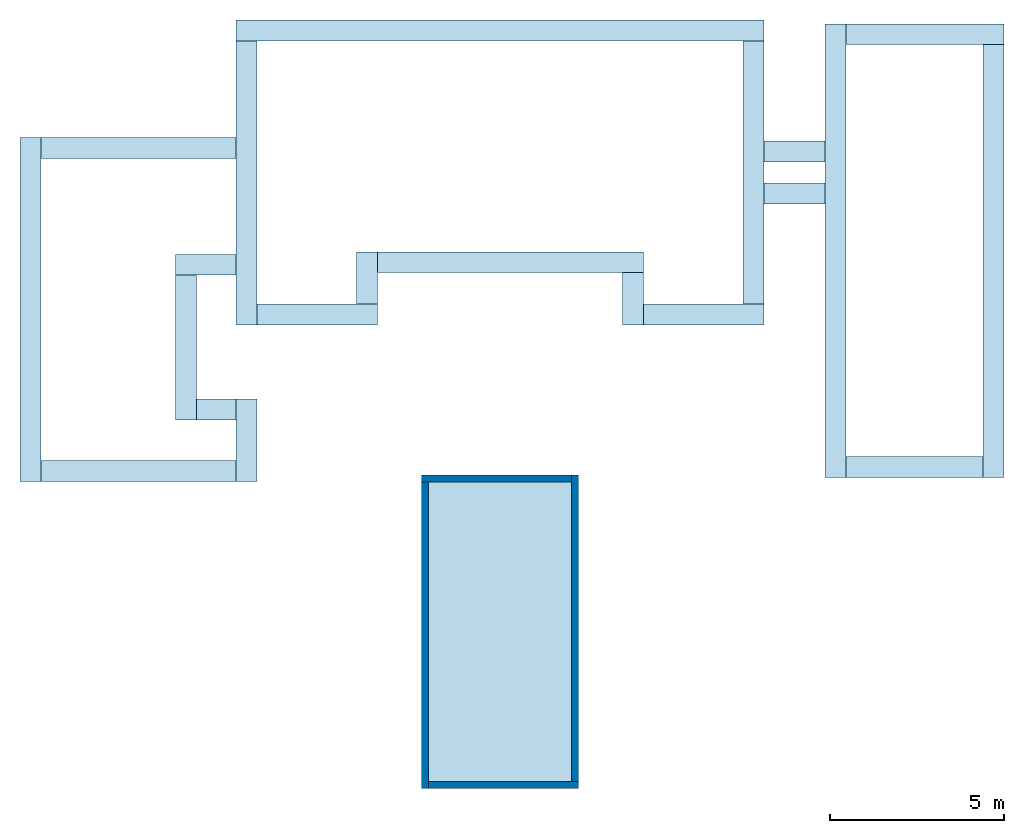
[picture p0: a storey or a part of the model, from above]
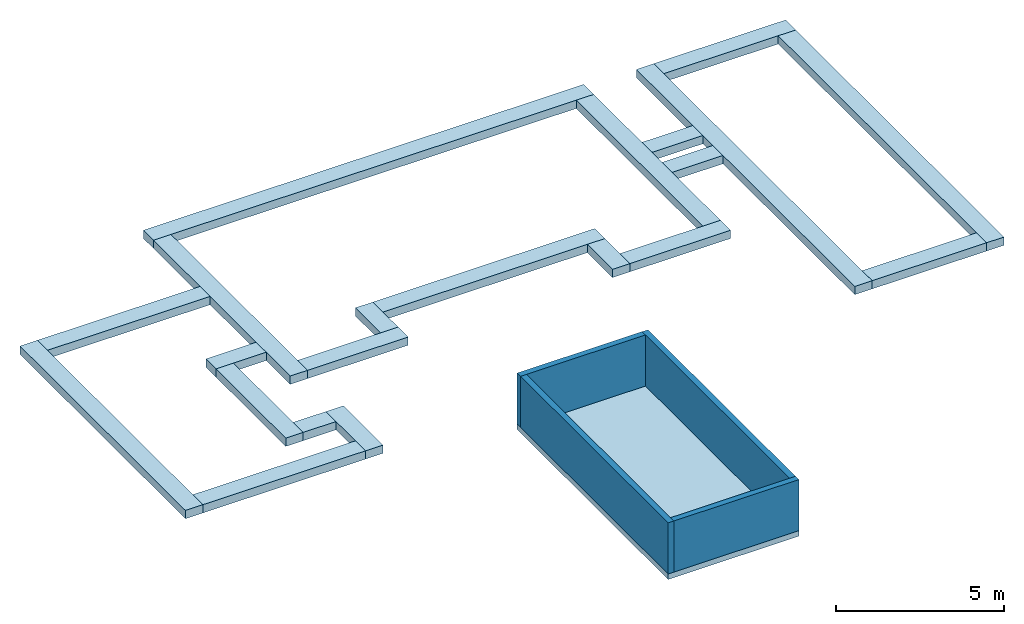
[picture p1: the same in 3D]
Properties of the parts of a building model (IFC2X3), part 1 of 4

# File
Description: ViewDefinition [CoordinationView_V2.0, QuantityTakeOffAddOnView]
File name: 4
Time: 2018-02-28T15:12:32
Written by: The EXPRESS Data Manager Version 5.02.0100.07 : 28 Aug 2013
Made in: 20150220_1215(x64) - Exporter 16.6.0.0 - Interface alternative d'export 16.6.0.0
Comment: STEP Physical File produced by: The EXPRESS Data Manager Version 5.02.0100.07 : 28 Aug 2013 * Module: EDMstepFileFactory/EDMstandAlone * Creation date: Wed Feb 28 15:12:32 2018 * Host: ESTEBAN-PASCAL * Database: C:\Users\Pascal\AppData\Local\Temp\{EC5FFBB5-4C97-4CA5-B8AF-28A79EC34BFA}\ifc * Database version: 5507 * Database creation date: Wed Feb 28 15:12:17 2018 * Schema: IFC2X3 * Model: DataRepository.ifc * Model creation date: Wed Feb 28 15:12:22 2018 * Header model: DataRepository.ifc_HeaderModel * Header model creation date: Wed Feb 28 15:12:22 2018 * EDMuser: sdai-user * EDMgroup: sdai-group * License ID and type: 5605 : Permanent license. Expiry date: * EDMstepFileFactory options: 020000

# IfcProject, 4
LongName: Projet Formation Revit 2016 - Module Initiation; Phase: Etat du projet

# IfcSite, Surface:366192
RefLatitude: 48, 51, 23, 999633; RefLongitude: 2, 21, 3, 553905; RefElevation: 0 m
Autre - Catégorie: Topographie; Déblais: 0 m3; Déblais/remblais net: 0 m3; Remblais: 0 m3
Cotes - Surface: 898.202 m2; Surface projetée: 898.173 m2
Phase de construction - Phase de création: Nouvelle construction

# IfcBuilding
Pset_BuildingCommon - NumberOfStoreys: 8
Autre - Adresse du projet: Entrer l'adresse ici; Catégorie: Informations sur le projet; Date de fin du projet: Mars 2017; Etat du projet: Etat du projet; Nom du client: Pascal Esteban; Nom du projet: Projet Formation Revit 2016 - Module Initiation; Numéro de projet: 4

# IfcBuildingStorey (8)
Autre - Catégorie: Niveaux; Famille: Niveau: Ligne du Niveau; Famille et type: Niveau: Ligne du Niveau; ID du type: Niveau: Ligne du Niveau; Type: Niveau: Ligne du Niveau
Cotes - Hauteur de calcul: 0 m
Données d'identification - Structure: no; Etage de bâtiment: yes
Autre(Type) - Catégorie: Niveaux; Nom de la famille: Niveau
Contraintes(Type) - Base de l'élévation: Point de base du projet
Données d'identification(Type) - Nom du type: Ligne du Niveau
Graphismes(Type) - Couleur: 12632256; Epaisseur des lignes: 1; Motif des lignes: Tiret point; Symbole: Marqueur de niveau - Point triangulaire: Marqueur de niveau - Point triangulaire; Valeur par défaut du symbole à l'extrémité 1: no; Valeur par défaut du symbole à l'extrémité 2: yes
Name | LongName = Nom | Elevation (m) | Elévation (m)
PIscine | PIscine | -2.2 | -2.2
1 Mur de soubassement | 1 Mur de soubassement | -1 | -1
RDC | RDC | -1.09416e-13 | 0
RDC Faux Plafond | RDC Faux Plafond | 2.5 | 2.5
1er ETAGE | 1er ETAGE | 3 | 3
RDC Acrotère | RDC Acrotère | 3.2 | 3.2
Mur rideau | Mur rideau | 5 | 5
1er Chainage | 1er Chainage | 5.8 | 5.8

# IfcSpace (24)
InteriorOrExteriorSpace: INTERNAL
BaseQuantities - Height: 2.4384 m
Analyse d'énergie - Charge d'éclairage basse sur: <Par défaut>; Charge d'éclairage réelle par surface: 0; Charge d'éclairage spécifiée: 0 W; Charge d'éclairage spécifiée par surface: 10.7639; Charge de puissance basse sur: <Par défaut>; Charge de puissance réelle: 0 W; Charge de puissance réelle par surface: 0; Charge de puissance spécifiée: 0 W; Charge de puissance spécifiée par surface: 13.9931; Charge réelle d'éclairage: 0 W; Contribution à l'éclairage du plénum: 0.2; Gain de chaleur latente par personne: 630.918; Gain de chaleur perceptible par personne: 788.648; Gain de chaleur total par personne: 1419.57; Nombre de personnes: 0; Surface par personne: 28.5714 m2; Unités de charge d'éclairage: Densité de puissance; Unités de charge de puissance: Densité de puissance; Valeurs de charge de chauffage: <Par défaut>
Autre - Catégorie: Pièces; ID de phase: Nouvelle construction
Contraintes - Décalage inférieur: 0 m; Décalage limite: 2.4384 m
Cotes - Hauteur de calcul: 0 m; Hauteur non liée: 2.4384 m
Phase de construction - Phase: Nouvelle construction
Name | In | LongName = Nomenclature des pièces, Nom = Données d'identification, Nom | Reference | Nombre = Numéro | Nomenclature des pièces, Niveau = Contraintes, Niveau | NetFloorArea (m2) = GrossFloorArea (m2) = Surface (m2) | GrossPerimeter (m) | GrossVolume (m3) | Limite supérieure | Périmètre (m)
1 | RDC | Salle d'eau | Salle d'eau 1 | 1 | RDC | 1.63725 | 5.39 | 3.99227 | Niveau: RDC | 5.39
2 | RDC | Chambre 1 | Chambre 1 2 | 2 | RDC | 13.674 | 14.96 | 33.3427 | Niveau: RDC | 14.96
3 | RDC | Dégmt ch | Dégmt ch 3 | 3 | RDC | 1.44 | 4.8 | 3.5113 | Niveau: RDC | 4.8
4 | RDC | Chambre 2 | Chambre 2 4 | 4 | Niveau: RDC | 22.038 | 23.94 | 53.7375 | Niveau: RDC | 23.94
5 | RDC | Placard ch. 2 | Placard ch. 2 5 | 5 | Niveau: RDC | 0.9016 | 4.84 | 2.19846 | Niveau: RDC | 4.84
6 | RDC | Passerelle | Passerelle 6 | 6 | RDC | 2.5 | 6.5 | 6.096 | Niveau: RDC | 6.5
7 | RDC | Gaine | Gaine 7 | 7 | Niveau: RDC | 0.28372 | 2.204 | 0.691823 | Niveau: RDC | 2.204
8 | RDC | Placard ch. 1 | Placard ch. 1 8 | 8 | Niveau: RDC | 1.0388 | 4.98 | 2.53301 | Niveau: RDC | 4.98
9 | RDC | Salle de bain ch. 2 | Salle de bain ch. 2 9 | 9 | RDC | 5.65307 | 11.85 | 13.7844 | Niveau: RDC | 11.85
10 | RDC | Garage | Garage 10 | 10 | RDC | 39.655 | 30.14 | 96.6948 | Niveau: RDC | 30.175
11 | RDC | Dgmt garage | Dgmt garage 11 | 11 | RDC | 2.718 | 6.93 | 6.62757 | Niveau: RDC | 6.84922
12 | RDC | Cellier | Cellier 12 | 12 | RDC | 6.72 | 10.6 | 16.386 | Niveau: RDC | 10.6
13 | RDC | Salon | Salon 13 | 13 | RDC | 19.5219 | 18.48 | 47.6022 | Niveau: RDC | 18.48
14 | RDC | Escalier | Escalier 14 | 14 | Niveau: RDC | 7.2267 | 10.96 | 17.6216 | Niveau: RDC | 10.96
15 | RDC | Entrée | Entrée 15 | 15 | RDC | 9.03204 | 12.5707 | 22.0237 | Niveau: RDC | 12.0237
16 | RDC | Circulation | Circulation 16 | 16 | RDC | 12.912 | 23.92 | 31.4846 | Niveau: RDC | 23.3689
17 | RDC | Dgmt cellier | Dgmt cellier 17 | 17 | Niveau: RDC | 4.374 | 9.69 | 10.6656 | Niveau: RDC | 9.76
18 | RDC | Placard entrée | Placard entrée 18 | 18 | RDC | 1.49435 | 8.01 | 3.64382 | Niveau: RDC | 8.01
19 | RDC | Espace lecture | Espace lecture 19 | 19 | Niveau: RDC | 10.2139 | 12.95 | 24.9056 | Niveau: RDC | 12.95
20 | RDC | Salle à manger | Salle à manger 20 | 20 | RDC | 14.6431 | 19.01 | 35.7057 | Niveau: RDC | 18.798
21 | RDC | Cuisine | Cuisine 21 | 21 | RDC | 12.3324 | 14.12 | 30.0713 | Niveau: RDC | 14.085
22 | RDC | Salle de bain ch. 1 | Salle de bain ch. 1 22 | 22 | RDC | 5.72307 | 11.99 | 13.9551 | Niveau: RDC | 11.99
23 | RDC | WC | WC 23 | 23 | Niveau: RDC | 2.124 | 5.94 | 5.17916 | Niveau: RDC | 6.07
24 | 1er ETAGE | Mezzanine | Mezzanine 24 | 24 | Niveau: 1er ETAGE | 58.6738 | 44.02 | 143.07 | Niveau: 1er ETAGE | 44.185

# IfcBeam: Poutre - Lamellé-collé - Pin du sud:127X279 (11)
In: 1er ETAGE
Type - PredefinedType: BEAM
Type - Autre(Type) - Catégorie: Ossature; Nom de la famille: Poutre - Lamellé-collé - Pin du sud
Type - Cotes(Type) - b: 0.127 m; d: 0.279 m
Type - Données d'identification(Type) - Nom du type: 127X279
Type - Structure(Type) - Forme de coupe: 0
Material: Bois - Bois de construction de dimensions courantes
Pset_BeamCommon - LoadBearing: yes; IsExternal: no; Reference: 127X279; Slope: 0 deg
Autre - Catégorie: Ossature; Famille: Poutre - Lamellé-collé - Pin du sud: 127X279; Famille et type: Poutre - Lamellé-collé - Pin du sud: 127X279; ID du type: Poutre - Lamellé-collé - Pin du sud: 127X279; Type: Poutre - Lamellé-collé - Pin du sud: 127X279
Contraintes - Décalage du niveau d'arrivée: 0 m; Décalage du niveau de départ: 0 m; Elévation du niveau de référence: 3 m; Niveau de référence: Niveau: 1er ETAGE; Orientation: Normale; Plan de construction: Niveau : 1er ETAGE; Rotation de la section: 0 deg
Cotes - Elévation à la base: 2.721 m; Elévation en haut: 3 m
Matériaux et finitions - Matériau structurel: Bois - Bois de construction de dimensions courantes
Phase de construction - Phase de création: Nouvelle construction
Position géométrique - Etat de la jonction: Deux jonctions activées; Extension de départ: 0 m; Extension de fin: 0 m; Justification Y: Origine; Justification YZ: Uniforme; Justification Z: Haut; Valeur de décalage Y: 0 m; Valeur de décalage Z: 0 m
Structure - Activer le modèle analytique: yes; Emplacement du symbole filaire: Centre de la géométrie; Utilisation structurelle: Autre
Name (Poutre - Lamellé-collé - Pin du sud:127X279:...) | GrossVolume (m3) = NetVolume (m3) = Volume (m3) | NetSurfaceArea (m2) | Longueur (m) | Longueur de coupe (m) | Group | Réduction du joint d'extrémité (m)
307954 | 0.15835 | 3.69969 | 4.469 | 4.469 | Groupe de modèles:Groupe de réseaux 1:310685
310688 | 0.15835 | 3.69969 | 4.569 | 4.469 | Groupe de modèles:Groupe de réseaux 1:310690 | 0
310720 | 0.15835 | 3.69969 | 4.569 | 4.469 | Groupe de modèles:Groupe de réseaux 1:310722 | 0
310724 | 0.15835 | 3.69969 | 4.569 | 4.469 |  | 0
310728 | 0.15835 | 3.69969 | 4.569 | 4.469 | Groupe de modèles:Groupe de réseaux 1:310730 | 0
311005 | 0.15835 | 3.69969 | 4.569 | 4.469 | Groupe de modèles:Groupe de réseaux 1:311007 | 0
311008 | 0.15835 | 3.69969 | 4.569 | 4.469 | Groupe de modèles:Groupe de réseaux 1:311010 | 0
311011 | 0.15835 | 3.69969 | 4.569 | 4.469 | Groupe de modèles:Groupe de réseaux 1:311013 | 0
311014 | 0.15835 | 3.69969 | 4.569 | 4.469 |  | 0
311017 | 0.15835 | 3.69969 | 4.569 | 4.469 | Groupe de modèles:Groupe de réseaux 1:311019 | 0
318877 | 0.0778817 | 1.85564 | 2.326 | 2.198 |  | 0 | Position géométrique - Réduction du joint de début: 0 m

# IfcBeam: Poutre rectangulaire - Béton:200 x 400 mm, Poutre rectangulaire - Béton:200 x 400 mm:311577
In: 1er ETAGE
Type - PredefinedType: BEAM
Type - Autre(Type) - Catégorie: Ossature; Nom de la famille: Poutre rectangulaire - Béton
Type - Cotes(Type) - b: 0.2 m; h: 0.4 m
Type - Données d'identification(Type) - Nom du type: 200 x 400 mm
Type - Structure(Type) - Forme de coupe: 0
Material: Béton - Béton coulé sur place
BaseQuantities - GrossVolume: 1.14016 m3; NetSurfaceArea: 17.2624 m2; NetVolume: 1.14016 m3
Pset_BeamCommon - LoadBearing: yes; IsExternal: no; Slope: 0 deg; Reference: 200 x 400 mm
Autre - Catégorie: Ossature; Famille: Poutre rectangulaire - Béton: 200 x 400 mm; Famille et type: Poutre rectangulaire - Béton: 200 x 400 mm; ID du type: Poutre rectangulaire - Béton: 200 x 400 mm; Type: Poutre rectangulaire - Béton: 200 x 400 mm
Contraintes - Décalage du niveau d'arrivée: 0 m; Décalage du niveau de départ: 0 m; Niveau de référence: Niveau: 1er ETAGE; Orientation: Normale; Rotation de la section: 0 deg; Elévation du niveau de référence: 3 m; Plan de construction: Niveau : 1er ETAGE
Cotes - Elévation à la base: 2.6 m; Elévation en haut: 3 m; Longueur: 14.339 m; Surface: 8.63118 m2; Volume: 1.14016 m3
Matériaux et finitions - Matériau structurel: Béton - Béton coulé sur place
Phase de construction - Phase de création: Nouvelle construction
Position géométrique - Justification Y: Origine; Justification YZ: Uniforme; Justification Z: Haut; Valeur de décalage Y: 0 m; Valeur de décalage Z: 0 m; Etat de la jonction: Une ou deux jonctions activées
Structure - Activer le modèle analytique: yes; Enrobage d'armature - Autres faces: Paramètres de l'enrobage d'armature: Enrobage d'armature 1; Enrobage d'armature - Face inférieure: Paramètres de l'enrobage d'armature: Enrobage d'armature 1; Enrobage d'armature - Face supérieure: Paramètres de l'enrobage d'armature: Enrobage d'armature 1; Utilisation structurelle: Autre; Longueur de coupe: 14.252 m

# IfcBuildingElementProxy: 100 mm, TV - Ecran plat:100 mm:445774
In: 13
Type - Material: TV - Cadre, TV - Noir, TV - Verre
Type - Autre(Type) - Catégorie: Equipement spécialisé; Nom de la famille: TV - Ecran plat
Type - Cotes(Type) - CosAng: 0.000871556 m; Diagonale: 1 m; Epaisseur: 0.08 m; H: 0.490295 m; L: 0.871556 m; SinAng: 0.000490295 m
Type - Données d'identification(Type) - Nom du type: 100 mm
Type - Matériaux et finitions(Type) - Cadre: TV - Cadre
Pset_BuildingElementProxyCommon - Reference: 100 mm
Autre - Catégorie: Equipement spécialisé; Famille: TV - Ecran plat: 100 mm; Famille et type: TV - Ecran plat: 100 mm; ID du type: TV - Ecran plat: 100 mm; Type: TV - Ecran plat: 100 mm
Contraintes - Niveau: Niveau: RDC; Se déplace avec les éléments voisins: no; Décalage: 0.42 m; Hôte: Sol : S5 Plancher flottant habitable
Cotes - Surface: 1.48572 m2; Volume: 0.0550081 m3
Graphismes - Pied: yes
Phase de construction - Phase de création: Nouvelle construction

# IfcBuildingElementProxy: 1456153326143_Kitchen_ExhaustHood, 1456153326143_Kitchen_ExhaustHood:1456153326143_Kitchen_ExhaustHood:540276
In: 21
Type - Material: Sp. Equipment - Kitchen Exhaust Hood - Metal Accent2, Sp. Equipment - Kitchen Exhaust Hood - Metal Accent1, Sp. Equipment - Kitchen Exhaust Hood - Hood Edge
Type - Autre(Type) - Catégorie: Equipement spécialisé; LIGHTING OFF: yes; Nom de la famille: 1456153326143_Kitchen_ExhaustHood
Type - Cotes(Type) - Hood Depth: 0.1016 m
Type - Données d'identification(Type) - Nom du type: 1456153326143_Kitchen_ExhaustHood
Pset_BuildingElementProxyCommon - Reference: 1456153326143_Kitchen_ExhaustHood
Autre - Catégorie: Equipement spécialisé; Famille: 1456153326143_Kitchen_ExhaustHood: 1456153326143_Kitchen_ExhaustHood; Famille et type: 1456153326143_Kitchen_ExhaustHood: 1456153326143_Kitchen_ExhaustHood; ID du type: 1456153326143_Kitchen_ExhaustHood: 1456153326143_Kitchen_ExhaustHood; LS_L: 0.9 m; Type: 1456153326143_Kitchen_ExhaustHood: 1456153326143_Kitchen_ExhaustHood
Contraintes - Niveau: Niveau: RDC; Se déplace avec les éléments voisins: no; Décalage: -0.54 m; Hôte: Sol : Plan de travail cuisine
Cotes - B.O Hood to Floor: 1.35 m; Exhaust Length: 0.2286 m; Exhaust Width: 0.2286 m; Hood Length: 0.9144 m; Hood Width: 0.6096 m; Surface: 7.51254 m2; T.O. Hood to Floor: 2.3622 m; Volume: 0.968507 m3
Matériaux et finitions - Hood Edge: Sp. Equipment - Kitchen Exhaust Hood - Hood Edge; Metal Accent 1: Sp. Equipment - Kitchen Exhaust Hood - Metal Accent1; Metal Accent2: Sp. Equipment - Kitchen Exhaust Hood - Metal Accent2
Phase de construction - Phase de création: Nouvelle construction

# IfcBuildingElementProxy: 600mm x 590mm x 820mm (3)
In: 12
Type - Material: Peinture - Ivoire
Type - Autre(Type) - Catégorie: Equipement spécialisé; Nom de la famille: Sèche linge - 01
Type - Cotes(Type) - Hauteur: 0.82 m; Largeur: 0.6 m; Profondeur: 0.59 m
Type - Données d'identification(Type) - Nom du type: 600mm x 590mm x 820mm
Type - Matériaux et finitions(Type) - Finition: Peinture - Ivoire
Pset_BuildingElementProxyCommon - Reference: 600mm x 590mm x 820mm
Autre - Catégorie: Equipement spécialisé; Famille: Sèche linge - 01: 600mm x 590mm x 820mm; Famille et type: Sèche linge - 01: 600mm x 590mm x 820mm; ID du type: Sèche linge - 01: 600mm x 590mm x 820mm; Type: Sèche linge - 01: 600mm x 590mm x 820mm
Contraintes - Niveau: Niveau: RDC; Se déplace avec les éléments voisins: no; Décalage: 0 m; Hôte: Sol : S5 Plancher flottant habitable
Cotes - Surface: 1.8173 m2; Volume: 0.292316 m3
Phase de construction - Phase de création: Nouvelle construction
Name (Sèche linge - 01:600mm x 590mm x 820mm:...)
424746
551144
551240

# IfcBuildingElementProxy: 600mm x 590mm x 820mm, Lave linge - Chargement frontal:600mm x 590mm x 820mm:423703
In: 12
Type - Material: Peinture - Ivoire, Verre
Type - Autre(Type) - Catégorie: Equipement spécialisé; Nom de la famille: Lave linge - Chargement frontal
Type - Cotes(Type) - Hauteur: 0.82 m; Largeur: 0.6 m; Profondeur: 0.59 m
Type - Données d'identification(Type) - Nom du type: 600mm x 590mm x 820mm
Type - Matériaux et finitions(Type) - Finition: Peinture - Ivoire
Pset_BuildingElementProxyCommon - Reference: 600mm x 590mm x 820mm
Autre - Catégorie: Equipement spécialisé; Famille: Lave linge - Chargement frontal: 600mm x 590mm x 820mm; Famille et type: Lave linge - Chargement frontal: 600mm x 590mm x 820mm; ID du type: Lave linge - Chargement frontal: 600mm x 590mm x 820mm; Type: Lave linge - Chargement frontal: 600mm x 590mm x 820mm
Contraintes - Niveau: Niveau: RDC; Se déplace avec les éléments voisins: no; Décalage: 0 m; Hôte: Sol : S5 Plancher flottant habitable
Cotes - Surface: 2.15169 m2; Volume: 0.247328 m3
Phase de construction - Phase de création: Nouvelle construction

# IfcBuildingElementProxy: 915 x 500 mm, Plaque de cuisson - 4 unités:915 x 500 mm:543399
In: 21
Type - Material: Métal - Chrome, Métal - Acier, Poli
Type - Autre(Type) - Catégorie: Equipement spécialisé; Nom de la famille: Plaque de cuisson - 4 unités
Type - Cotes(Type) - Largeur: 0.915 m; Profondeur: 0.5 m
Type - Données d'identification(Type) - Nom du type: 915 x 500 mm
Type - Matériaux et finitions(Type) - Brûleur: Métal - Chrome; Plaque de cuisson: Métal - Acier, Poli
Pset_BuildingElementProxyCommon - Reference: 915 x 500 mm
Autre - Catégorie: Equipement spécialisé; Famille: Plaque de cuisson - 4 unités: 915 x 500 mm; Famille et type: Plaque de cuisson - 4 unités: 915 x 500 mm; ID du type: Plaque de cuisson - 4 unités: 915 x 500 mm; Type: Plaque de cuisson - 4 unités: 915 x 500 mm
Contraintes - Niveau: Niveau: RDC; Se déplace avec les éléments voisins: no; Décalage: 0 m; Hôte: Sol : S5 Plancher flottant habitable
Cotes - Surface: 0.741723 m2; Volume: 0.0101652 m3
Phase de construction - Phase de création: Nouvelle construction

# IfcBuildingElementProxy: Chêne écarlate - 6 mètres, RPC Arbre - Feuilles caduques:Chêne écarlate - 6 mètres:369386
In: RDC
Type - Autre(Type) - Catégorie: Plantes; Nom de la famille: RPC Arbre - Feuilles caduques
Type - Cotes(Type) - Hauteur: 6 m
Type - Données d'identification(Type) - Apparence de rendu: RPC-16-G0FB-J5PX-0LX6-U000-ST1L-LVER-AU; Commentaires du type: Chêne écarlate; Nom du type: Chêne écarlate - 6 mètres; Propriétés de l'apparence de rendu: {2, 15},{39, RPC-16-G0FB-J5PX-0LX6-U000-ST1L-LVER-AU},{1, 0},{1, 0},{2, 13},{1, 8},{5, Color},{1, 0},{1, 0},{3, 0.8},{3, 0.8},{3, 0.8},{1, 8},{7, BBoxMin},{1, 0},{1, 0},{1, 0},{1, 0},{1, 0},{1, 8},{7, BBoxMax},{1, 0},{1, 0},{1, 0},{1, 0},{1, 0},{2, 11},{9, RPCTypeId},{1, 0},{1, 0},{39, RPC-16-G0FB-J5PX-0LX6-U000-ST1L-LVER-AU},{1, 6},{14, RPCPlantHeight},{1, 0},{1, 0},{7, 41.0105},{2, 11},{7, keyword},{1, 0},{1, 0},{34, :RPCs:Trees [General]:Geometry:RPC},{2, 11},{8, category},{1, 0},{1, 0},{15, Trees [General]},{2, 11},{12, LocalizedUID},{1, 0},{1, 0},{11, Scarlet_Oak},{2, 14},{6, Height},{1, 0},{1, 0},{7, 41.0105},{1, 2},{16, Cast Reflections},{1, 0},{1, 0},{1, 0},{1, 2},{12, Cast Shadows},{1, 0},{1, 0},{1, 1},{1, 2},{9, Lock View},{1, 0},{1, 0},{1, 0},{1, 4},{5, ViewC},{1, 0},{1, 0},{1, 0},{21, assetlibrary_base.fbx},{1, 5},
Pset_BuildingElementProxyCommon - Reference: Chêne écarlate - 6 mètres
Autre - Catégorie: Plantes; Famille: RPC Arbre - Feuilles caduques: Chêne écarlate - 6 mètres; Famille et type: RPC Arbre - Feuilles caduques: Chêne écarlate - 6 mètres; ID du type: RPC Arbre - Feuilles caduques: Chêne écarlate - 6 mètres; Type: RPC Arbre - Feuilles caduques: Chêne écarlate - 6 mètres
Contraintes - Niveau: Niveau: RDC; Se déplace avec les éléments voisins: no; Décalage: 0 m; Hôte: Surface
Phase de construction - Phase de création: Nouvelle construction

# IfcBuildingElementProxy: Chêne écarlate - 8 mètres (2)
In: RDC
Type - Autre(Type) - Catégorie: Plantes; Nom de la famille: RPC Arbre - Feuilles caduques
Type - Cotes(Type) - Hauteur: 8 m
Type - Données d'identification(Type) - Apparence de rendu: RPC-16-G0FB-J5PX-0LX6-U000-ST1L-LVER-AU; Commentaires du type: Chêne écarlate; Nom du type: Chêne écarlate - 8 mètres; Propriétés de l'apparence de rendu: {2, 15},{39, RPC-16-G0FB-J5PX-0LX6-U000-ST1L-LVER-AU},{1, 0},{1, 0},{2, 13},{1, 8},{5, Color},{1, 0},{1, 0},{3, 0.8},{3, 0.8},{3, 0.8},{1, 8},{7, BBoxMin},{1, 0},{1, 0},{1, 0},{1, 0},{1, 0},{1, 8},{7, BBoxMax},{1, 0},{1, 0},{1, 0},{1, 0},{1, 0},{2, 11},{9, RPCTypeId},{1, 0},{1, 0},{39, RPC-16-G0FB-J5PX-0LX6-U000-ST1L-LVER-AU},{1, 6},{14, RPCPlantHeight},{1, 0},{1, 0},{7, 41.0105},{2, 11},{7, keyword},{1, 0},{1, 0},{34, :RPCs:Trees [General]:Geometry:RPC},{2, 11},{8, category},{1, 0},{1, 0},{15, Trees [General]},{2, 11},{12, LocalizedUID},{1, 0},{1, 0},{11, Scarlet_Oak},{2, 14},{6, Height},{1, 0},{1, 0},{7, 41.0105},{1, 2},{16, Cast Reflections},{1, 0},{1, 0},{1, 0},{1, 2},{12, Cast Shadows},{1, 0},{1, 0},{1, 1},{1, 2},{9, Lock View},{1, 0},{1, 0},{1, 0},{1, 4},{5, ViewC},{1, 0},{1, 0},{1, 0},{21, assetlibrary_base.fbx},{1, 5},
Pset_BuildingElementProxyCommon - Reference: Chêne écarlate - 8 mètres
Autre - Catégorie: Plantes; Famille: RPC Arbre - Feuilles caduques: Chêne écarlate - 8 mètres; Famille et type: RPC Arbre - Feuilles caduques: Chêne écarlate - 8 mètres; ID du type: RPC Arbre - Feuilles caduques: Chêne écarlate - 8 mètres; Type: RPC Arbre - Feuilles caduques: Chêne écarlate - 8 mètres
Contraintes - Niveau: Niveau: RDC; Se déplace avec les éléments voisins: no; Décalage: 0 m; Hôte: Surface
Phase de construction - Phase de création: Nouvelle construction
Name (RPC Arbre - Feuilles caduques:Chêne écarlate - 8 mètres:...)
369457
369516

# IfcBuildingElementProxy: FERME (3)
In: 1er Chainage
Type - Material: bois de charpente
Type - Autre(Type) - Catégorie: Ossature; demi panne: 0.06 m; Nom de la famille: FERME; Recouvrement mur: 0.3 m
Type - Cotes(Type) - angle d'inclinaison: 19.29 deg; hauteur arbaletrier: 0.2 m; section h entrait: 0.3 m; section h faitiere: 0.22 m; section p entrait: 0.25 m; section p panne faitiere: 0.12 m; section p sablière: 0.12 m
Type - Données d'identification(Type) - Nom du type: FERME
Type - Structure(Type) - Forme de coupe: 0
Pset_BuildingElementProxyCommon - Reference: FERME
Autre - Catégorie: Ossature; demi poincon: 0.1 m; Famille: FERME: FERME; Famille et type: FERME: FERME; ID du type: FERME: FERME; longueur arbaletrier: 4.02603 m; nombre de pannes: 1; position panne intermediaire: 2.01301 m; Type: FERME: FERME; vis p1: yes; vis p2: no; vis p3: no; vis p4: no
Construction - pannes: yes
Contraintes - Décalage: 0.5 m; Hôte: Niveau : 1er Chainage; Niveau: Niveau: 1er Chainage; Se déplace avec les éléments voisins: no
Cotes - largeur ferme: 7.8 m; Section h contrefiche: 0.2 m; section h panne intermediaire: 0.22 m; section poincon: 0.2 m; section p panne intermediaire: 0.1 m
Matériaux et finitions - Matériau structurel: bois de charpente
Phase de construction - Phase de création: Nouvelle construction
Structure - Enrobage d'armature - Autres faces: Paramètres de l'enrobage d'armature: Enrobage d'armature 1; Enrobage d'armature - Face inférieure: Paramètres de l'enrobage d'armature: Enrobage d'armature 1; Enrobage d'armature - Face supérieure: Paramètres de l'enrobage d'armature: Enrobage d'armature 1; Utilisation structurelle: Autre
Name (FERME:FERME:...) | Longueur debord (m) | Longueur panne (m) | Surface (m2) | Volume (m3)
340418 | 3.44427 | 0.135733 | 23.3554 | 1.64093
346890 | 3.44427 | 0.135733 | 23.3554 | 1.64093
346964 | 3.7007 | 3.6993 | 36.8101 | 2.08505

# IfcBuildingElementProxy: Mechanical_COM_Popup-Toaster, Mechanical_COM_Popup-Toaster:Mechanical_COM_Popup-Toaster:545730
In: 21
Type - Material: ARCAT - Plastic - Black, ARCAT - Metal - Satin Steel
Type - Autre(Type) - Catégorie: Equipement de génie climatique; Nom de la famille: Mechanical_COM_Popup-Toaster
Type - Construction(Type) - Four Compartments: no; Two Compartments: yes
Type - Contraintes(Type) - Elévation par défaut: 1.2192 m; fourcompartmentvoid: 0.03175 m; fourcomparttrigger: 0.0254 m; twocomparttrigger: 0.0762 m; twocompartvoid: 0.174625 m
Type - Cotes(Type) - Unit Depth: 0.2159 m; Unit Height: 0.22225 m; Unit Width: 0.3429 m
Type - Données d'identification(Type) - Company_ID: 0; Nom du type: Mechanical_COM_Popup-Toaster; Numéro OmniClass: 23.40.40.14; Titre OmniClass: Food Service Equipment
Type - Phase de construction(Type) - Expected Lifespan (Years): 0; Maintenance Schedule (Months): 0; Warranty Duration (Years): 0
Pset_BuildingElementProxyCommon - Reference: Mechanical_COM_Popup-Toaster
Autre - Niveau de nomenclature: Niveau: RDC; Catégorie: Equipement de génie climatique; Famille: Mechanical_COM_Popup-Toaster: Mechanical_COM_Popup-Toaster; Famille et type: Mechanical_COM_Popup-Toaster: Mechanical_COM_Popup-Toaster; ID du type: Mechanical_COM_Popup-Toaster: Mechanical_COM_Popup-Toaster; Type: Mechanical_COM_Popup-Toaster: Mechanical_COM_Popup-Toaster
Contraintes - Niveau: Niveau: RDC; Décalage: 0 m; Plan de construction: PTD : Avec réservation pour évier
Cotes - Surface: 0.325476 m2; Volume: 0.012359 m3
Données d'identification - Identifiant: 1
Génie climatique - Classification du système: Puissance
Matériaux et finitions - Face Plate: ARCAT - Plastic - Black; Feet Material: ARCAT - Plastic - Black; Fixture Material: ARCAT - Metal - Satin Steel; Hardware Finish: ARCAT - Plastic - Black
Phase de construction - Phase de création: Nouvelle construction

# IfcBuildingElementProxy: Palmier - 6 m (7)
In: RDC
Type - Autre(Type) - Catégorie: Plantes; Nom de la famille: Arbre 3D - Palmier
Type - Cotes(Type) - Hauteur: 6 m
Type - Données d'identification(Type) - Apparence de rendu: RPC-16-FVGV-NKG0-7NHH-C000-ST1L-LVER-AU; Nom du type: Palmier - 6 m; Numéro OmniClass: 23.40.05.00; Titre OmniClass: Plants and Planting Products
Pset_BuildingElementProxyCommon - Reference: Palmier - 6 m
Autre - Catégorie: Plantes; Famille: Arbre 3D - Palmier: Palmier - 6 m; Famille et type: Arbre 3D - Palmier: Palmier - 6 m; ID du type: Arbre 3D - Palmier: Palmier - 6 m; Type: Arbre 3D - Palmier: Palmier - 6 m
Contraintes - Niveau: Niveau: RDC; Se déplace avec les éléments voisins: no; Décalage: 0 m; Hôte: Surface
Phase de construction - Phase de création: Nouvelle construction
Name (Arbre 3D - Palmier:Palmier - 6 m:...)
378889
379057
379459
379478
379527
379637
379660

# IfcBuildingElementProxy: Palmier - 8 m (2)
In: RDC
Type - Autre(Type) - Catégorie: Plantes; Nom de la famille: Arbre 3D - Palmier
Type - Cotes(Type) - Hauteur: 8 m
Type - Données d'identification(Type) - Apparence de rendu: RPC-16-FVGV-NKG0-7NHH-C000-ST1L-LVER-AU; Nom du type: Palmier - 8 m; Numéro OmniClass: 23.40.05.00; Titre OmniClass: Plants and Planting Products
Pset_BuildingElementProxyCommon - Reference: Palmier - 8 m
Autre - Catégorie: Plantes; Famille: Arbre 3D - Palmier: Palmier - 8 m; Famille et type: Arbre 3D - Palmier: Palmier - 8 m; ID du type: Arbre 3D - Palmier: Palmier - 8 m; Type: Arbre 3D - Palmier: Palmier - 8 m
Contraintes - Niveau: Niveau: RDC; Se déplace avec les éléments voisins: no; Décalage: 0 m; Hôte: Surface
Phase de construction - Phase de création: Nouvelle construction
Name (Arbre 3D - Palmier:Palmier - 8 m:...)
378946
379369

# IfcBuildingElementProxy: Palmier -3 m (5)
Type - Autre(Type) - Catégorie: Plantes; Nom de la famille: Arbre 3D - Palmier
Type - Cotes(Type) - Hauteur: 3 m
Type - Données d'identification(Type) - Apparence de rendu: RPC-16-FVGV-NKG0-7NHH-C000-ST1L-LVER-AU; Nom du type: Palmier -3 m; Numéro OmniClass: 23.40.05.00; Titre OmniClass: Plants and Planting Products
Pset_BuildingElementProxyCommon - Reference: Palmier -3 m
Autre - Catégorie: Plantes; Famille: Arbre 3D - Palmier: Palmier -3 m; Famille et type: Arbre 3D - Palmier: Palmier -3 m; ID du type: Arbre 3D - Palmier: Palmier -3 m; Type: Arbre 3D - Palmier: Palmier -3 m
Contraintes - Se déplace avec les éléments voisins: no; Décalage: 0 m
Phase de construction - Phase de création: Nouvelle construction
Name (Arbre 3D - Palmier:Palmier -3 m:...) | In | Niveau | Hôte
379821 | RDC | Niveau: RDC | Niveau : RDC
379847 | 1 Mur de soubassement | Niveau: 1 Mur de soubassement | Surface
379902 | 1 Mur de soubassement | Niveau: 1 Mur de soubassement | Surface
379955 | 1 Mur de soubassement | Niveau: 1 Mur de soubassement | Surface
379998 | 1 Mur de soubassement | Niveau: 1 Mur de soubassement | Surface

# IfcBuildingElementProxy: Panneaux solaires sur support (3)
In: RDC Acrotère
Type - Material: Panneau solaire, Peinture - Gris métallisé
Type - Autre(Type) - Catégorie: Equipement spécialisé; Nom de la famille: Panneaux solaires sur support
Type - Contraintes(Type) - Longueur: 3.6 m; Longueur de barre: 1.8 m; Nombre de barres: 2; Nombre de panneaux: 6; Nombre de supports: 3
Type - Cotes(Type) - Hauteur support arrière: 0.7 m; Hauteur support avant: 0.3 m; Largeur des panneaux: 0.6 m; Profondeur des panneaux: 1.2 m
Type - Données d'identification(Type) - Nom du type: Panneaux solaires sur support
Type - Matériaux et finitions(Type) - Cadre des panneaux: Peinture - Gris métallisé; Finition des supports: Peinture - Gris métallisé
Pset_BuildingElementProxyCommon - Reference: Panneaux solaires sur support
Autre - Catégorie: Equipement spécialisé; Famille: Panneaux solaires sur support: Panneaux solaires sur support; Famille et type: Panneaux solaires sur support: Panneaux solaires sur support; ID du type: Panneaux solaires sur support: Panneaux solaires sur support; Type: Panneaux solaires sur support: Panneaux solaires sur support
Contraintes - Se déplace avec les éléments voisins: no; Décalage: 3.2 m; Hôte: Sol : Dallage garage; Niveau: Niveau: RDC Acrotère
Cotes - Surface: 6.27012 m2; Volume: 0.0689049 m3
Phase de construction - Phase de création: Nouvelle construction
Name (Panneaux solaires sur support:Panneaux solaires sur support:...)
453073
453309
453405

# IfcBuildingElementProxy: RPC Coccinelle, RPC Coccinelle:RPC Coccinelle:382846
In: RDC
Type - Autre(Type) - Catégorie: Environnement; Nom de la famille: RPC Coccinelle
Type - Cotes(Type) - Hauteur: 0 m
Type - Données d'identification(Type) - Apparence de rendu: RPC-16-0U6E-L4EG-ENH1-J3KF-SVEL-0TX4-C0; Nom du type: RPC Coccinelle; Propriétés de l'apparence de rendu: {2, 15},{39, RPC-16-0U6E-L4EG-ENH1-J3KF-SVEL-0TX4-C0},{1, 0},{1, 0},{2, 45},{1, 8},{5, Color},{1, 0},{1, 0},{3, 0.8},{3, 0.8},{3, 0.8},{1, 8},{7, BBoxMin},{1, 0},{1, 0},{1, 0},{1, 0},{1, 0},{1, 8},{7, BBoxMax},{1, 0},{1, 0},{1, 0},{1, 0},{1, 0},{2, 11},{9, RPCTypeId},{1, 0},{1, 0},{39, RPC-16-0U6E-L4EG-ENH1-J3KF-SVEL-0TX4-C0},{1, 6},{14, RPCPlantHeight},{1, 0},{1, 0},{4, 4.92},{2, 11},{7, keyword},{1, 0},{1, 0},{27, :Geometry:RPC:VW Beetle [4]},{2, 11},{8, category},{1, 0},{1, 0},{21, :Auto_Economy/Midsize},{2, 11},{12, LocalizedUID},{1, 0},{1, 0},{13, VW Beetle [4]},{2, 14},{6, Height},{1, 0},{1, 0},{4, 4.92},{1, 2},{16, Cast Reflections},{1, 0},{1, 0},{1, 0},{1, 4},{12, Transparency},{1, 0},{1, 0},{2, 18},{1, 4},{7, Tinting},{1, 0},{1, 0},{2, 50},{1, 2},{11, Use Tinting},{1, 0},{1, 0},{1, 0},{1, 2},{13, License Plate},{1, 0},{1, 0},{1, 0},{2, 11},{21, License Plate Texture},{1, 0},{1, 0},{64, __RPC:/object data/textures/car/plate/textures/default/rgb/0/0/0},{2, 11},{23, i_License Plate Texture},{1, 0},{1, 0},{0, },{1, 2},{12, Custom Plate},{1, 0},{1, 0},{1, 0},{2, 11},{23, License Plate File Name},{1, 0},{1, 0},{0, },{2, 11},{20, AdvancedUIDefinition},{1, 0},{1, 0},{0, },{2, 11},{10, AssetLibID},{1, 0},{1, 0},{36, 4D3F6E72-3F99-4203-98E9-AF80B3C7A7A4},{2, 11},{10, BaseSchema},{1, 0},{1, 0},{9, RPCSchema},{2, 11},{12, ExchangeGUID},{1, 0},{1, 0},{0, },{1, 2},{6, Hidden},{1, 0},{1, 0},{1, 0},{1, 4},{11, RPCCategory},{1, 0},{1, 0},{1, 0},{2, 11},{8, RPCImage},{1, 0},{1, 0},{0, },{1, 4},{13, SchemaVersion},{1, 0},{1, 0},{1, 4},{2, 11},{12, UIDefinition},{1, 0},{1, 0},{0, },{2, 11},{6, UIName},{1, 0},{1, 0},{39, RPC-16-0U6E-L4EG-ENH1-J3KF-SVEL-0TX4-C0},{2, 11},{11, VersionGUID},{1, 0},{1, 0},{9, RPCSchema},{2, 11},{9, assettype},{1, 0},{1, 0},{11, RPCGeometry},{2, 11},{11, description},{1, 0},{1, 0},{0, },{2, 11},{9, localname},{1, 0},{1, 0},{3, RPC},{2, 11},{9, localtype},{1, 0},{1, 0},{3, RPC},{1, 4},{8, revision},{1, 0},{1, 0},{1, 1},{2, 11},{9, thumbnail},{1, 0},{1, 0},{0, },{1, 4},{7, version},{1, 0},{1, 0},{1, 1},{1, 2},{20, RPC_Cast Reflections},{1, 0},{1, 0},{1, 0},{1, 4},{16, RPC_Transparency},{1, 0},{1, 0},{2, 18},{1, 4},{11, RPC_Tinting},{1, 0},{1, 0},{2, 50},{1, 2},{15, RPC_Use Tinting},{1, 0},{1, 0},{1, 0},{1, 2},{17, RPC_License Plate},{1, 0},{1, 0},{1, 0},{2, 11},{25, RPC_License Plate Texture},{1, 0},{1, 0},{64, __RPC:/object data/textures/car/plate/textures/default/rgb/0/0/0},{2, 11},{27, RPC_i_License Plate Texture},{1, 0},{1, 0},{0, },{1, 2},{16, RPC_Custom Plate},{1, 0},{1, 0},{1, 0},{2, 11},{27, RPC_License Plate File Name},{1, 0},{1, 0},{0, },{21, assetlibrary_base.fbx},{1, 5},
Pset_BuildingElementProxyCommon - Reference: RPC Coccinelle
Autre - Catégorie: Environnement; Famille: RPC Coccinelle: RPC Coccinelle; Famille et type: RPC Coccinelle: RPC Coccinelle; ID du type: RPC Coccinelle: RPC Coccinelle; Type: RPC Coccinelle: RPC Coccinelle
Contraintes - Niveau: Niveau: RDC; Se déplace avec les éléments voisins: no; Décalage: -0.1 m; Hôte: Niveau : RDC
Phase de construction - Phase de création: Nouvelle construction

# IfcBuildingElementProxy: RPC Ordinateur portable, RPC Ordinateur portable:RPC Ordinateur portable:538196
In: 13
Type - Autre(Type) - Catégorie: Environnement; Nom de la famille: RPC Ordinateur portable
Type - Cotes(Type) - Hauteur: 0 m
Type - Données d'identification(Type) - Apparence de rendu: RPC-16-N04H-AQSP-D1N4-43SU-6GKQ-C3KU-1C; Nom du type: RPC Ordinateur portable; Propriétés de l'apparence de rendu: {2, 15},{39, RPC-16-N04H-AQSP-D1N4-43SU-6GKQ-C3KU-1C},{1, 0},{1, 0},{2, 16},{1, 8},{5, Color},{1, 0},{1, 0},{3, 0.8},{3, 0.8},{3, 0.8},{1, 8},{7, BBoxMin},{1, 0},{1, 0},{1, 0},{1, 0},{1, 0},{1, 8},{7, BBoxMax},{1, 0},{1, 0},{1, 0},{1, 0},{1, 0},{2, 11},{9, RPCTypeId},{1, 0},{1, 0},{39, RPC-16-N04H-AQSP-D1N4-43SU-6GKQ-C3KU-1C},{1, 6},{14, RPCPlantHeight},{1, 0},{1, 0},{7, 2.28517},{2, 11},{7, keyword},{1, 0},{1, 0},{33, :RPCs:Office Clutter:Geometry:RPC},{2, 11},{8, category},{1, 0},{1, 0},{14, Office Clutter},{2, 11},{12, LocalizedUID},{1, 0},{1, 0},{17, Notebook Computer},{2, 14},{6, Height},{1, 0},{1, 0},{7, 2.28517},{1, 2},{16, Cast Reflections},{1, 0},{1, 0},{1, 0},{1, 4},{4, Open},{1, 0},{1, 0},{4, -106},{1, 2},{5, Power},{1, 0},{1, 0},{1, 1},{2, 11},{14, Screen Preview},{1, 0},{1, 0},{70, __RPC:/object data/textures/object/Top/TopScreen/textures/on/rgb/0/0/0},{2, 11},{16, i_Screen Preview},{1, 0},{1, 0},{0, },{1, 2},{13, Custom Screen},{1, 0},{1, 0},{1, 0},{2, 11},{16, Screen File Name},{1, 0},{1, 0},{0, },{21, assetlibrary_base.fbx},{1, 5},
Pset_BuildingElementProxyCommon - Reference: RPC Ordinateur portable
Autre - Catégorie: Environnement; Famille: RPC Ordinateur portable: RPC Ordinateur portable; Famille et type: RPC Ordinateur portable: RPC Ordinateur portable; ID du type: RPC Ordinateur portable: RPC Ordinateur portable; Type: RPC Ordinateur portable: RPC Ordinateur portable
Contraintes - Niveau: Niveau: RDC; Se déplace avec les éléments voisins: no; Décalage: 0.37 m; Hôte: Sol : S5 Plancher flottant habitable
Phase de construction - Phase de création: Nouvelle construction

# IfcColumn: 200 mm x 400 mm (2)
In: 1 Mur de soubassement
Type - ElementType: 200 mm x 400 mm; PredefinedType: COLUMN
Type - Autre(Type) - Catégorie: Poteaux porteurs; Nom de la famille: Poteau béton - Rectangulaire
Type - Cotes(Type) - b: 0.2 m; h: 0.4 m
Type - Données d'identification(Type) - Nom du type: 200 mm x 400 mm
Type - Structure(Type) - Forme de coupe: 0
Material: Maçonnerie - Béton coulé sur place
BaseQuantities - GrossVolume: 0.2624 m3
Pset_ColumnCommon - LoadBearing: yes; IsExternal: no; Slope: 0 deg; Reference: 200 mm x 400 mm
Autre - Catégorie: Poteaux porteurs; Famille: Poteau béton - Rectangulaire: 200 mm x 400 mm; Famille et type: Poteau béton - Rectangulaire: 200 mm x 400 mm; ID du type: Poteau béton - Rectangulaire: 200 mm x 400 mm; Type: Poteau béton - Rectangulaire: 200 mm x 400 mm
Contraintes - Décalage inférieur: 0 m; Limite de pièce: yes; Décalage supérieur: -0.4 m; Niveau: Niveau: 1 Mur de soubassement; Niveau de base: Niveau: 1 Mur de soubassement; Niveau supérieur: Niveau: 1er ETAGE; Se déplace avec les quadrillages: yes; Style de poteau: Vertical
Cotes - Longueur: 3.6 m; Surface: 2.128 m2; Volume: 0.2624 m3
Matériaux et finitions - Matériau structurel: Maçonnerie - Béton coulé sur place
Phase de construction - Phase de création: Nouvelle construction
Structure - Activer le modèle analytique: yes; Enrobage d'armature - Autres faces: Paramètres de l'enrobage d'armature: Enrobage d'armature 1; Enrobage d'armature - Face inférieure: Paramètres de l'enrobage d'armature: Enrobage d'armature 1
Name (Poteau béton - Rectangulaire:200 mm x 400 mm:...)
314299
315225

# IfcCovering: Plafond composé:Plafond ba13 (2)
In: RDC Faux Plafond
PredefinedType: CEILING; Material: Plâtre 0.015 m
Pset_CoveringCommon - Reference: Plafond ba13; TotalThickness: 0.015 m
Autre - Catégorie: Plafonds; Famille: Plafond composé: Plafond ba13; Famille et type: Plafond composé: Plafond ba13; ID du type: Plafond composé: Plafond ba13; Type: Plafond composé: Plafond ba13
Contraintes - Limite de pièce: yes; Décalage par rapport au niveau: 0 m; Niveau: Niveau: RDC Faux Plafond
Phase de construction - Phase de création: Nouvelle construction
Autre(Type) - Catégorie: Plafonds; Nom de la famille: Plafond composé
Construction(Type) - Epaisseur: 0.015 m
Données d'identification(Type) - Nom du type: Plafond ba13
Graphismes(Type) - Couleur vue détail faible: 0
Propriétés analytiques(Type) - Rugosité: 3; Coefficient d'absorbance: 0.7
Name (Plafond composé:Plafond ba13:...) | GrossCeilingArea (m2) = Surface (m2) | Périmètre (m) | Volume (m3)
323722 | 50.9183 | 74.96 | 0.763774
328247 | 63.4209 | 76.6206 | 0.951313

# IfcCurtainWall: Mur-rideau:Simple panneau, Mur-rideau:Simple panneau:298383
In: RDC
Type - Autre(Type) - Catégorie: Murs; Nom de la famille: Mur-rideau
Type - Construction(Type) - Fonction: Extérieur; Condition de jonction: Bord et quadrillage vertical continu; Encastrement automatique: yes; Panneau de mur-rideau: Panneau système: Vitré
Type - Données d'identification(Type) - Nom du type: Simple panneau
Type - Quadrillage horizontal(Type) - Espacement: 2 m; Présentation: Aucun; Régler pour la taille du meneau: yes
Type - Quadrillage vertical(Type) - Présentation: Aucun; Régler pour la taille du meneau: yes; Espacement: 1 m
Pset_CurtainWallCommon - IsExternal: yes; Reference: Simple panneau
Nomenclature de mur - Famille: Mur-rideau: Simple panneau; Famille et type: Mur-rideau: Simple panneau; Longueur: 7.73 m; Surface: 37 m2; Commentaires: porteur
Relevé de matériaux de mur détaillé - Famille et type: Mur-rideau: Simple panneau; sets with these values: 2
Autre - Catégorie: Murs; Famille: Mur-rideau: Simple panneau; Famille et type: Mur-rideau: Simple panneau; ID du type: Mur-rideau: Simple panneau; Type: Mur-rideau: Simple panneau
Contraintes - Décalage inférieur: 0 m; Contrainte inférieure: Niveau: RDC; Décalage supérieur: 0 m; Lié au volume: no; Limite de pièce: yes; Partie inférieure attachée: no; Partie supérieure attachée: no; Hauteur non contrainte: 5 m
Cotes - Longueur: 7.73 m; Surface: 37 m2
Données d'identification - Commentaires: porteur
Phase de construction - Phase de création: Nouvelle construction
Quadrillage horizontal - Angle: 0 deg; Décaler: 0 m; Justification: Début; Nombre: 4; sets with these values: 2
Structure - Activer le modèle analytique: no; Structure: no; Utilisation structurelle: Non porteur

# IfcCurtainWall: Mur-rideau:Simple panneau 2 (2)
In: RDC
Type - Autre(Type) - Catégorie: Murs; Nom de la famille: Mur-rideau
Type - Construction(Type) - Fonction: Intérieur; Condition de jonction: Bord et quadrillage vertical continu; Encastrement automatique: yes; Panneau de mur-rideau: Panneau système: Vitré
Type - Données d'identification(Type) - Nom du type: Simple panneau 2
Type - Quadrillage horizontal(Type) - Présentation: Aucun; Régler pour la taille du meneau: yes; Espacement: 2 m
Type - Quadrillage vertical(Type) - Présentation: Aucun; Régler pour la taille du meneau: yes; Espacement: 1 m
Pset_CurtainWallCommon - IsExternal: no; Reference: Simple panneau 2
Relevé de matériaux de mur détaillé - Famille et type: Mur-rideau: Simple panneau 2; sets with these values: 2
Autre - Catégorie: Murs; Famille: Mur-rideau: Simple panneau 2; Famille et type: Mur-rideau: Simple panneau 2; ID du type: Mur-rideau: Simple panneau 2; Type: Mur-rideau: Simple panneau 2
Contraintes - Décalage inférieur: 0 m; Contrainte inférieure: Niveau: RDC; Décalage supérieur: 0 m; Lié au volume: no; Limite de pièce: yes; Partie inférieure attachée: no; Partie supérieure attachée: no; Contrainte supérieure: Niveau: 1er ETAGE; Hauteur non contrainte: 3 m
Cotes - Longueur: 2.34 m; Surface: 6 m2
Phase de construction - Phase de création: Nouvelle construction
Quadrillage horizontal - Angle: 0 deg; Justification: Début; Nombre: 4; Décaler: 0.1 m
Quadrillage vertical - Angle: 0 deg; Décaler: 0 m; Justification: Début; Nombre: 4
Structure - Activer le modèle analytique: no; Structure: no; Utilisation structurelle: Non porteur
Name (Mur-rideau:Simple panneau 2:...)
360755
363813

# IfcDoor: 3m x 2m, Garage basculante:3m x 2m:293000
In: RDC
Type - OperationType: ROLLINGUP; ParameterTakesPrecedence: no; Sizeable: no; Material: Peinture - Grise
Type - Garage basculante:3m x 2m:293000 - PanelOperation: ROLLINGUP
Type - Autre(Type) - Catégorie: Portes; Nom de la famille: Garage basculante
Type - Construction(Type) - Fonction: Extérieur; Fermeture du mur: Par hôte
Type - Cotes(Type) - Hauteur: 2 m; Hauteur de la poignée: 0.5 m; Largeur: 2.4 m; Largeur du cadre: 0.06 m
Type - Données d'identification(Type) - Marque de type: 32; Nom du type: 3m x 2m
Type - Matériaux et finitions(Type) - Cadre: Peinture - Grise; Panneau: Peinture - Grise; Poignée: Plastique - Noir
Type - Propriétés analytiques(Type) - Coefficient d'apport thermique solaire: 0; Transmission de la lumière visible: 0; Coefficient de transfert de chaleur (U): 3.7021; Construction analytique: Métal; Résistance thermique (R): 0.270117
OverallHeight: 2.43 m; OverallWidth: 2.015 m
Pset_DoorCommon - IsExternal: yes; Reference: 3m x 2m; ThermalTransmittance: 3.7021 kg/K/s3
Nomenclature des portes - Visible dans les nomenclatures: yes; Famille et type: Garage basculante: 3m x 2m; Largeur: 2.4 m; Hauteur: 2 m; Niveau: Niveau: RDC
BaseQuantities - Height: 2 m; Width: 2.4 m; Area: 4.8 m2
Autre - Catégorie: Portes; ID hôte: Mur de base: Ext. Crépis 2 + BBMC 20; Famille: Garage basculante: 3m x 2m; Famille et type: Garage basculante: 3m x 2m; Hauteur sous linteau: 2 m; ID du type: Garage basculante: 3m x 2m; Type: Garage basculante: 3m x 2m
Contraintes - Hauteur de l'appui: 0 m; Niveau: Niveau: RDC
Cotes - Surface: 5.6962 m2; Volume: 0.21156 m3
Données d'identification - Visible dans les nomenclatures: yes; Identifiant: 15
Phase de construction - Phase de création: Nouvelle construction

# IfcDoor: Double vitrée, Double vitrée:Double vitrée:300905
In: RDC
Type - OperationType: DOUBLE_DOOR_SINGLE_SWING; ParameterTakesPrecedence: no; Sizeable: no; Material: Porte - Cadre, PVC - Blanc, Verre
Type - Double vitrée:Double vitrée:300905 - PanelOperation: SWINGING
Type - Autre(Type) - Catégorie: Portes; Nom de la famille: Double vitrée
Type - Construction(Type) - Fonction: Extérieur
Type - Contraintes(Type) - Pos. Panneau (Auto): 0.025 m; Pos. Poignée: 0.05 m; Sys: 0 m
Type - Cotes(Type) - Déc. Bord: 0.01 m; Epaisseur: 0.05 m; Hauteur de la poignée: 1 m; Largeur du cadre: 0.05 m; Largeur du cadre_2: 0.1 m; Prof. Dormants: 0.07 m
Type - Données d'identification(Type) - Nom du type: Double vitrée
Type - Matériaux et finitions(Type) - Dormants: Porte - Cadre; Panneau: PVC - Blanc; Poignée: Porte - Poignée
Type - Propriétés analytiques(Type) - Coefficient d'apport thermique solaire: 0; Transmission de la lumière visible: 0; Coefficient de transfert de chaleur (U): 3.7021; Construction analytique: Métal; Résistance thermique (R): 0.270117
OverallHeight: 2.12 m; OverallWidth: 2.40667 m
Autre - Catégorie: Portes; ID hôte: Mur-rideau: Simple panneau; Famille: Double vitrée: Double vitrée; Famille et type: Double vitrée: Double vitrée; ID du type: Double vitrée: Double vitrée; Type: Double vitrée: Double vitrée
Contraintes - Niveau: Niveau: RDC
Cotes - Hauteur: 2.12 m; Largeur: 2.40667 m; Surface: 5.10213 m2; Volume: 0.119035 m3
Phase de construction - Phase de création: Nouvelle construction
Pset_DoorCommon - IsExternal: yes; Reference: Double vitrée; ThermalTransmittance: 3.7021 kg/K/s3
Nomenclature des portes - Famille et type: Double vitrée: Double vitrée; Largeur: 2.40667 m; Hauteur: 2.12 m; Niveau: Niveau: RDC

# IfcDoor: Lisse - 0.90 m x 2.15 m, Ext. Simple:Lisse - 0.90 m x 2.15 m:438744
In: RDC
Type - OperationType: SINGLE_SWING_RIGHT; ParameterTakesPrecedence: no; Sizeable: no; Material: PVC - Blanc
Type - Ext. Simple:Lisse - 0.90 m x 2.15 m:438744 - PanelOperation: SWINGING
Type - Autre(Type) - Catégorie: Portes; Nom de la famille: Ext. Simple
Type - Construction(Type) - Fonction: Extérieur; Fermeture du mur: Par hôte
Type - Cotes(Type) - Epaisseur: 0.05 m; Epaisseur d'isolation: 0.1 m; Hauteur: 2.15 m; Largeur: 0.9 m
Type - Données d'identification(Type) - Marque de type: 39; Nom du type: Lisse - 0.90 m x 2.15 m
Type - Graphismes(Type) - Type de panneau: Panneau plein
Type - Matériaux et finitions(Type) - Cadre: PVC - Blanc; Panneau: PVC - Blanc; Poignée: PVC - Blanc
Type - Propriétés analytiques(Type) - Coefficient d'apport thermique solaire: 0.86; Coefficient de transfert de chaleur (U): 5.5617; Construction analytique: Grandes fenêtres à vitrage simple; Résistance thermique (R): 0.179801; Transmission de la lumière visible: 0.9
OverallHeight: 2.2 m; OverallWidth: 1 m
Pset_DoorCommon - IsExternal: yes; Reference: Lisse - 0.90 m x 2.15 m; ThermalTransmittance: 5.5617 kg/K/s3
Nomenclature des portes - Famille et type: Ext. Simple: Lisse - 0.90 m x 2.15 m; Largeur: 0.9 m; Hauteur: 2.15 m; Niveau: Niveau: RDC
BaseQuantities - Height: 2.15 m; Width: 0.9 m; Area: 1.935 m2
Autre - Catégorie: Portes; ID hôte: Mur de base: M7 Ext. Crépis 2 + BBMC 20 + Isolant 11; Famille: Ext. Simple: Lisse - 0.90 m x 2.15 m; Famille et type: Ext. Simple: Lisse - 0.90 m x 2.15 m; Hauteur sous linteau: 2.15 m; ID du type: Ext. Simple: Lisse - 0.90 m x 2.15 m; Type: Ext. Simple: Lisse - 0.90 m x 2.15 m
Contraintes - Hauteur de l'appui: 0 m; Niveau: Niveau: RDC
Cotes - Surface: 2.96758 m2; Volume: 0.0950052 m3
Données d'identification - Identifiant: 17
Graphismes - Angle d'ouverture 2D fixe: yes; Angle d'ouverture 3D: 20 deg
Phase de construction - Phase de création: Nouvelle construction

# IfcDoor: Ouverture en rectangle (2)
In: RDC
Type - ParameterTakesPrecedence: no; Sizeable: no; Material: Bois - Chêne
Type - Autre(Type) - Catégorie: Portes; Nom de la famille: Ouverture en rectangle
Type - Construction(Type) - Fonction: Intérieur; Fermeture du mur: Aucun
Type - Cotes(Type) - Hauteur: 2.1 m; Largeur: 1 m; Retour: 0.05 m
Type - Données d'identification(Type) - Marque de type: 29; Nom du type: Ouverture en rectangle
Type - Matériaux et finitions(Type) - Cadre: Bois - Chêne
Type - Propriétés analytiques(Type) - Construction analytique: <Aucun>
OverallHeight: 2.1 m; OverallWidth: 1 m
Pset_DoorCommon - IsExternal: no; Reference: Ouverture en rectangle
Nomenclature des portes - Famille et type: Ouverture en rectangle: Ouverture en rectangle; Largeur: 1 m; Hauteur: 2.1 m; Niveau: Niveau: RDC
BaseQuantities - Height: 2.1 m; Width: 1 m; Area: 2.1 m2
Autre - Catégorie: Portes; Famille: Ouverture en rectangle: Ouverture en rectangle; Famille et type: Ouverture en rectangle: Ouverture en rectangle; Hauteur sous linteau: 2.1 m; ID du type: Ouverture en rectangle: Ouverture en rectangle; Type: Ouverture en rectangle: Ouverture en rectangle
Contraintes - Niveau: Niveau: RDC; Hauteur de l'appui: 0 m
Graphismes - Avec huisserie: yes
Phase de construction - Phase de création: Nouvelle construction
Name (Ouverture en rectangle:Ouverture en rectangle:...) | ID hôte | Surface (m2) | Volume (m3) | Identifiant
275426 | Mur de base: M7 Ext. Crépis 2 + BBMC 20 + Isolant 11 | 1.9162 | 0.03612 | 13
275736 | Mur de base: M8 Ext. Bois 2 + Isolant 12 + BBMC 20 + vide 1 + ba13 | 2.0198 | 0.038184 | 14

# IfcDoor: PP (0.73m x 2.04m) (4)
In: RDC
Type - OperationType: SINGLE_SWING_LEFT; ParameterTakesPrecedence: no; Sizeable: no; Material: Bois - Panneau de porte, Bois - Cadre de porte
Type - Autre(Type) - Catégorie: Portes; Nom de la famille: Int. Simple
Type - Construction(Type) - Fonction: Intérieur; Fermeture du mur: Par hôte
Type - Cotes(Type) - Epaisseur: 0.04 m; Hauteur: 2.04 m; Largeur: 0.73 m
Type - Données d'identification(Type) - Marque de type: 26; Nom du type: PP (0.73m x 2.04m)
Type - Matériaux et finitions(Type) - Ajustement: Bois - Cadre de porte; Cadre: Bois - Cadre de porte; Panneau: Bois - Panneau de porte; Poignée: Finition Peinture - Blanc satiné
Type - Propriétés analytiques(Type) - Coefficient d'apport thermique solaire: 0; Coefficient de transfert de chaleur (U): 3.7021; Construction analytique: Métal; Résistance thermique (R): 0.270117; Transmission de la lumière visible: 0
Type - Int. Simple:PP (0.73m x 2.04m):273407 - PanelOperation: SWINGING
OverallHeight: 2.075 m; OverallWidth: 0.8 m
Pset_DoorCommon - IsExternal: no; Reference: PP (0.73m x 2.04m); ThermalTransmittance: 3.7021 kg/K/s3
Nomenclature des portes - Famille et type: Int. Simple: PP (0.73m x 2.04m); Largeur: 0.73 m; Hauteur: 2.04 m; Niveau: Niveau: RDC
BaseQuantities - Height: 2.04 m; Width: 0.73 m; Area: 1.4892 m2
Autre - Catégorie: Portes; Famille: Int. Simple: PP (0.73m x 2.04m); Famille et type: Int. Simple: PP (0.73m x 2.04m); ID du type: Int. Simple: PP (0.73m x 2.04m); ID hôte: Mur de base: Générique - Int. 70 mm; Type: Int. Simple: PP (0.73m x 2.04m); Hauteur sous linteau: 2.04 m
Contraintes - Niveau: Niveau: RDC; Hauteur de l'appui: 0 m
Cotes - Surface: 2.11485 m2; Volume: 0.071524 m3
Graphismes - Angle d'ouverture 2D fixe: yes; Angle d'ouverture 3D: 0 deg
Phase de construction - Phase de création: Nouvelle construction
Name (Int. Simple:PP (0.73m x 2.04m):...) | Identifiant
273407 | 6
273482 | 7
273553 | 9
273819 | 12

# IfcDoor: PP (0.73m x 2.04m) (4)
In: RDC
Type - OperationType: SINGLE_SWING_RIGHT; ParameterTakesPrecedence: no; Sizeable: no; Material: Bois - Panneau de porte, Bois - Cadre de porte
Type - Int. Simple:PP (0.73m x 2.04m):271522 - PanelOperation: SWINGING
Type - Autre(Type) - Catégorie: Portes; Nom de la famille: Int. Simple
Type - Construction(Type) - Fonction: Intérieur; Fermeture du mur: Par hôte
Type - Cotes(Type) - Epaisseur: 0.04 m; Hauteur: 2.04 m; Largeur: 0.73 m
Type - Données d'identification(Type) - Marque de type: 26; Nom du type: PP (0.73m x 2.04m)
Type - Matériaux et finitions(Type) - Ajustement: Bois - Cadre de porte; Cadre: Bois - Cadre de porte; Panneau: Bois - Panneau de porte; Poignée: Finition Peinture - Blanc satiné
Type - Propriétés analytiques(Type) - Coefficient d'apport thermique solaire: 0; Coefficient de transfert de chaleur (U): 3.7021; Construction analytique: Métal; Résistance thermique (R): 0.270117; Transmission de la lumière visible: 0
OverallHeight: 2.075 m; OverallWidth: 0.8 m
Pset_DoorCommon - IsExternal: no; Reference: PP (0.73m x 2.04m); ThermalTransmittance: 3.7021 kg/K/s3
Nomenclature des portes - Famille et type: Int. Simple: PP (0.73m x 2.04m); Largeur: 0.73 m; Hauteur: 2.04 m; Niveau: Niveau: RDC
BaseQuantities - Height: 2.04 m; Width: 0.73 m; Area: 1.4892 m2
Autre - Catégorie: Portes; Famille: Int. Simple: PP (0.73m x 2.04m); Famille et type: Int. Simple: PP (0.73m x 2.04m); Hauteur sous linteau: 2.04 m; ID du type: Int. Simple: PP (0.73m x 2.04m); ID hôte: Mur de base: Générique - Int. 70 mm; Type: Int. Simple: PP (0.73m x 2.04m)
Contraintes - Hauteur de l'appui: 0 m; Niveau: Niveau: RDC
Cotes - Surface: 2.11485 m2; Volume: 0.071524 m3
Graphismes - Angle d'ouverture 2D fixe: yes; Angle d'ouverture 3D: 0 deg
Phase de construction - Phase de création: Nouvelle construction
Name (Int. Simple:PP (0.73m x 2.04m):...) | Identifiant
271522 | 1 | Nomenclature des portes - Visible dans les nomenclatures: yes; Données d'identification - Visible dans les nomenclatures: yes
273523 | 8
273653 | 10
273705 | 11

# IfcDoor: PV Triangulaire (0.90 m x 2.15 m), Entrée (avec angle d'ouverture):PV Triangulaire (0.90 m x 2.15 m):422585
In: RDC
Type - OperationType: SINGLE_SWING_LEFT; ParameterTakesPrecedence: no; Sizeable: no; Material: Porte d'entrée - Panneau, Verre, Porte d'entrée - Cadre
Type - Entrée (avec angle d'ouverture):PV Triangulaire (0.90 m x 2.15 m):422585 - PanelOperation: SWINGING
Type - Autre(Type) - Catégorie: Portes; Nom de la famille: Entrée (avec angle d'ouverture)
Type - Construction(Type) - Fonction: Extérieur; Fermeture du mur: Extérieur
Type - Cotes(Type) - Epaisseur: 0.05 m; Epaisseur d'isolation: 0.1 m; Hauteur: 2.15 m; Largeur: 0.9 m
Type - Données d'identification(Type) - Marque de type: 34; Nom du type: PV Triangulaire (0.90 m x 2.15 m)
Type - Graphismes(Type) - Type de panneau: Panneau vitrage triangulaire
Type - Matériaux et finitions(Type) - Barreaux: Peinture - Noir; Cadre: Porte d'entrée - Cadre; Panneau: Porte d'entrée - Panneau; Poignée: Porte d'entrée - Poignée
Type - Propriétés analytiques(Type) - Coefficient d'apport thermique solaire: 0.86; Coefficient de transfert de chaleur (U): 5.5617; Construction analytique: Grandes fenêtres à vitrage simple; Résistance thermique (R): 0.179801; Transmission de la lumière visible: 0.9
OverallHeight: 2.19 m; OverallWidth: 0.98 m
Pset_DoorCommon - IsExternal: yes; Reference: PV Triangulaire (0.90 m x 2.15 m); ThermalTransmittance: 5.5617 kg/K/s3
Nomenclature des portes - Famille et type: Entrée (avec angle d'ouverture): PV Triangulaire (0.90 m x 2.15 m); Largeur: 0.9 m; Hauteur: 2.15 m; Niveau: Niveau: RDC
BaseQuantities - Height: 2.15 m; Width: 0.9 m; Area: 1.935 m2
Autre - Catégorie: Portes; ID hôte: Mur de base: M7 Ext. Crépis 2 + BBMC 20 + Isolant 11; Famille: Entrée (avec angle d'ouverture): PV Triangulaire (0.90 m x 2.15 m); Famille et type: Entrée (avec angle d'ouverture): PV Triangulaire (0.90 m x 2.15 m); Hauteur sous linteau: 2.15 m; ID du type: Entrée (avec angle d'ouverture): PV Triangulaire (0.90 m x 2.15 m); Type: Entrée (avec angle d'ouverture): PV Triangulaire (0.90 m x 2.15 m)
Contraintes - Niveau: Niveau: RDC; Hauteur de l'appui: 0 m
Cotes - Surface: 3.02036 m2; Volume: 0.0958856 m3
Données d'identification - Identifiant: 16
Phase de construction - Phase de création: Nouvelle construction

# IfcDoor: Placard coulissante - 3 panneaux (3)
In: RDC
Type - OperationType: SLIDING_TO_RIGHT; ParameterTakesPrecedence: no; Sizeable: no; Material: Placard - Profil, Placard - Encadrement, Placard - Porte
Type - Placard coulissante - 3 panneaux:Placard coulissante - 3 panneaux:273082 - PanelOperation: SLIDING
Type - Autre(Type) - Catégorie: Portes; Nom de la famille: Placard coulissante - 3 panneaux
Type - Construction(Type) - Fonction: Intérieur; Fermeture du mur: Aucun
Type - Cotes(Type) - Epaisseur: 0.02 m; Hauteur: 2.1 m; Largeur: 1.8 m; Largeur du cadre: 0.05 m
Type - Données d'identification(Type) - Marque de type: 28; Nom du type: Placard coulissante - 3 panneaux
Type - Graphismes(Type) - Profils: yes
Type - Matériaux et finitions(Type) - Cadre: Placard - Encadrement; Panneau: Placard - Porte; Profil: Placard - Profil
Type - Propriétés analytiques(Type) - Coefficient d'apport thermique solaire: 0; Transmission de la lumière visible: 0; Coefficient de transfert de chaleur (U): 3.7021; Construction analytique: Métal; Résistance thermique (R): 0.270117
OverallHeight: 2.1 m; OverallWidth: 1.8 m
Pset_DoorCommon - IsExternal: no; Reference: Placard coulissante - 3 panneaux; ThermalTransmittance: 3.7021 kg/K/s3
Nomenclature des portes - Famille et type: Placard coulissante - 3 panneaux: Placard coulissante - 3 panneaux; Largeur: 1.8 m; Hauteur: 2.1 m; Niveau: Niveau: RDC
BaseQuantities - Height: 2.1 m; Width: 1.8 m; Area: 3.78 m2
Autre - Catégorie: Portes; ID hôte: Mur de base: Générique - Int. 70 mm; Famille: Placard coulissante - 3 panneaux: Placard coulissante - 3 panneaux; Famille et type: Placard coulissante - 3 panneaux: Placard coulissante - 3 panneaux; Hauteur sous linteau: 2.1 m; ID du type: Placard coulissante - 3 panneaux: Placard coulissante - 3 panneaux; Type: Placard coulissante - 3 panneaux: Placard coulissante - 3 panneaux
Contraintes - Niveau: Niveau: RDC; Hauteur de l'appui: 0 m
Cotes - Surface: 4.154 m2; Volume: 0.0798 m3
Phase de construction - Phase de création: Nouvelle construction
Name (Placard coulissante - 3 panneaux:Placard coulissante - 3 panneaux:...) | Identifiant
273082 | 2
273212 | 4
273299 | 5

# IfcFlowSegment: Gouttière:Gouttière PVC:345603, Gouttière:Gouttière PVC:348524
In: 1er Chainage
Type - ElementType: Gouttière:Gouttière PVC:345603; PredefinedType: GUTTER
Pset_DistributionFlowElementCommon - Reference: Gouttière PVC
Autre - Catégorie: Gouttières; Famille: Gouttière: Gouttière PVC; Famille et type: Gouttière: Gouttière PVC; ID du type: Gouttière: Gouttière PVC; Type: Gouttière: Gouttière PVC
Contraintes - Décalage horizontal du profil: 0 m; Décalage vertical du profil: -0.15 m
Cotes - Longueur: 29.6 m
Phase de construction - Phase de création: Nouvelle construction
Profil - Angle: 0 deg
Autre(Type) - Catégorie: Gouttières; Nom de la famille: Gouttière
Données d'identification(Type) - Nom du type: Gouttière PVC
Matériaux et finitions(Type) - Matériau: Plastique, blanc opaque

# IfcFlowTerminal: 790mm x 500mm, Evier - Classique 2 bacs:790mm x 500mm:498837
In: 21
Material: Plastique - Blanc brillant, Plastique - Ton pierre
Pset_DistributionFlowElementCommon - Reference: 790mm x 500mm
Autre - Catégorie: Appareils sanitaires; Famille: Evier - Classique 2 bacs: 790mm x 500mm; Famille et type: Evier - Classique 2 bacs: 790mm x 500mm; ID du type: Evier - Classique 2 bacs: 790mm x 500mm; Type: Evier - Classique 2 bacs: 790mm x 500mm
Contraintes - Niveau: Niveau: RDC; Se déplace avec les éléments voisins: no; Décalage: 0 m; Hôte: Sol : S5 Plancher flottant habitable
Cotes - Surface: 0.925793 m2; Volume: 0.00491721 m3
Données d'identification - Identifiant: 21
Phase de construction - Phase de création: Nouvelle construction
Autre(Type) - Catégorie: Appareils sanitaires; Nom de la famille: Evier - Classique 2 bacs
Données d'identification(Type) - Nom du type: 790mm x 500mm
Matériaux et finitions(Type) - Matériau: Plastique - Ton pierre; Matériau de robinet: Plastique - Blanc brillant

# IfcFlowTerminal: Baignoire rectangulaire - Mur (2)
Material: Céramique - Blanche
Pset_DistributionFlowElementCommon - Reference: Baignoire rectangulaire - Mur
Autre - ID hôte: Mur de base: M8 Ext. Bois 2 + Isolant 12 + BBMC 20 + vide 1 + ba13; Catégorie: Appareils sanitaires; Famille: Baignoire rectangulaire - Mur: Baignoire rectangulaire - Mur; Famille et type: Baignoire rectangulaire - Mur: Baignoire rectangulaire - Mur; ID du type: Baignoire rectangulaire - Mur: Baignoire rectangulaire - Mur; Type: Baignoire rectangulaire - Mur: Baignoire rectangulaire - Mur
Contraintes - Niveau: Niveau: RDC
Cotes - Surface: 5.17925 m2; Volume: 0.105165 m3
Phase de construction - Phase de création: Nouvelle construction
Autre(Type) - Catégorie: Appareils sanitaires; Nom de la famille: Baignoire rectangulaire - Mur
Cotes(Type) - Hauteur: 0.6 m; Largeur: 1.525 m; Profondeur: 0.762 m
Données d'identification(Type) - Nom du type: Baignoire rectangulaire - Mur
Matériaux et finitions(Type) - Baignoire: Céramique - Blanche
Name (Baignoire rectangulaire - Mur:Baignoire rectangulaire - Mur:...) | In | Identifiant
384437 | 22 | 2
385515 | 9 | 4

# IfcFlowTerminal: Cuvette réservoir (3)
Material: Porcelaine - Lin, Stratifié - Lin, Mat
Pset_DistributionFlowElementCommon - Reference: Cuvette réservoir
Autre - Catégorie: Appareils sanitaires; Famille: Cuvette réservoir: Cuvette réservoir; Famille et type: Cuvette réservoir: Cuvette réservoir; ID du type: Cuvette réservoir: Cuvette réservoir; Type: Cuvette réservoir: Cuvette réservoir
Contraintes - Niveau: Niveau: RDC; Se déplace avec les éléments voisins: no; Décalage: 0 m
Cotes - Surface: 1.88455 m2; Volume: 0.0312525 m3
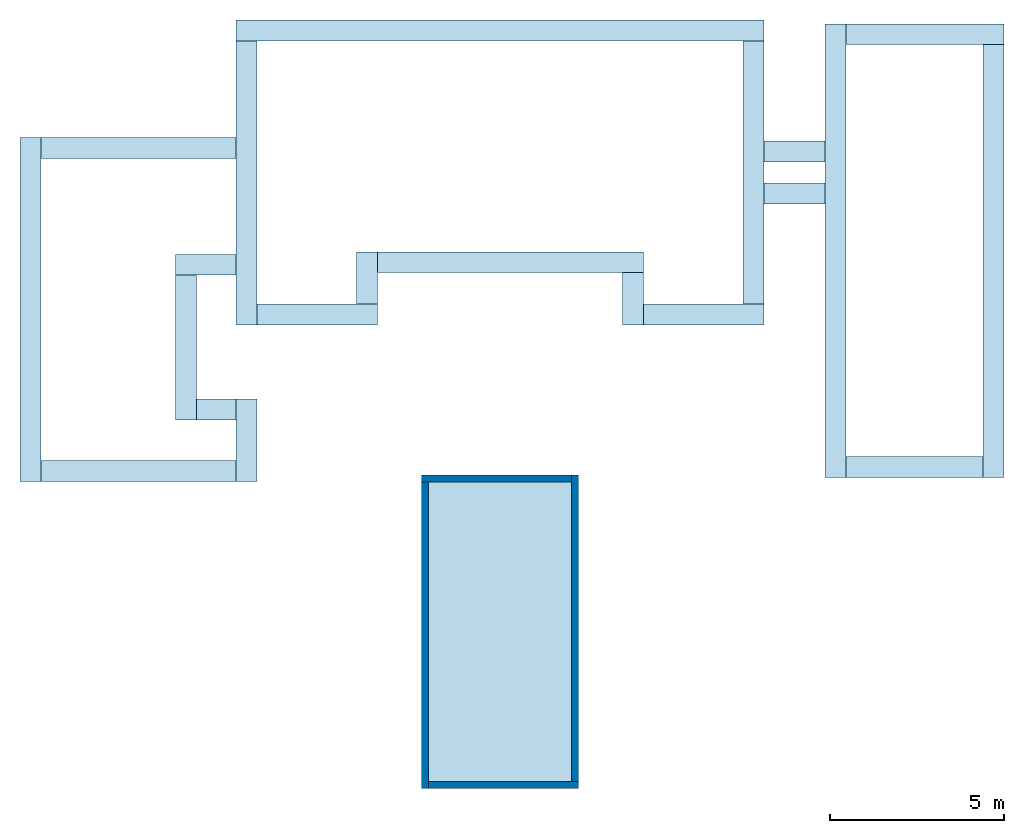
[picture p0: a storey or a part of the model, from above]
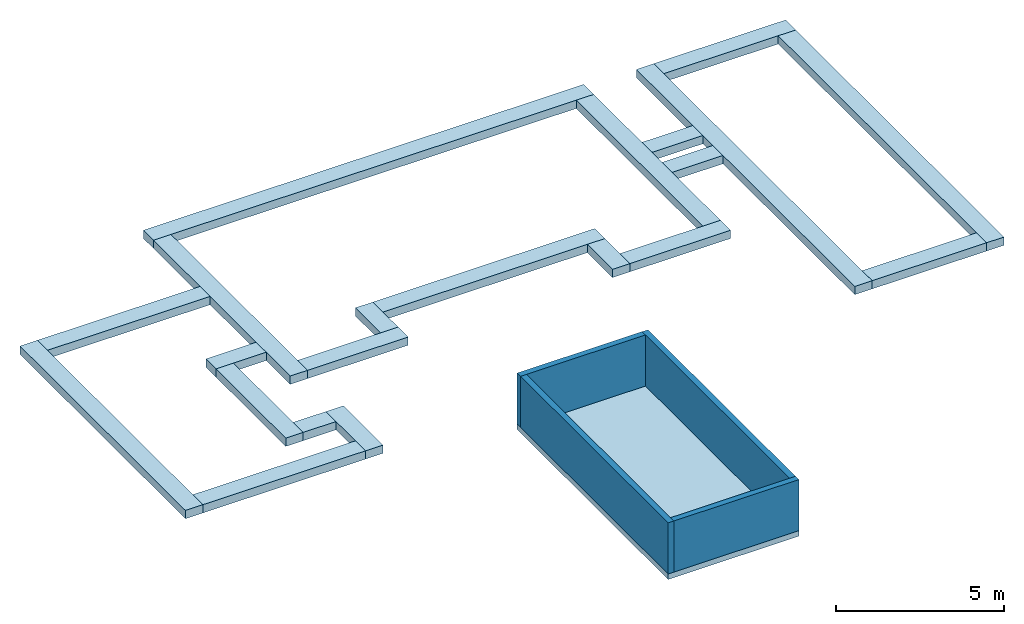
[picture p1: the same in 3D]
Properties of the parts of a building model (IFC2X3), part 2 of 4

# IfcFlowTerminal: Cuvette réservoir (3)
Phase de construction - Phase de création: Nouvelle construction
Autre(Type) - Catégorie: Appareils sanitaires; Nom de la famille: Cuvette réservoir
Données d'identification(Type) - Nom du type: Cuvette réservoir
Matériaux et finitions(Type) - Cuvette: Porcelaine - Lin; Siège: Stratifié - Lin, Mat
Name (Cuvette réservoir:Cuvette réservoir:...) | In | Hôte | Identifiant
442968 | 23 | Sol : Dallage garage | 13
443149 | 22 | Sol : Plancher espace nuit | 14
443848 | 9 | Sol : Plancher espace nuit | 16

# IfcFlowTerminal: Encastrable (4)
Type - Material: Verre - Lampe, Plastique - Blanc
Type - Autre(Type) - Catégorie: Luminaires; Nom de la famille: Spot
Type - Données d'identification(Type) - Nom du type: Encastrable
Type - Photométriques(Type) - Angle de l'inclinaison: 90 deg; Angle du champ à un point sélectionné: 40 deg; Angle du faisceau: 15 deg; Eclairement: 1337.54 lx; Efficacité: 148.542 s3*lm/kg/m2; Facteur de perte de luminosité: 0; Facteur de perte de luminosité totale: 1; Flux lumineux: 950 lm; Intensité initiale: 0; Intensité lumineuse: 12426.2 cd; Puissance: 6.3955 W
Pset_DistributionFlowElementCommon - Reference: Encastrable
Autre - Catégorie: Luminaires; Famille: Spot: Encastrable; Famille et type: Spot: Encastrable; ID du type: Spot: Encastrable; Type: Spot: Encastrable
Contraintes - Niveau: Niveau: RDC; Se déplace avec les éléments voisins: no; Décalage: 0.5334 m; Hôte: Niveau : RDC
Cotes - Surface: 0.0123611 m2; Volume: 0.0000461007 m3
Electricité - Eclairage - Calculer le coefficient d'utilisation: no
Phase de construction - Phase de création: Nouvelle construction
Name (Spot:Encastrable:...) | In | Identifiant
410634 | 9 | 1
410635 | 9 | 2
410842 | 22 | 3
410843 | 22 | 4

# IfcFlowTerminal: Lavabo encastrable (4)
Material: Métal - Chrome poli, Porcelaine - Blanche
Pset_DistributionFlowElementCommon - Reference: Lavabo encastrable
Autre - Catégorie: Appareils sanitaires; Famille: Lavabo encastrable: Lavabo encastrable; Famille et type: Lavabo encastrable: Lavabo encastrable; ID du type: Lavabo encastrable: Lavabo encastrable; Type: Lavabo encastrable: Lavabo encastrable
Contraintes - Niveau: Niveau: RDC; Se déplace avec les éléments voisins: no; Décalage: 0.376043 m; Hôte: Niveau : RDC
Cotes - Surface: 0.278914 m2; Volume: 0.00274814 m3
Phase de construction - Phase de création: Nouvelle construction
Autre(Type) - Catégorie: Appareils sanitaires; Nom de la famille: Lavabo encastrable
Données d'identification(Type) - Nom du type: Lavabo encastrable
Matériaux et finitions(Type) - Matériau - Evier: Porcelaine - Blanche; Matériau - Robinet: Métal - Chrome poli
Name (Lavabo encastrable:Lavabo encastrable:...) | In | Identifiant
410632 | 9 | 9
410633 | 9 | 10
410840 | 22 | 11
410841 | 22 | 12

# IfcFlowTerminal: Lavabo moderne, Lavabo moderne:Lavabo moderne:443967
In: 1
Material: Métal - Chrome poli, Porcelaine - Blanche, Bois - Noyer naturel
Pset_DistributionFlowElementCommon - Reference: Lavabo moderne
Autre - Catégorie: Appareils sanitaires; Famille: Lavabo moderne: Lavabo moderne; Famille et type: Lavabo moderne: Lavabo moderne; ID du type: Lavabo moderne: Lavabo moderne; Type: Lavabo moderne: Lavabo moderne
Contraintes - Niveau: Niveau: RDC; Se déplace avec les éléments voisins: no; Décalage: 0.83 m; Hôte: Sol : Dallage garage
Cotes - Surface: 1.20198 m2; Volume: 0.0434369 m3
Données d'identification - Identifiant: 17
Phase de construction - Phase de création: Nouvelle construction
Autre(Type) - Catégorie: Appareils sanitaires; Nom de la famille: Lavabo moderne
Cotes(Type) - Epaisseur: 0.03 m; Hauteur du robinet: 0.3 m; Longueur: 0.93 m; Profondeur: 0.56 m
Données d'identification(Type) - Nom du type: Lavabo moderne
Matériaux et finitions(Type) - Matériau - Etagère: Bois - Noyer naturel; Matériau - Evier: Porcelaine - Blanche; Matériau - Tuyauterie et robinetterie: Métal - Chrome poli

# IfcFooting: Semelle filante:Soubassement 20 cm/20 cm x 30 cm (21)
In: PIscine
PredefinedType: STRIP_FOOTING; Material: Maçonnerie - Béton
Autre - Catégorie: Fondations; Famille: Semelle filante: Soubassement 20 cm/20 cm x 30 cm; Famille et type: Semelle filante: Soubassement 20 cm/20 cm x 30 cm; ID du type: Semelle filante: Soubassement 20 cm/20 cm x 30 cm; Type: Semelle filante: Soubassement 20 cm/20 cm x 30 cm
Cotes - Elévation à la base: -1.3 m; Elévation en haut: -1 m; Largeur: 0.6 m
Phase de construction - Phase de création: Nouvelle construction
Structure - Activer le modèle analytique: yes; Enrobage d'armature - Autres faces: Paramètres de l'enrobage d'armature: Enrobage d'armature 1; Enrobage d'armature - Face inférieure: Paramètres de l'enrobage d'armature: Enrobage d'armature 1; Enrobage d'armature - Face supérieure: Paramètres de l'enrobage d'armature: Enrobage d'armature 1
Autre(Type) - Catégorie: Fondations; Nom de la famille: Semelle filante
Cotes(Type) - Epaisseur de fondation: 0.3 m; Largeur côté extérieur: 0.2 m; Largeur côté intérieur: 0.2 m; Longueur de l'extension de fin par défaut: 0 m; Ne pas couper aux insertions: no
Données d'identification(Type) - Nom du type: Soubassement 20 cm/20 cm x 30 cm
Matériaux et finitions(Type) - Matériau structurel: Maçonnerie - Béton
Structure(Type) - Utilisation structurelle: Soutènement
Name (Semelle filante:Soubassement 20 cm/20 cm x 30 cm:...) | Longueur (m) | Surface (m2) | Volume (m3)
355191 | 14.76 | 9.096 | 2.7288
355205 | 7.95612 | 4.89367 | 1.4681
355219 | 3.46 | 2.076 | 0.6228
355233 | 1.5 | 0.9 | 0.27
355247 | 7.64 | 4.584 | 1.3752
355261 | 1.5 | 0.9 | 0.27
355275 | 3.46 | 2.076 | 0.6228
355289 | 8.15612 | 4.53367 | 1.3601
355303 | 2.15093 | 1.05056 | 0.315167
355317 | 2.15093 | 1.05056 | 0.315167
355331 | 12.23 | 7.818 | 2.3454
355345 | 4.73907 | 2.72344 | 0.817033
355359 | 12.43 | 7.458 | 2.2374
355373 | 4.53907 | 2.36344 | 0.709033
364382 | 1.73 | 1.038 | 0.3114
515024 | 9.47 | 5.922 | 1.7766
515375 | 1.96 | 1.416 | 0.4248
516066 | 6 | 3.36 | 1.008
516441 | 6 | 3.36 | 1.008
516804 | 4.16 | 2.496 | 0.7488
517102 | 1.53 | 0.678 | 0.2034

# IfcFurnishingElement: 1100 mm, Placard - Porte double unité pour évier:1100 mm:493306
In: 21
Type - ElementType: 1100 mm; Material: Plastique - Noir
Type - Autre(Type) - Catégorie: Meubles de rangement; Nom de la famille: Placard - Porte double unité pour évier
Type - Cotes(Type) - Hauteur: 0.86 m; Hauteur de plinthe: 0.16 m; Largeur: 1.1 m; Profondeur: 0.6 m; Profondeur de plinthe: 0.035 m
Type - Données d'identification(Type) - Nom du type: 1100 mm
Type - Matériaux et finitions(Type) - Matériau de placard: Bois - Mélaminé blanc; Matériau de poignée: Plastique - Noir; Matériau de porte/tiroir: Bois - Mélaminé blanc
Autre - Catégorie: Meubles de rangement; Famille: Placard - Porte double unité pour évier: 1100 mm; Famille et type: Placard - Porte double unité pour évier: 1100 mm; ID du type: Placard - Porte double unité pour évier: 1100 mm; Type: Placard - Porte double unité pour évier: 1100 mm
Contraintes - Niveau: Niveau: RDC; Se déplace avec les éléments voisins: no; Décalage: 0 m; Hôte: Sol : S5 Plancher flottant habitable
Cotes - Surface: 4.5845 m2; Volume: 0.163709 m3
Phase de construction - Phase de création: Nouvelle construction

# IfcFurnishingElement: 1200 mm x 1930 mm x 430 mm BLANC (2)
Type - ElementType: 1200 mm x 1930 mm x 430 mm BLANC; Material: Bois - Mélaminé blanc irisé, Verre - Tablette SdB, Verre - Miroir
Type - Autre(Type) - Catégorie: Mobilier; Nom de la famille: Meuble de salle de bain
Type - Contraintes(Type) - LV1: -0.1 m; LV2: 0.1 m; V1: no; V2: yes
Type - Cotes(Type) - Hauteur: 1.93 m; Hauteur de plinthe: 0.06 m; Hauteur du plan de travail: 0.73 m; Largeur: 1.2 m; Profondeur: 0.43 m
Type - Données d'identification(Type) - Nom du type: 1200 mm x 1930 mm x 430 mm BLANC
Type - Matériaux et finitions(Type) - Finition: Bois - Mélaminé blanc irisé; Panneaux: Bois - Mélaminé blanc irisé; Plan de travail: Bois - Mélaminé blanc irisé
Autre - Catégorie: Mobilier; Famille: Meuble de salle de bain: 1200 mm x 1930 mm x 430 mm BLANC; Famille et type: Meuble de salle de bain: 1200 mm x 1930 mm x 430 mm BLANC; ID du type: Meuble de salle de bain: 1200 mm x 1930 mm x 430 mm BLANC; Type: Meuble de salle de bain: 1200 mm x 1930 mm x 430 mm BLANC
Contraintes - Niveau: Niveau: RDC; Se déplace avec les éléments voisins: no; Décalage: 0 m; Hôte: Sol : Plancher espace nuit
Cotes - Surface: 6.15549 m2; Volume: 0.105258 m3
Phase de construction - Phase de création: Nouvelle construction
Name (Meuble de salle de bain:1200 mm x 1930 mm x 430 mm BLANC:...) | In
410631 | 9
410839 | 22

# IfcFurnishingElement: 1800 x 450 x 420 mm, Meuble TV:1800 x 450 x 420 mm:398640
In: 13
Type - ElementType: 1800 x 450 x 420 mm; Material: Noir - Laqué, Rouge - Laqué
Type - Autre(Type) - Catégorie: Mobilier; Nom de la famille: Meuble TV
Type - Cotes(Type) - Hauteur: 0.42 m; Largeur: 1.4 m; Profondeur: 0.46 m
Type - Données d'identification(Type) - Nom du type: 1800 x 450 x 420 mm; Numéro OmniClass: 23.40.20.00; Titre OmniClass: General Furniture and Specialties
Type - Matériaux et finitions(Type) - Mobilier: Noir - Laqué; Portes: Rouge - Laqué
Autre - Catégorie: Mobilier; Famille: Meuble TV: 1800 x 450 x 420 mm; Famille et type: Meuble TV: 1800 x 450 x 420 mm; ID du type: Meuble TV: 1800 x 450 x 420 mm; Type: Meuble TV: 1800 x 450 x 420 mm
Contraintes - Niveau: Niveau: RDC; Se déplace avec les éléments voisins: no; Décalage: 0 m; Hôte: Sol : S5 Plancher flottant habitable
Cotes - Surface: 2.66535 m2; Volume: 0.0664286 m3
Phase de construction - Phase de création: Nouvelle construction

# IfcFurnishingElement: 1800 x 460 x 1800 mm, Bibliothèque - Type adolescent:1800 x 460 x 1800 mm:397146
In: 13
Type - ElementType: 1800 x 460 x 1800 mm; Material: Noir - Laqué, Rouge - Laqué
Type - Autre(Type) - Catégorie: Mobilier; Nom de la famille: Bibliothèque - Type adolescent
Type - Cotes(Type) - Hauteur: 1.8 m; Largeur: 1.8 m; Profondeur: 0.46 m
Type - Données d'identification(Type) - Nom du type: 1800 x 460 x 1800 mm; Numéro OmniClass: 23.40.20.00; Titre OmniClass: General Furniture and Specialties
Type - Matériaux et finitions(Type) - Mobilier: Noir - Laqué; Portes: Rouge - Laqué
Autre - Catégorie: Mobilier; Famille: Bibliothèque - Type adolescent: 1800 x 460 x 1800 mm; Famille et type: Bibliothèque - Type adolescent: 1800 x 460 x 1800 mm; ID du type: Bibliothèque - Type adolescent: 1800 x 460 x 1800 mm; Type: Bibliothèque - Type adolescent: 1800 x 460 x 1800 mm
Contraintes - Niveau: Niveau: RDC; Se déplace avec les éléments voisins: no; Décalage: 0 m; Hôte: Sol : S5 Plancher flottant habitable
Cotes - Surface: 8.43847 m2; Volume: 0.217223 m3
Phase de construction - Phase de création: Nouvelle construction

# IfcFurnishingElement: 1800mm x 2200mm (2)
Type - ElementType: 1800mm x 2200mm; Material: Textile - Pêche, Textile - Bleu pâle, Plastique - Noir
Type - Autre(Type) - Catégorie: Mobilier; Nom de la famille: Lit - Divan
Type - Cotes(Type) - Largeur: 1.8 m
Type - Données d'identification(Type) - Nom du type: 1800mm x 2200mm
Type - Matériaux et finitions(Type) - Matériau de lit: Textile - Pêche; Pieds: Plastique - Noir
Autre - Catégorie: Mobilier; Famille: Lit - Divan: 1800mm x 2200mm; Famille et type: Lit - Divan: 1800mm x 2200mm; ID du type: Lit - Divan: 1800mm x 2200mm; Type: Lit - Divan: 1800mm x 2200mm
Contraintes - Niveau: Niveau: RDC; Se déplace avec les éléments voisins: no; Décalage: 0 m; Hôte: Sol : Plancher espace nuit
Cotes - Surface: 10.2424 m2; Volume: 1.61162 m3
Matériaux et finitions - Matériau de matelas: Textile - Bleu pâle
Phase de construction - Phase de création: Nouvelle construction
Name (Lit - Divan:1800mm x 2200mm:...) | In
381101 | 2
381307 | 4

# IfcFurnishingElement: 1940 x 500 x 850 mm, Buffet:1940 x 500 x 850 mm:481996
In: 19
Type - ElementType: 1940 x 500 x 850 mm; Material: Noir - Laqué, Rouge - Laqué
Type - Autre(Type) - Catégorie: Mobilier; Nom de la famille: Buffet
Type - Cotes(Type) - Hauteur: 0.85 m; Largeur: 1.94 m; Profondeur: 0.5 m
Type - Données d'identification(Type) - Nom du type: 1940 x 500 x 850 mm; Numéro OmniClass: 23.40.20.00; Titre OmniClass: General Furniture and Specialties
Type - Matériaux et finitions(Type) - Mobilier: Noir - Laqué; Portes: Rouge - Laqué
Autre - Catégorie: Mobilier; Famille: Buffet: 1940 x 500 x 850 mm; Famille et type: Buffet: 1940 x 500 x 850 mm; ID du type: Buffet: 1940 x 500 x 850 mm; Type: Buffet: 1940 x 500 x 850 mm
Contraintes - Niveau: Niveau: RDC; Se déplace avec les éléments voisins: no; Décalage: 0 m; Hôte: Sol : S5 Plancher flottant habitable
Cotes - Surface: 5.911 m2; Volume: 0.141416 m3
Phase de construction - Phase de création: Nouvelle construction

# IfcFurnishingElement: 210 x 44 x 236 cm - Blanc brillant 2, Armoire à deux portes coulissantes:210 x 44 x 236 cm - Blanc brillant 2:440466
In: 12
Type - ElementType: 210 x 44 x 236 cm - Blanc brillant 2; Material: Verre trempé - Blanc, Métal - Alu brossé, Aggloméré - Blanc brillant
Type - Autre(Type) - Catégorie: Mobilier; Nom de la famille: Armoire à deux portes coulissantes
Type - Cotes(Type) - Hauteur: 2.36 m; Largeur: 2.1 m; Profondeur: 0.44 m
Type - Données d'identification(Type) - Nom du type: 210 x 44 x 236 cm - Blanc brillant 2; Numéro OmniClass: 23.40.20.00; Titre OmniClass: General Furniture and Specialties
Type - Matériaux et finitions(Type) - Mobilier: Aggloméré - Blanc brillant; Portes: Verre trempé - Blanc; Profils: Métal - Alu brossé
Autre - Catégorie: Mobilier; Famille: Armoire à deux portes coulissantes: 210 x 44 x 236 cm - Blanc brillant 2; Famille et type: Armoire à deux portes coulissantes: 210 x 44 x 236 cm - Blanc brillant 2; ID du type: Armoire à deux portes coulissantes: 210 x 44 x 236 cm - Blanc brillant 2; Type: Armoire à deux portes coulissantes: 210 x 44 x 236 cm - Blanc brillant 2
Contraintes - Niveau: Niveau: RDC; Se déplace avec les éléments voisins: no; Décalage: 0 m; Hôte: Sol : S5 Plancher flottant habitable
Cotes - Surface: 15.0445 m2; Volume: 0.162016 m3
Phase de construction - Phase de création: Nouvelle construction

# IfcFurnishingElement: 3 emplacements (230 x 92 cm) (2)
In: 13
Type - ElementType: 3 emplacements (230 x 92 cm); Material: Métal - Chrome, Cuir - Bordeaux
Type - Autre(Type) - Catégorie: Mobilier; Nom de la famille: Canapé 3 places - 02
Type - Données d'identification(Type) - Nom du type: 3 emplacements (230 x 92 cm)
Type - Matériaux et finitions(Type) - Pieds: Métal - Chrome
Autre - Catégorie: Mobilier; Famille: Canapé 3 places - 02: 3 emplacements (230 x 92 cm); Famille et type: Canapé 3 places - 02: 3 emplacements (230 x 92 cm); ID du type: Canapé 3 places - 02: 3 emplacements (230 x 92 cm); Type: Canapé 3 places - 02: 3 emplacements (230 x 92 cm)
Contraintes - Niveau: Niveau: RDC; Se déplace avec les éléments voisins: no; Décalage: 0 m; Hôte: Sol : S5 Plancher flottant habitable
Cotes - Surface: 4.45483 m2; Volume: 0.574229 m3
Matériaux et finitions - Canapé: Cuir - Bordeaux
Phase de construction - Phase de création: Nouvelle construction
Name (Canapé 3 places - 02:3 emplacements (230 x 92 cm):...)
395420
395525

# IfcFurnishingElement: 450 mm (4)
In: 21
Type - ElementType: 450 mm; Material: Plastique - Noir
Type - Autre(Type) - Catégorie: Meubles de rangement; Nom de la famille: Placard - Une porte
Type - Cotes(Type) - Hauteur: 0.86 m; Hauteur de plinthe: 0.16 m; Largeur: 0.67 m; Profondeur: 0.45 m; Profondeur de plinthe: 0.035 m
Type - Données d'identification(Type) - Nom du type: 450 mm
Type - Matériaux et finitions(Type) - Matériau de placard: Bois - Mélaminé blanc; Matériau de poignée: Plastique - Noir; Matériau du tiroir: Bois - Mélaminé blanc
Autre - Catégorie: Meubles de rangement; Famille: Placard - Une porte: 450 mm; Famille et type: Placard - Une porte: 450 mm; ID du type: Placard - Une porte: 450 mm; Type: Placard - Une porte: 450 mm
Contraintes - Niveau: Niveau: RDC; Se déplace avec les éléments voisins: no
Cotes - Surface: 2.69727 m2; Volume: 0.0836288 m3
Phase de construction - Phase de création: Nouvelle construction
Name (Placard - Une porte:450 mm:...) | Décalage (m) | Hôte
500196 | -0.895 | Sol : Plan de travail cuisine
501009 | 0.012 | Sol : S5 Plancher flottant habitable
501123 | 0.012 | Sol : S5 Plancher flottant habitable
501124 | 0.012 | Sol : S5 Plancher flottant habitable

# IfcFurnishingElement: 450 mm 3, Placard - Une porte:450 mm 3:501453
In: 21
Type - ElementType: 450 mm 3; Material: Plastique - Noir
Type - Autre(Type) - Catégorie: Meubles de rangement; Nom de la famille: Placard - Une porte
Type - Cotes(Type) - Hauteur: 0.86 m; Hauteur de plinthe: 0.16 m; Largeur: 0.62 m; Profondeur: 0.45 m; Profondeur de plinthe: 0.035 m
Type - Données d'identification(Type) - Nom du type: 450 mm 3
Type - Matériaux et finitions(Type) - Matériau de placard: Bois - Mélaminé blanc; Matériau de poignée: Plastique - Noir; Matériau du tiroir: Bois - Mélaminé blanc
Autre - Catégorie: Meubles de rangement; Famille: Placard - Une porte: 450 mm 3; Famille et type: Placard - Une porte: 450 mm 3; ID du type: Placard - Une porte: 450 mm 3; Type: Placard - Une porte: 450 mm 3
Contraintes - Niveau: Niveau: RDC; Se déplace avec les éléments voisins: no; Décalage: 0.012 m; Hôte: Sol : S5 Plancher flottant habitable
Cotes - Surface: 2.54229 m2; Volume: 0.0781627 m3
Phase de construction - Phase de création: Nouvelle construction

# IfcFurnishingElement: 590 mm, Placard mural haut-Porte double vitrée:590 mm:491408
In: 21
Type - ElementType: 590 mm; Material: Plastique - Noir
Type - Autre(Type) - Catégorie: Meubles de rangement; Hauteur de l'élévation: 2 m; Nom de la famille: Placard mural haut-Porte double vitrée
Type - Cotes(Type) - Hauteur: 0.6 m; Largeur: 0.59 m; Profondeur: 0.3 m
Type - Données d'identification(Type) - Nom du type: 590 mm
Type - Matériaux et finitions(Type) - Panneaux: Verre; Placard: Bois - Mélaminé blanc; Poignée: Plastique - Noir; Porte/tiroir: Bois - Mélaminé blanc
Autre - ID hôte: Mur de base: Générique - Int. 70 mm; Catégorie: Meubles de rangement; Famille: Placard mural haut-Porte double vitrée: 590 mm; Famille et type: Placard mural haut-Porte double vitrée: 590 mm; ID du type: Placard mural haut-Porte double vitrée: 590 mm; Type: Placard mural haut-Porte double vitrée: 590 mm
Contraintes - Niveau: Niveau: RDC; Elévation: 1.4 m
Cotes - Surface: 1.48573 m2; Volume: 0.0235439 m3
Phase de construction - Phase de création: Nouvelle construction

# IfcFurnishingElement: 670 mm (3)
In: 21
Type - ElementType: 670 mm; Material: Plastique - Noir
Type - Autre(Type) - Catégorie: Meubles de rangement; Hauteur de l'élévation: 2 m; Nom de la famille: Placard mural haut-Porte double vitrée
Type - Cotes(Type) - Hauteur: 0.6 m; Largeur: 0.67 m; Profondeur: 0.3 m
Type - Données d'identification(Type) - Nom du type: 670 mm
Type - Matériaux et finitions(Type) - Panneaux: Verre; Placard: Bois - Mélaminé blanc; Poignée: Plastique - Noir; Porte/tiroir: Bois - Mélaminé blanc
Autre - ID hôte: Mur de base: Générique - Int. 70 mm; Catégorie: Meubles de rangement; Famille: Placard mural haut-Porte double vitrée: 670 mm; Famille et type: Placard mural haut-Porte double vitrée: 670 mm; ID du type: Placard mural haut-Porte double vitrée: 670 mm; Type: Placard mural haut-Porte double vitrée: 670 mm
Contraintes - Niveau: Niveau: RDC; Elévation: 1.4 m
Cotes - Surface: 1.63379 m2; Volume: 0.0257291 m3
Phase de construction - Phase de création: Nouvelle construction
Name (Placard mural haut-Porte double vitrée:670 mm:...)
482780
482908
482970

# IfcFurnishingElement: 670 mm (3)
In: 21
Type - ElementType: 670 mm; Material: Plastique - Noir
Type - Autre(Type) - Catégorie: Meubles de rangement; Nom de la famille: Placard - 4 tiroirs
Type - Cotes(Type) - Hauteur: 0.86 m; Hauteur de plinthe: 0.16 m; Largeur: 0.67 m; Profondeur: 0.6 m; Profondeur de plinthe: 0.035 m
Type - Données d'identification(Type) - Nom du type: 670 mm
Type - Matériaux et finitions(Type) - Placard: Bois - Mélaminé blanc; Poignée: Plastique - Noir; Porte/tiroir: Bois - Mélaminé blanc
Autre - Catégorie: Meubles de rangement; Famille: Placard - 4 tiroirs: 670 mm; Famille et type: Placard - 4 tiroirs: 670 mm; ID du type: Placard - 4 tiroirs: 670 mm; Type: Placard - 4 tiroirs: 670 mm
Contraintes - Niveau: Niveau: RDC; Se déplace avec les éléments voisins: no; Décalage: 0 m; Hôte: Sol : S5 Plancher flottant habitable
Cotes - Surface: 3.16254 m2; Volume: 0.105156 m3
Phase de construction - Phase de création: Nouvelle construction
Name (Placard - 4 tiroirs:670 mm:...)
454437
454663
454714

# IfcFurnishingElement: 750 x 450 x 1680 mm, Dressing - Colonne Rangement:750 x 450 x 1680 mm:442580
In: 12
Type - ElementType: 750 x 450 x 1680 mm; Material: Mélamine - Blanche
Type - Autre(Type) - Catégorie: Meubles de rangement; Nom de la famille: Dressing - Colonne Rangement
Type - Cotes(Type) - Hauteur: 1.68 m; Largeur: 0.75 m; Profondeur: 0.45 m
Type - Données d'identification(Type) - Nom du type: 750 x 450 x 1680 mm; Numéro OmniClass: 23.40.35.00; Titre OmniClass: Casework
Type - Matériaux et finitions(Type) - Colonne: Mélamine - Blanche; Tiroirs: Mélamine - Blanche
Autre - Catégorie: Meubles de rangement; Famille: Dressing - Colonne Rangement: 750 x 450 x 1680 mm; Famille et type: Dressing - Colonne Rangement: 750 x 450 x 1680 mm; ID du type: Dressing - Colonne Rangement: 750 x 450 x 1680 mm; Type: Dressing - Colonne Rangement: 750 x 450 x 1680 mm
Construction - Tiroirs - Niche - 01: yes; Tiroirs - Niche - 02: yes
Contraintes - Niveau: Niveau: RDC; Se déplace avec les éléments voisins: no; Décalage: 0 m; Hôte: Sol : S5 Plancher flottant habitable
Cotes - Surface: 5.67669 m2; Volume: 0.093218 m3
Phase de construction - Phase de création: Nouvelle construction

# IfcFurnishingElement: 762mm x 2134mm, Table de salle à manger - Rectangulaire:762mm x 2134mm:411388
In: 20
Type - ElementType: 762mm x 2134mm; Material: Verre - Givré, Métal - Chrome
Type - Autre(Type) - Catégorie: Mobilier; Nom de la famille: Table de salle à manger - Rectangulaire
Type - Cotes(Type) - Hauteur: 0.56 m; Largeur: 0.762 m; Longueur: 2.134 m
Type - Données d'identification(Type) - Nom du type: 762mm x 2134mm
Type - Matériaux et finitions(Type) - Piètement: Métal - Chrome; Plateau: Verre - Givré
Autre - Catégorie: Mobilier; Famille: Table de salle à manger - Rectangulaire: 762mm x 2134mm; Famille et type: Table de salle à manger - Rectangulaire: 762mm x 2134mm; ID du type: Table de salle à manger - Rectangulaire: 762mm x 2134mm; Type: Table de salle à manger - Rectangulaire: 762mm x 2134mm
Contraintes - Niveau: Niveau: RDC; Se déplace avec les éléments voisins: no; Hôte: Sol : S5 Plancher flottant habitable
Cotes - Surface: 2.29341 m2; Volume: 0.0311639 m3
Phase de construction - Phase de création: Nouvelle construction

# IfcFurnishingElement: 95 x 95 x 37 cm - Noir brillant, Table basse - 02:95 x 95 x 37 cm - Noir brillant:404365
In: 13
Type - ElementType: 95 x 95 x 37 cm - Noir brillant; Material: Métal - Chrome, Aggloméré - Noir brillant
Type - Autre(Type) - Catégorie: Mobilier; Nom de la famille: Table basse - 02
Type - Cotes(Type) - Hauteur: 0.37 m; Largeur: 0.95 m
Type - Données d'identification(Type) - Nom du type: 95 x 95 x 37 cm - Noir brillant; Numéro OmniClass: 23.40.20.00; Titre OmniClass: General Furniture and Specialties
Type - Matériaux et finitions(Type) - Dessus de table: Aggloméré - Noir brillant; Structure: Métal - Chrome
Autre - Catégorie: Mobilier; Famille: Table basse - 02: 95 x 95 x 37 cm - Noir brillant; Famille et type: Table basse - 02: 95 x 95 x 37 cm - Noir brillant; ID du type: Table basse - 02: 95 x 95 x 37 cm - Noir brillant; Type: Table basse - 02: 95 x 95 x 37 cm - Noir brillant
Contraintes - Niveau: Niveau: RDC; Se déplace avec les éléments voisins: no; Décalage: 0 m; Hôte: Sol : S5 Plancher flottant habitable
Cotes - Surface: 2.28271 m2; Volume: 0.0319689 m3
Phase de construction - Phase de création: Nouvelle construction

# IfcFurnishingElement: Chaise (4)
In: 20
Type - ElementType: Chaise; Material: Métal - Chrome, Plastique - Noir, Cuir - Vert
Type - Autre(Type) - Catégorie: Mobilier; Nom de la famille: Chaise
Type - Données d'identification(Type) - Nom du type: Chaise; Numéro OmniClass: 23.40.20.00; Titre OmniClass: General Furniture and Specialties
Type - Matériaux et finitions(Type) - Chaise: Cuir - Vert; Piètement: Métal - Chrome
Autre - Catégorie: Mobilier; Famille: Chaise: Chaise; Famille et type: Chaise: Chaise; ID du type: Chaise: Chaise; Type: Chaise: Chaise
Contraintes - Niveau: Niveau: RDC; Se déplace avec les éléments voisins: no; Décalage: 0 m; Hôte: Sol : S5 Plancher flottant habitable
Cotes - Surface: 0.514861 m2; Volume: 0.0115412 m3
Phase de construction - Phase de création: Nouvelle construction
Name (Chaise:Chaise:...)
413576
413712
413765
413797

# IfcFurnishingElement: Eva_Chaise_12355 (8)
In: RDC
Type - ElementType: Eva_Chaise_12355; Classification: E2020200 Furniture & Accessories (Uniformat); Material: Vervano Wood, Vervano Fabric
Type - Autre(Type) - Catégorie: Mobilier; Nom de la famille: Eva_Chaise_12355
Type - Contraintes(Type) - Elévation par défaut: 1.2192 m
Type - Cotes(Type) - Depth: 1.651 m; Height: 0.9398 m; Width: 0.7112 m
Type - Données d'identification(Type) - Code d'assemblage: E2020200; Commentaires du type: *Change detail level to ''Fine'' to view this object or change visibility settings of extrusions*; Description de l'assemblage: Furniture & Accessories; Fabricant: Vervano; Manufacturer URL: http://vervano.com; Modèle: Eva Lounge Chair; Modeled By: The Revit Collection; Nom du type: Eva_Chaise_12355; Numéro OmniClass: 23.40.20.00; Product URL: http://vervano.com/SC-1320_Eva.pdf; Titre OmniClass: General Furniture and Specialties; URL: www.therevitcollection.com
Type - Matériaux et finitions(Type) - Fabric: Vervano Fabric; Wood: Vervano Wood
Pset_ManufacturerTypeInformation - Manufacturer: Vervano
Autre - Catégorie: Mobilier; Famille: Eva_Chaise_12355: Eva_Chaise_12355; Famille et type: Eva_Chaise_12355: Eva_Chaise_12355; ID du type: Eva_Chaise_12355: Eva_Chaise_12355; Niveau de nomenclature: Niveau: RDC; Type: Eva_Chaise_12355: Eva_Chaise_12355
Contraintes - Niveau: Niveau: RDC; Décalage: -0.07 m; Plan de construction: Niveau : RDC
Cotes - Surface: 2.14984 m2; Volume: 0.271504 m3
Phase de construction - Phase de création: Nouvelle construction
Name (Eva_Chaise_12355:Eva_Chaise_12355:...)
474618
474781
474879
474967
475091
475241
475303
475401

# IfcFurnishingElement: HAL Stool Medium (3)
In: 21
Type - ElementType: HAL Stool Medium; Classification: E2020200 Furniture & Accessories (Uniformat)
Type - Autre(Type) - Catégorie: Mobilier; base type: HAL_stool_medium; height: 0.64125 m; Nom de la famille: HAL-STOOL-MEDIUM-rfa-Vitra-273981-bimd117609; seatshell type: HAL_stool_seat
Type - Données d'identification(Type) - Authoring Version: Revit Architecture 2016; Code d'assemblage: E2020200; Commentaires du type: Vitra-HAL Stool Medium; copyright: © 2016 Vitra International AG; Description de l'assemblage: Furniture & Accessories; Fabricant: Vitra; Modèle: Vitra-HAL; Model number: 44021100; Nom du type: HAL Stool Medium; Numéro OmniClass: 23.40.20.00; Titre OmniClass: General Furniture and Specialties; URL: https://www.vitra.com/product/hal?subfam.id=125838
Type - Propriétés du modèle(Type) - BIFMA certificate: yes; ecology document: no; Greenguard: yes; GS certificate: yes
Pset_ManufacturerTypeInformation - Manufacturer: Vitra
Autre - Catégorie: Mobilier; Famille: HAL-STOOL-MEDIUM-rfa-Vitra-273981-bimd117609: HAL Stool Medium; Famille et type: HAL-STOOL-MEDIUM-rfa-Vitra-273981-bimd117609: HAL Stool Medium; ID du type: HAL-STOOL-MEDIUM-rfa-Vitra-273981-bimd117609: HAL Stool Medium; Type: HAL-STOOL-MEDIUM-rfa-Vitra-273981-bimd117609: HAL Stool Medium
Contraintes - Niveau: Niveau: RDC; Se déplace avec les éléments voisins: no; Décalage: 0 m; Hôte: Sol : S5 Plancher flottant habitable
Cotes - Surface: 0.44229 m2; Volume: 0.00326749 m3
Phase de construction - Phase de création: Nouvelle construction
Name (HAL-STOOL-MEDIUM-rfa-Vitra-273981-bimd117609:HAL Stool Medium:...)
564937
565045
565068

# IfcFurnishingElement: Le039Corbusier_Chaise_10473 (2)
Type - ElementType: Le039Corbusier_Chaise_10473; Material: INSIDE, black, metal
Type - Autre(Type) - Catégorie: Mobilier; Nom de la famille: Le039Corbusier_Chaise_10473
Type - Données d'identification(Type) - Nom du type: Le039Corbusier_Chaise_10473
Autre - Catégorie: Mobilier; Famille: Le039Corbusier_Chaise_10473: Le039Corbusier_Chaise_10473; Famille et type: Le039Corbusier_Chaise_10473: Le039Corbusier_Chaise_10473; ID du type: Le039Corbusier_Chaise_10473: Le039Corbusier_Chaise_10473; Type: Le039Corbusier_Chaise_10473: Le039Corbusier_Chaise_10473
Contraintes - Se déplace avec les éléments voisins: no; Hôte: Sol : S5 Plancher flottant habitable
Cotes - Surface: 2.17989 m2; Volume: 0.0385988 m3
Phase de construction - Phase de création: Nouvelle construction
Name (Le039Corbusier_Chaise_10473:Le039Corbusier_Chaise_10473:...) | In | Niveau | Décalage (m)
477044 | 19 | Niveau: RDC | 0
550449 | 24 | Niveau: 1er ETAGE | 3

# IfcFurnishingElement: Profondeur 600 mm, Plan de travail - Emplacement de l'évier:Profondeur 600 mm:496943
In: 21
Type - ElementType: Profondeur 600 mm; Material: Bois - Mélaminé blanc
Type - Autre(Type) - Catégorie: Meubles de rangement; Nom de la famille: Plan de travail - Emplacement de l'évier
Type - Cotes(Type) - Epaisseur du plan de travail: 0.04 m; Hauteur: 0.9 m; Profondeur: 0.625 m
Type - Données d'identification(Type) - Nom du type: Profondeur 600 mm
Type - Matériaux et finitions(Type) - Plan de travail: Bois - Mélaminé blanc
Autre - Catégorie: Meubles de rangement; Famille: Plan de travail - Emplacement de l'évier: Profondeur 600 mm; Famille et type: Plan de travail - Emplacement de l'évier: Profondeur 600 mm; ID du type: Plan de travail - Emplacement de l'évier: Profondeur 600 mm; Type: Plan de travail - Emplacement de l'évier: Profondeur 600 mm
Contraintes - Niveau: Niveau: RDC; Se déplace avec les éléments voisins: no; Décalage: 0 m; Hôte: Sol : S5 Plancher flottant habitable
Cotes - Emplacement de l'évier: 0.55 m; Emplacement de l'évier par rapport au mur: 0.1 m; Largeur de l'ouverture de l'évier: 0.73 m; Longueur: 1.1 m; Profondeur de l'ouverture de l'évier: 0.44 m; Surface: 0.567941 m2; Volume: 0.0156552 m3
Phase de construction - Phase de création: Nouvelle construction

# IfcGroup: Groupe de modèles:Groupe de réseaux 1 (8)
Autre - Catégorie: Groupes de modèles; Famille: Groupe de modèles: Groupe de réseaux 1; Famille et type: Groupe de modèles: Groupe de réseaux 1; ID du type: Groupe de modèles: Groupe de réseaux 1; Type: Groupe de modèles: Groupe de réseaux 1
Contraintes - Décalage du niveau de l'origine: 0.221 m; Niveau de référence: Niveau: RDC Faux Plafond
Autre(Type) - Catégorie: Groupes de modèles; Nom de la famille: Groupe de modèles
Données d'identification(Type) - Nom du type: Groupe de réseaux 1
Name (Groupe de modèles:Groupe de réseaux 1:...)
310685
310690
310722
310730
311007
311010
311013
311019

# IfcGroup: Groupe de modèles:Groupe de réseaux 2 (13)
Autre - Catégorie: Groupes de modèles; Famille: Groupe de modèles: Groupe de réseaux 2; Famille et type: Groupe de modèles: Groupe de réseaux 2; ID du type: Groupe de modèles: Groupe de réseaux 2; Type: Groupe de modèles: Groupe de réseaux 2
Contraintes - Niveau de référence: Niveau: RDC
Autre(Type) - Catégorie: Groupes de modèles; Nom de la famille: Groupe de modèles
Données d'identification(Type) - Nom du type: Groupe de réseaux 2
Name (Groupe de modèles:Groupe de réseaux 2:...) | Décalage du niveau de l'origine (m)
460473 | 0
461298 | 0.01
461316 | -0.01
461334 | -0.02
461352 | -0.03
461370 | -0.04
461388 | -0.05
461406 | -0.05
461460 | -0.05
461478 | -0.055
461496 | -0.055
461514 | -0.055
461532 | -0.055

# IfcMember: 60 x 120 (8)
In: RDC
Type - ElementType: 60 x 120; PredefinedType: MEMBER
Type - Autre(Type) - Catégorie: Meneaux de murs-rideaux; Nom de la famille: Meneau rectangulaire
Type - Construction(Type) - Meneau d'angle: no; Position: Perpendiculaire à la face; Profil: Profil des meneaux du système: rectangulaire; Epaisseur: 0.15 m
Type - Contraintes(Type) - Angle: 0 deg; Décaler: 0 m
Type - Cotes(Type) - Largeur du côté 1: 0.006 m; Largeur du côté 2: 0.06 m
Type - Données d'identification(Type) - Nom du type: 60 x 120
Material: Plastique, blanc opaque
Autre - Catégorie: Meneaux de murs-rideaux; Famille: Meneau rectangulaire: 60 x 120; Famille et type: Meneau rectangulaire: 60 x 120; ID du type: Meneau rectangulaire: 60 x 120; ID hôte: Mur-rideau: Simple panneau 2; Type: Meneau rectangulaire: 60 x 120
Contraintes - Niveau: Niveau: RDC
Phase de construction - Phase de création: Nouvelle construction
Pset_MemberCommon - LoadBearing: yes; IsExternal: no; Reference: 60 x 120
BaseQuantities - CrossSectionArea: 6 m2
Name (Meneau rectangulaire:60 x 120:...) | Longueur (m) = Span (m) | Surface (m2) | Volume (m3)
361933 | 3 | 0.6579 | 0.0297
361936 | 3 | 0.6579 | 0.0297
361939 | 1.868 | 0.413388 | 0.0184932
361944 | 1.868 | 0.413388 | 0.0184932
363815 | 3 | 0.6579 | 0.0297
363816 | 3 | 0.6579 | 0.0297
363817 | 1.868 | 0.413388 | 0.0184932
363818 | 1.868 | 0.413388 | 0.0184932

# IfcMember: 80 x 150 (55)
In: RDC
Type - ElementType: 80 x 150; PredefinedType: MEMBER
Type - Autre(Type) - Catégorie: Meneaux de murs-rideaux; Nom de la famille: Meneau rectangulaire
Type - Construction(Type) - Epaisseur: 0.15 m; Meneau d'angle: no; Position: Perpendiculaire à la face; Profil: Profil des meneaux du système: rectangulaire
Type - Contraintes(Type) - Angle: 0 deg; Décaler: 0 m
Type - Cotes(Type) - Largeur du côté 1: 0.03 m; Largeur du côté 2: 0.03 m
Type - Données d'identification(Type) - Nom du type: 80 x 150
Material: Plastique, blanc opaque
Autre - ID hôte: Mur-rideau: Simple panneau; Catégorie: Meneaux de murs-rideaux; Famille: Meneau rectangulaire: 80 x 150; Famille et type: Meneau rectangulaire: 80 x 150; ID du type: Meneau rectangulaire: 80 x 150; Type: Meneau rectangulaire: 80 x 150
Contraintes - Niveau: Niveau: RDC
Phase de construction - Phase de création: Nouvelle construction
Pset_MemberCommon - LoadBearing: yes; IsExternal: yes; Reference: 80 x 150
BaseQuantities - CrossSectionArea: 37 m2
Name (Meneau rectangulaire:80 x 150:...) | Longueur (m) = Span (m) | Surface (m2) | Volume (m3)
302369 | 2.15 | 0.4605 | 0.01935
302370 | 2.09 | 0.4479 | 0.01881
302371 | 0.35 | 0.0825 | 0.00315
302372 | 0.29 | 0.0699 | 0.00261
302379 | 0.29 | 0.0699 | 0.00261
302380 | 0.35 | 0.0825 | 0.00315
302381 | 2.15 | 0.4605 | 0.01935
302382 | 2.09 | 0.4479 | 0.01881
302391 | 0.29 | 0.0699 | 0.00261
302392 | 0.35 | 0.0825 | 0.00315
302393 | 2.15 | 0.4605 | 0.01935
302394 | 2.09 | 0.4479 | 0.01881
302398 | 0.29 | 0.0699 | 0.00261
302399 | 0.38 | 0.0888 | 0.00342
302400 | 2.15 | 0.4605 | 0.01935
302402 | 0.29 | 0.0699 | 0.00261
302403 | 0.35 | 0.0825 | 0.00315
302404 | 2.15 | 0.4605 | 0.01935
302405 | 2.09 | 0.4479 | 0.01881
302407 | 0.29 | 0.0699 | 0.00261
302408 | 0.35 | 0.0825 | 0.00315
302409 | 2.15 | 0.4605 | 0.01935
302410 | 2.09 | 0.4479 | 0.01881
302411 | 0.29 | 0.0699 | 0.00261
302412 | 0.35 | 0.0825 | 0.00315
302413 | 2.15 | 0.4605 | 0.01935
302414 | 2.09 | 0.4479 | 0.01881
302419 | 1.23333 | 0.268 | 0.0111
302420 | 1.23333 | 0.268 | 0.0111
302421 | 1.23333 | 0.268 | 0.0111
302422 | 1.23333 | 0.268 | 0.0111
302423 | 1.23333 | 0.268 | 0.0111
302424 | 1.23333 | 0.268 | 0.0111
302433 | 1.17333 | 0.2554 | 0.01056
302434 | 1.14333 | 0.2491 | 0.01029
302435 | 1.17333 | 0.2554 | 0.01056
302436 | 1.17333 | 0.2554 | 0.01056
302437 | 1.17333 | 0.2554 | 0.01056
302438 | 1.14333 | 0.2491 | 0.01029
302451 | 1.17333 | 0.2554 | 0.01056
302452 | 1.14333 | 0.2491 | 0.01029
302453 | 1.17333 | 0.2554 | 0.01056
302454 | 1.17333 | 0.2554 | 0.01056
302455 | 1.17333 | 0.2554 | 0.01056
302456 | 1.14333 | 0.2491 | 0.01029
302468 | 1.17333 | 0.2554 | 0.01056
302469 | 1.14333 | 0.2491 | 0.01029
302470 | 1.17333 | 0.2554 | 0.01056
302471 | 1.17333 | 0.2554 | 0.01056
302472 | 1.17333 | 0.2554 | 0.01056
302473 | 1.14333 | 0.2491 | 0.01029
302487 | 1.23333 | 0.268 | 0.0111
302488 | 1.26333 | 0.2743 | 0.01137
302489 | 1.26333 | 0.2743 | 0.01137
302491 | 1.23333 | 0.268 | 0.0111

# IfcOpeningElement: Opening (46)
Name | In
Mur de base:M7 Ext. Crépis 2 + BBMC 20 + Isolant 11:237404 | RDC | BaseQuantities - Area: 4.725 m2; Nomenclature de mur - Famille: Mur de base: M7 Ext. Crépis 2 + BBMC 20 + Isolant 11; Famille et type: Mur de base: M7 Ext. Crépis 2 + BBMC 20 + Isolant 11; Matériau structurel: Blocs béton manufacturés; Longueur: 6.475 m; Largeur: 0.33 m; Surface: 26.7448 m2; Volume: 8.81219 m3; Commentaires: porteur; Relevé de matériaux de mur détaillé - Famille et type: Mur de base: M7 Ext. Crépis 2 + BBMC 20 + Isolant 11; sets with these values: 2
Mur de base:M7 Ext. Crépis 2 + BBMC 20 + Isolant 11:237404 | RDC | BaseQuantities - Area: 0.2475 m2; Relevé de matériaux de mur détaillé - Famille et type: Mur de base: M7 Ext. Crépis 2 + BBMC 20 + Isolant 11; sets with these values: 2
Mur de base:Ext. Crépis 2 + BBMC 20:240386 | 1 Mur de soubassement | BaseQuantities - Area: 0.0725 m2; Nomenclature de mur - Famille: Mur de base: Ext. Crépis 2 + BBMC 20; Famille et type: Mur de base: Ext. Crépis 2 + BBMC 20; Matériau structurel: Blocs béton manufacturés; Longueur: 6.255 m; Largeur: 0.22 m; Surface: 18.7718 m2; Volume: 4.10381 m3; Commentaires: porteur; Relevé de matériaux de mur détaillé - Famille et type: Mur de base: Ext. Crépis 2 + BBMC 20; sets with these values: 2
Int. Simple:PP (0.73m x 2.04m):273819:1 | RDC | BaseQuantities - Depth: 0.07 m; Height: 0.8 m; Width: 2.075 m
Placard coulissante - 3 panneaux:Placard coulissante - 3 panneaux:273212:1 | RDC | BaseQuantities - Depth: 0.07 m; Height: 1.8 m; Width: 2.1 m
Int. Simple:PP (0.73m x 2.04m):273653:1 | RDC | BaseQuantities - Depth: 0.07 m; Height: 0.8 m; Width: 2.075 m
Int. Simple:PP (0.73m x 2.04m):273705:1 | RDC | BaseQuantities - Depth: 0.07 m; Height: 0.8 m; Width: 2.075 m
Int. Simple:PP (0.73m x 2.04m):273553:1 | RDC | BaseQuantities - Depth: 0.07 m; Height: 0.8 m; Width: 2.075 m
Placard coulissante - 3 panneaux:Placard coulissante - 3 panneaux:273299:1 | RDC | BaseQuantities - Depth: 0.07 m; Height: 1.8 m; Width: 2.1 m
Int. Simple:PP (0.73m x 2.04m):273523:1 | RDC | BaseQuantities - Depth: 0.07 m; Height: 0.8 m; Width: 2.075 m
Placard coulissante - 3 panneaux:Placard coulissante - 3 panneaux:273082:1 | RDC | BaseQuantities - Depth: 0.07 m; Height: 1.8 m; Width: 2.1 m
Int. Simple:PP (0.73m x 2.04m):273482:1 | RDC | BaseQuantities - Depth: 0.07 m; Height: 0.8 m; Width: 2.075 m
Int. Simple:PP (0.73m x 2.04m):273407:1 | RDC | BaseQuantities - Depth: 0.07 m; Height: 0.8 m; Width: 2.075 m
Sol:Terrasse bois:475692:2 | RDC | BaseQuantities - Depth: 0.1 m; Height: 8.595 m; Width: 4.1 m
Int. Simple:PP (0.73m x 2.04m):271522:1 | RDC | BaseQuantities - Depth: 0.07 m; Height: 0.8 m; Width: 2.075 m
Plan de travail - Emplacement de l'évier:Profondeur 600 mm:496943:1 | 21 | BaseQuantities - Area: 0.0269355 m2; Depth: 1.1 m
4 x Mur de base:M8 Ext. Bois 2 + Isolant 12 + BBMC 20 + vide 1 + ba13:253777 | RDC
Mur de base:M7 Ext. Crépis 2 + BBMC 20 + Isolant 11:239197 | RDC
7 x Mur de base:M7 Ext. Crépis 2 + BBMC 20 + Isolant 11:239240 | RDC
Ouverture en rectangle:Ouverture en rectangle:275426:1 | RDC | BaseQuantities - Depth: 0.33 m; Height: 1 m; Width: 2.1 m
3 x Mur de base:M7 Ext. Crépis 2 + BBMC 20 + Isolant 11:239378 | RDC
3 x Mur de base:M7 Ext. Crépis 2 + BBMC 20 + Isolant 11:239726 | RDC
Mur de base:M7 Ext. Crépis 2 + BBMC 20 + Isolant 11:239803 | RDC
2 x Mur de base:Ext. Crépis 2 + BBMC 20:244944 | 1 Mur de soubassement
Mur de base:Ext. Crépis 2 + BBMC 20:245283 | 1 Mur de soubassement | BaseQuantities - Depth: 0.82 m; Height: 2.43 m; Width: 2.015 m
Mur de base:M8 Ext. Bois 2 + Isolant 12 + BBMC 20 + vide 1 + ba13:253071 | RDC
2 x Mur de base:M8 Ext. Bois 2 + Isolant 12 + BBMC 20 + vide 1 + ba13:253190 | RDC
2 x Mur de base:M8 Ext. Bois 2 + Isolant 12 + BBMC 20 + vide 1 + ba13:253549 | RDC
Mur de base:M8 Ext. Bois 2 + Isolant 12 + BBMC 20 + vide 1 + ba13:253662 | RDC
Ouverture en rectangle:Ouverture en rectangle:275736:1 | RDC | BaseQuantities - Depth: 0.35 m; Height: 1 m; Width: 2.1 m

# IfcPlate: Vitré (24)
In: RDC
Type - ElementType: Vitré; PredefinedType: CURTAIN_PANEL; Material: Verre 0.04 m
Type - Autre(Type) - Catégorie: Panneaux de murs-rideaux; Nom de la famille: Panneau système
Type - Contraintes(Type) - Décaler: 0.025 m
Type - Cotes(Type) - Epaisseur: 0.04 m
Type - Données d'identification(Type) - Nom du type: Vitré
Type - Matériaux et finitions(Type) - Matériau: Verre, vitrage transparent
Type - Propriétés analytiques(Type) - Coefficient d'apport thermique solaire: 0.86; Coefficient de transfert de chaleur (U): 6.7069; Construction analytique: Simple vitrage Pilkington 1/8 po.; Résistance thermique (R): 0.1491; Transmission de la lumière visible: 0.9
Autre - Catégorie: Panneaux de murs-rideaux; Famille: Panneau système: Vitré; Famille et type: Panneau système: Vitré; ID du type: Panneau système: Vitré; Type: Panneau système: Vitré
Contraintes - Niveau: Niveau: RDC
Phase de construction - Phase de création: Nouvelle construction
Pset_PlateCommon - LoadBearing: yes; Reference: Vitré; ThermalTransmittance: 6.7069 kg/K/s3
Name (Panneau système:Vitré:...) | ID hôte | Hauteur (m) | Largeur (m) | Surface (m2) | Volume (m3) | IsExternal
298384 | Mur-rideau: Simple panneau | 2.06 | 1.14333 | 2.35527 | 0.0942107 | yes
301356 | Mur-rideau: Simple panneau | 2.06 | 1.17333 | 2.41707 | 0.0966827 | yes
300974 | Mur-rideau: Simple panneau | 2.06 | 1.17333 | 2.41707 | 0.0966827 | yes
301400 | Mur-rideau: Simple panneau | 2.06 | 1.14333 | 2.35527 | 0.0942107 | yes
301221 | Mur-rideau: Simple panneau | 0.29 | 1.14333 | 0.331567 | 0.0132627 | yes
301357 | Mur-rideau: Simple panneau | 0.29 | 1.17333 | 0.340267 | 0.0136107 | yes
301222 | Mur-rideau: Simple panneau | 0.29 | 1.17333 | 0.340267 | 0.0136107 | yes
301889 | Mur-rideau: Simple panneau | 0.29 | 1.17333 | 0.340267 | 0.0136107 | yes
301223 | Mur-rideau: Simple panneau | 0.29 | 1.17333 | 0.340267 | 0.0136107 | yes
301401 | Mur-rideau: Simple panneau | 0.29 | 1.14333 | 0.331567 | 0.0132627 | yes
301143 | Mur-rideau: Simple panneau | 2.09 | 1.14333 | 2.38957 | 0.0955827 | yes
301358 | Mur-rideau: Simple panneau | 2.09 | 1.17333 | 2.45227 | 0.0980907 | yes
301144 | Mur-rideau: Simple panneau | 2.09 | 1.17333 | 2.45227 | 0.0980907 | yes
301890 | Mur-rideau: Simple panneau | 2.09 | 1.17333 | 2.45227 | 0.0980907 | yes
301145 | Mur-rideau: Simple panneau | 2.09 | 1.17333 | 2.45227 | 0.0980907 | yes
301402 | Mur-rideau: Simple panneau | 2.09 | 1.14333 | 2.38957 | 0.0955827 | yes
301276 | Mur-rideau: Simple panneau | 0.26 | 1.14333 | 0.297267 | 0.0118907 | yes
301359 | Mur-rideau: Simple panneau | 0.26 | 1.17333 | 0.305067 | 0.0122027 | yes
301277 | Mur-rideau: Simple panneau | 0.26 | 1.17333 | 0.305067 | 0.0122027 | yes
301891 | Mur-rideau: Simple panneau | 0.26 | 1.17333 | 0.305067 | 0.0122027 | yes
301278 | Mur-rideau: Simple panneau | 0.26 | 1.17333 | 0.305067 | 0.0122027 | yes
301403 | Mur-rideau: Simple panneau | 0.26 | 1.14333 | 0.297267 | 0.0118907 | yes
360756 | Mur-rideau: Simple panneau 2 | 2.868 | 1.868 | 5.35742 | 0.214297 | no
363814 | Mur-rideau: Simple panneau 2 | 2.868 | 1.868 | 5.35742 | 0.214297 | no

# IfcRailing: Garde-corps:Type Bateau (3)
In: 1er ETAGE
Material: Peinture - Grise, Pin (1)
Pset_RailingCommon - IsExternal: no; Reference: Type Bateau; Height: 1.19 m
Autre - Catégorie: Garde-corps; Famille: Garde-corps: Type Bateau; Famille et type: Garde-corps: Type Bateau; ID du type: Garde-corps: Type Bateau; Type: Garde-corps: Type Bateau
Contraintes - Décalage inférieur: 0 m; Décalage marche/limon à la française: 0 m; Niveau de base: Niveau: 1er ETAGE
Phase de construction - Phase de création: Nouvelle construction
Autre(Type) - Catégorie: Garde-corps; Nom de la famille: Garde-corps
Construction(Type) - Connexion des traverses: Ajuster; Décalage des barreaux: 0 m; Joints d'angle: Ajouter des segments verticaux/horizontaux; Joints tangents: Prolonger la traverse jusqu'à; Réglage de la hauteur du palier: 0 m; Utiliser le réglage de la hauteur du palier: Non; Hauteur du garde-corps: 1.19 m
Données d'identification(Type) - Nom du type: Type Bateau
Main courante 1(Type) - Position: Aucune; sets with these values: 2
Traverse haute(Type) - Type: Type de traverse haute: Elliptique - Bois; Hauteur: 1.19 m
Name (Garde-corps:Type Bateau:...) | Length (m) = Longueur (m)
319351 | 14.14
320029 | 4.36
320373 | 3.16882

# IfcRailing: Garde-corps:Type Bateau escalier 2 (5)
In: RDC
Material: Peinture - Grise, Pin (1)
Pset_RailingCommon - IsExternal: no; Reference: Type Bateau escalier 2; Height: 0.97 m
Autre - Catégorie: Garde-corps; Famille: Garde-corps: Type Bateau escalier 2; Famille et type: Garde-corps: Type Bateau escalier 2; ID du type: Garde-corps: Type Bateau escalier 2; Type: Garde-corps: Type Bateau escalier 2
Contraintes - Décalage inférieur: 0 m
Phase de construction - Phase de création: Nouvelle construction
Autre(Type) - Catégorie: Garde-corps; Nom de la famille: Garde-corps
Construction(Type) - Connexion des traverses: Ajuster; Décalage des barreaux: 0 m; Hauteur du garde-corps: 0.97 m; Joints d'angle: Ajouter des segments verticaux/horizontaux; Joints tangents: Prolonger la traverse jusqu'à; Réglage de la hauteur du palier: 0 m; Utiliser le réglage de la hauteur du palier: Non
Données d'identification(Type) - Nom du type: Type Bateau escalier 2
Main courante 1(Type) - Position: Aucune; sets with these values: 2
Traverse haute(Type) - Hauteur: 0.97 m; Type: Type de traverse haute: Elliptique - Bois
Name (Garde-corps:Type Bateau escalier 2:...) | Length (m) = Longueur (m) | Décalage marche/limon à la française (m) | Niveau de base
317459 | 5.72334 | 0.05
557502 | 2.70702 | 0 | Niveau: RDC
562726 | 1 | 0.02 | Niveau: RDC
562961 | 2.6065 | -0.02 | Niveau: RDC
563069 | 1 | -0.02 | Niveau: RDC

# IfcRoof: Toit de base:Panneau toiture, Toit de base:Panneau toiture:347312
In: 1er Chainage
Pset_RoofCommon - IsExternal: yes; Reference: Panneau toiture; TotalArea: 147.395 m2; ProjectedArea: 139.12 m2
Autre - Catégorie: Toits; Famille: Toit de base: Panneau toiture; Famille et type: Toit de base: Panneau toiture; ID du type: Toit de base: Panneau toiture; Type: Toit de base: Panneau toiture
Construction - Coupe en chevron: Coupe verticale; Hauteur maximale de l'arrête: 8.21225 m; Profondeur du bord de toiture: 0 m
Contraintes - Lié au volume: no; Limite de pièce: yes; Décalage de la coupure: 0 m; Décalage inférieur à partir du niveau: 0.46 m; Niveau de base: Niveau: 1er Chainage
Cotes - Epaisseur: 0.29 m; Inclinaison: 0.349999; Surface: 147.395 m2; Volume: 42.7445 m3
Phase de construction - Phase de création: Nouvelle construction
Autre(Type) - Catégorie: Toits; Nom de la famille: Toit de base
Construction(Type) - Epaisseur par défaut: 0.29 m
Données d'identification(Type) - Nom du type: Panneau toiture
Graphismes(Type) - Couleur vue détail faible: 0
Propriétés analytiques(Type) - Rugosité: 3; Coefficient d'absorbance: 0.7

# IfcSlab: Base rectangulaire:800mm x600mm x 300mm (2)
In: 1 Mur de soubassement
PredefinedType: FLOOR; Material: Béton - Béton coulé sur place
Pset_SlabCommon - IsExternal: no; PitchAngle: 0 deg; Reference: 800mm x600mm x 300mm
BaseQuantities - GrossArea: 0.48 m2; GrossVolume: 0.144 m3; Perimeter: 2.8 m; Width: 0.3 m
Autre - Catégorie: Fondations; Famille: Base rectangulaire: 800mm x600mm x 300mm; Famille et type: Base rectangulaire: 800mm x600mm x 300mm; ID du type: Base rectangulaire: 800mm x600mm x 300mm; Type: Base rectangulaire: 800mm x600mm x 300mm
Contraintes - Se déplace avec les quadrillages: yes; Décalage: 0 m; Hôte: Niveau : 1 Mur de soubassement; Niveau: Niveau: 1 Mur de soubassement
Cotes - Elévation à la base: -1.3 m; Elévation en haut: -1 m; Largeur: 0.6 m; Longueur: 0.8 m; Surface: 0.96 m2; Volume: 0.288 m3
Matériaux et finitions - Matériau structurel: Béton - Béton coulé sur place
Phase de construction - Phase de création: Nouvelle construction
Structure - Activer le modèle analytique: yes; Enrobage d'armature - Autres faces: Paramètres de l'enrobage d'armature: Enrobage d'armature 1; Enrobage d'armature - Face inférieure: Paramètres de l'enrobage d'armature: Enrobage d'armature 1; Enrobage d'armature - Face supérieure: Paramètres de l'enrobage d'armature: Enrobage d'armature 1
Autre(Type) - Catégorie: Fondations; Nom de la famille: Base rectangulaire
Cotes(Type) - Epaisseur: 0.3 m; Largeur: 0.6 m; Longueur: 0.8 m
Données d'identification(Type) - Nom du type: 800mm x600mm x 300mm
Name (Base rectangulaire:800mm x600mm x 300mm:...)
356645
356698

# IfcSlab: Sol:Bloc plongeoir, Sol:Bloc plongeoir:487290
In: RDC
PredefinedType: FLOOR; Material: Maçonnerie - Béton 0.35 m
Pset_SlabCommon - LoadBearing: no; IsExternal: no; PitchAngle: 0 deg; Reference: Bloc plongeoir
BaseQuantities - GrossArea: 0.16 m2; GrossVolume: 0.056 m3; Perimeter: 1.6 m; Width: 0.35 m
Autre - Catégorie: Sols; Famille: Sol: Bloc plongeoir; Famille et type: Sol: Bloc plongeoir; ID du type: Sol: Bloc plongeoir; Type: Sol: Bloc plongeoir
Contraintes - Lié au volume: no; Limite de pièce: yes; Niveau: Niveau: RDC; Décalage par rapport au niveau: 0.28 m
Cotes - Elévation à la base: -0.07 m; Elévation en haut: 0.28 m; Epaisseur: 0.35 m; Périmètre: 1.6 m; Surface: 0.16 m2; Volume: 0.056 m3
Phase de construction - Phase de création: Nouvelle construction
Structure - Activer le modèle analytique: no; Structure: no
Autre(Type) - Catégorie: Sols; Nom de la famille: Sol
Construction(Type) - Fonction: Intérieur; Epaisseur par défaut: 0.35 m
Données d'identification(Type) - Nom du type: Bloc plongeoir
Graphismes(Type) - Couleur vue détail faible: 0
Matériaux et finitions(Type) - Matériau structurel: Maçonnerie - Béton
Propriétés analytiques(Type) - Rugosité: 3; Coefficient d'absorbance: 0.7

# IfcSlab: Sol:Dallage garage, Sol:Dallage garage:264275
In: RDC
PredefinedType: FLOOR; Material: Maçonnerie - Béton 0.15 m, Sable 0.05 m, Tout venant 0.2 m
Pset_SlabCommon - LoadBearing: yes; IsExternal: no; Reference: Dallage garage; ThermalTransmittance: 1000000000000000019884624838656 kg/K/s3; PitchAngle: 0 deg
BaseQuantities - GrossArea: 42.7845 m2; GrossVolume: 17.1138 m3; Perimeter: 34.6 m; Width: 0.4 m
Autre - Catégorie: Sols; Famille: Sol: Dallage garage; Famille et type: Sol: Dallage garage; ID du type: Sol: Dallage garage; Type: Sol: Dallage garage
Contraintes - Lié au volume: no; Limite de pièce: yes; Décalage par rapport au niveau: 0 m; Niveau: Niveau: RDC
Cotes - Elévation à la base: -0.4 m; Elévation au niveau du noyau inférieur: -0.15 m; Elévation au niveau du noyau supérieur: 0 m; Elévation en haut: 0 m; Epaisseur: 0.4 m; Périmètre: 34.6 m; Surface: 42.7845 m2; Volume: 17.1138 m3
Phase de construction - Phase de création: Nouvelle construction
Structure - Activer le modèle analytique: yes; Enrobage d'armature - Autres faces: Paramètres de l'enrobage d'armature: Enrobage d'armature 1; Structure: yes; Enrobage d'armature - Face inférieure: Paramètres de l'enrobage d'armature: Enrobage d'armature 1; Enrobage d'armature - Face supérieure: Paramètres de l'enrobage d'armature: Enrobage d'armature 1
Autre(Type) - Catégorie: Sols; Nom de la famille: Sol
Construction(Type) - Fonction: Intérieur; Epaisseur par défaut: 0.4 m
Données d'identification(Type) - Nom du type: Dallage garage
Graphismes(Type) - Couleur vue détail faible: 0
Matériaux et finitions(Type) - Matériau structurel: Maçonnerie - Béton
Propriétés analytiques(Type) - Rugosité: 3; Coefficient d'absorbance: 0.7; Coefficient de transfert de chaleur (U): 1000000000000000019884624838656; Masse thermique: 0; Résistance thermique (R): 0

# IfcSlab: Sol:Dallage sanitaire entrée, Sol:Dallage sanitaire entrée:477716
In: RDC
PredefinedType: FLOOR; Material: Parquet bois 0.02 m, Maçonnerie - Béton 0.13 m, Sable 0.05 m, Tout venant 0.2 m
Pset_SlabCommon - LoadBearing: no; IsExternal: no; PitchAngle: 0 deg; Reference: Dallage sanitaire entrée; ThermalTransmittance: 1000000000000000019884624838656 kg/K/s3
BaseQuantities - GrossArea: 4.1191 m2; GrossVolume: 1.64764 m3; Perimeter: 8.2 m; Width: 0.4 m
Autre - Catégorie: Sols; Famille: Sol: Dallage sanitaire entrée; Famille et type: Sol: Dallage sanitaire entrée; ID du type: Sol: Dallage sanitaire entrée; Type: Sol: Dallage sanitaire entrée
Contraintes - Lié au volume: no; Limite de pièce: yes; Décalage par rapport au niveau: 0 m; Niveau: Niveau: RDC
Cotes - Elévation en haut: 0 m; Elévation à la base: -0.4 m; Epaisseur: 0.4 m; Périmètre: 8.2 m; Surface: 4.1191 m2; Volume: 1.64764 m3
Phase de construction - Phase de création: Nouvelle construction
Structure - Activer le modèle analytique: no; Structure: no
Autre(Type) - Catégorie: Sols; Nom de la famille: Sol
Construction(Type) - Fonction: Intérieur; Epaisseur par défaut: 0.4 m
Données d'identification(Type) - Nom du type: Dallage sanitaire entrée
Graphismes(Type) - Couleur vue détail faible: 0
Matériaux et finitions(Type) - Matériau structurel: Maçonnerie - Béton
Propriétés analytiques(Type) - Rugosité: 3; Masse thermique: 0; Résistance thermique (R): 0; Coefficient d'absorbance: 0.7; Coefficient de transfert de chaleur (U): 1000000000000000019884624838656

# IfcSlab: Sol:Dalle ba 20 + Enduit sf 2, Sol:Dalle ba 20 + Enduit sf 2:358206
In: 1er Chainage
PredefinedType: FLOOR; Material: Maçonnerie - Béton 0.2 m, Maçonnerie - Enduit 0.02 m
Pset_SlabCommon - LoadBearing: yes; IsExternal: no; PitchAngle: 0 deg; Reference: Dalle ba 20 + Enduit sf 2; ThermalTransmittance: 26 kg/K/s3
BaseQuantities - GrossArea: 11.4841 m2; GrossVolume: 2.5265 m3; Perimeter: 18.7401 m; Width: 0.22 m
Autre - Catégorie: Sols; Famille: Sol: Dalle ba 20 + Enduit sf 2; Famille et type: Sol: Dalle ba 20 + Enduit sf 2; ID du type: Sol: Dalle ba 20 + Enduit sf 2; Type: Sol: Dalle ba 20 + Enduit sf 2
Contraintes - Lié au volume: no; Limite de pièce: yes; Niveau: Niveau: 1er Chainage; Décalage par rapport au niveau: 0.2 m
Cotes - Elévation à la base: 5.78 m; Elévation au niveau du noyau inférieur: 5.8 m; Elévation au niveau du noyau supérieur: 6 m; Elévation en haut: 6 m; Epaisseur: 0.22 m; Périmètre: 18.7401 m; Surface: 11.4841 m2; Volume: 2.5265 m3
Phase de construction - Phase de création: Nouvelle construction
Structure - Activer le modèle analytique: yes; Enrobage d'armature - Autres faces: Paramètres de l'enrobage d'armature: Enrobage d'armature 1; Structure: yes; Enrobage d'armature - Face inférieure: Paramètres de l'enrobage d'armature: Enrobage d'armature 1; Enrobage d'armature - Face supérieure: Paramètres de l'enrobage d'armature: Enrobage d'armature 1
Autre(Type) - Catégorie: Sols; Nom de la famille: Sol
Construction(Type) - Fonction: Intérieur; Epaisseur par défaut: 0.22 m
Données d'identification(Type) - Nom du type: Dalle ba 20 + Enduit sf 2
Graphismes(Type) - Couleur vue détail faible: 0
Matériaux et finitions(Type) - Matériau structurel: Maçonnerie - Béton
Propriétés analytiques(Type) - Rugosité: 3; Coefficient d'absorbance: 0.7; Coefficient de transfert de chaleur (U): 26; Masse thermique: 20160; Résistance thermique (R): 0.0384615

# IfcSlab: Sol:Dalle en béton - 200 mm, Sol:Dalle en béton - 200 mm:472279
In: PIscine
PredefinedType: FLOOR; Material: Béton, coulé sur place 0.2 m
Pset_SlabCommon - LoadBearing: yes; IsExternal: no; PitchAngle: 0 deg; Reference: Dalle en béton - 200 mm; ThermalTransmittance: 5.23 kg/K/s3
BaseQuantities - GrossArea: 40.5 m2; GrossVolume: 8.1 m3; Perimeter: 27 m; Width: 0.2 m
Autre - Catégorie: Sols; Famille: Sol: Dalle en béton - 200 mm; Famille et type: Sol: Dalle en béton - 200 mm; ID du type: Sol: Dalle en béton - 200 mm; Type: Sol: Dalle en béton - 200 mm
Contraintes - Lié au volume: no; Limite de pièce: yes; Décalage par rapport au niveau: 0.2 m; Niveau: Niveau: PIscine
Cotes - Elévation à la base: -2.2 m; Elévation au niveau du noyau inférieur: -2.2 m; Elévation au niveau du noyau supérieur: -2 m; Elévation en haut: -2 m; Epaisseur: 0.2 m; Périmètre: 27 m; Surface: 40.5 m2; Volume: 8.1 m3
Phase de construction - Phase de création: Nouvelle construction
Structure - Activer le modèle analytique: yes; Enrobage d'armature - Autres faces: Paramètres de l'enrobage d'armature: Enrobage d'armature 1; Structure: yes; Enrobage d'armature - Face inférieure: Paramètres de l'enrobage d'armature: Enrobage d'armature 1; Enrobage d'armature - Face supérieure: Paramètres de l'enrobage d'armature: Enrobage d'armature 1
Autre(Type) - Catégorie: Sols; Nom de la famille: Sol
Construction(Type) - Fonction: Intérieur; Epaisseur par défaut: 0.2 m
Données d'identification(Type) - Nom du type: Dalle en béton - 200 mm
Graphismes(Type) - Couleur vue détail faible: 0
Matériaux et finitions(Type) - Matériau structurel: Béton, coulé sur place
Propriétés analytiques(Type) - Rugosité: 3; Coefficient d'absorbance: 0.7; Coefficient de transfert de chaleur (U): 5.23; Masse thermique: 302220; Résistance thermique (R): 0.191205

# IfcSlab: Sol:Dalle pierre acces pieton (14)
In: RDC
PredefinedType: FLOOR; Material: Pierre beige 0.05 m
Pset_SlabCommon - LoadBearing: no; IsExternal: no; PitchAngle: 0 deg; Reference: Dalle pierre acces pieton
BaseQuantities - Width: 0.05 m
Autre - Catégorie: Sols; Famille: Sol: Dalle pierre acces pieton; Famille et type: Sol: Dalle pierre acces pieton; ID du type: Sol: Dalle pierre acces pieton; Type: Sol: Dalle pierre acces pieton
Contraintes - Lié au volume: no; Limite de pièce: yes; Niveau: Niveau: RDC
Cotes - Epaisseur: 0.05 m
Phase de construction - Phase de création: Nouvelle construction
Structure - Activer le modèle analytique: no; Structure: no
Autre(Type) - Catégorie: Sols; Nom de la famille: Sol
Construction(Type) - Fonction: Intérieur; Epaisseur par défaut: 0.05 m
Données d'identification(Type) - Nom du type: Dalle pierre acces pieton
Graphismes(Type) - Couleur vue détail faible: 0
Propriétés analytiques(Type) - Rugosité: 3; Coefficient d'absorbance: 0.7
Name (Sol:Dalle pierre acces pieton:...) | GrossArea (m2) = Surface (m2) | GrossVolume (m3) = Volume (m3) | Perimeter (m) = Périmètre (m) | Décalage par rapport au niveau (m) = Elévation en haut (m) | Elévation à la base (m) | Group
460468 | 0.36 | 0.018 | 2.4 | -0.05 | -0.1 | Groupe de modèles:Groupe de réseaux 2:460473
461310 | 0.36 | 0.018 | 2.4 | -0.04 | -0.09 | Groupe de modèles:Groupe de réseaux 2:461298
461328 | 0.36 | 0.018 | 2.4 | -0.06 | -0.11 | Groupe de modèles:Groupe de réseaux 2:461316
461346 | 0.36 | 0.018 | 2.4 | -0.07 | -0.12 | Groupe de modèles:Groupe de réseaux 2:461334
461364 | 0.36 | 0.018 | 2.4 | -0.08 | -0.13 | Groupe de modèles:Groupe de réseaux 2:461352
461382 | 0.36 | 0.018 | 2.4 | -0.09 | -0.14 | Groupe de modèles:Groupe de réseaux 2:461370
461400 | 0.36 | 0.018 | 2.4 | -0.1 | -0.15 | Groupe de modèles:Groupe de réseaux 2:461388
461418 | 0.36 | 0.018 | 2.4 | -0.1 | -0.15 | Groupe de modèles:Groupe de réseaux 2:461406
461472 | 0.36 | 0.018 | 2.4 | -0.1 | -0.15 | Groupe de modèles:Groupe de réseaux 2:461460
461490 | 0.36 | 0.018 | 2.4 | -0.105 | -0.155 | Groupe de modèles:Groupe de réseaux 2:461478
461508 | 0.36 | 0.018 | 2.4 | -0.105 | -0.155 | Groupe de modèles:Groupe de réseaux 2:461496
461526 | 0.36 | 0.018 | 2.4 | -0.105 | -0.155 | Groupe de modèles:Groupe de réseaux 2:461514
461544 | 0.36 | 0.018 | 2.4 | -0.105 | -0.155 | Groupe de modèles:Groupe de réseaux 2:461532
461789 | 6.4384 | 0.32192 | 11.3 | -0.04 | -0.09

# IfcSlab: Sol:Plan de travail cuisine, Sol:Plan de travail cuisine:484805
In: RDC
PredefinedType: FLOOR; Material: Bois - Mélaminé blanc 0.035 m
Pset_SlabCommon - LoadBearing: no; IsExternal: no; PitchAngle: 0 deg; Reference: Plan de travail cuisine
BaseQuantities - GrossArea: 2.43719 m2; GrossVolume: 0.0853015 m3; Perimeter: 6.65606 m; Width: 0.035 m
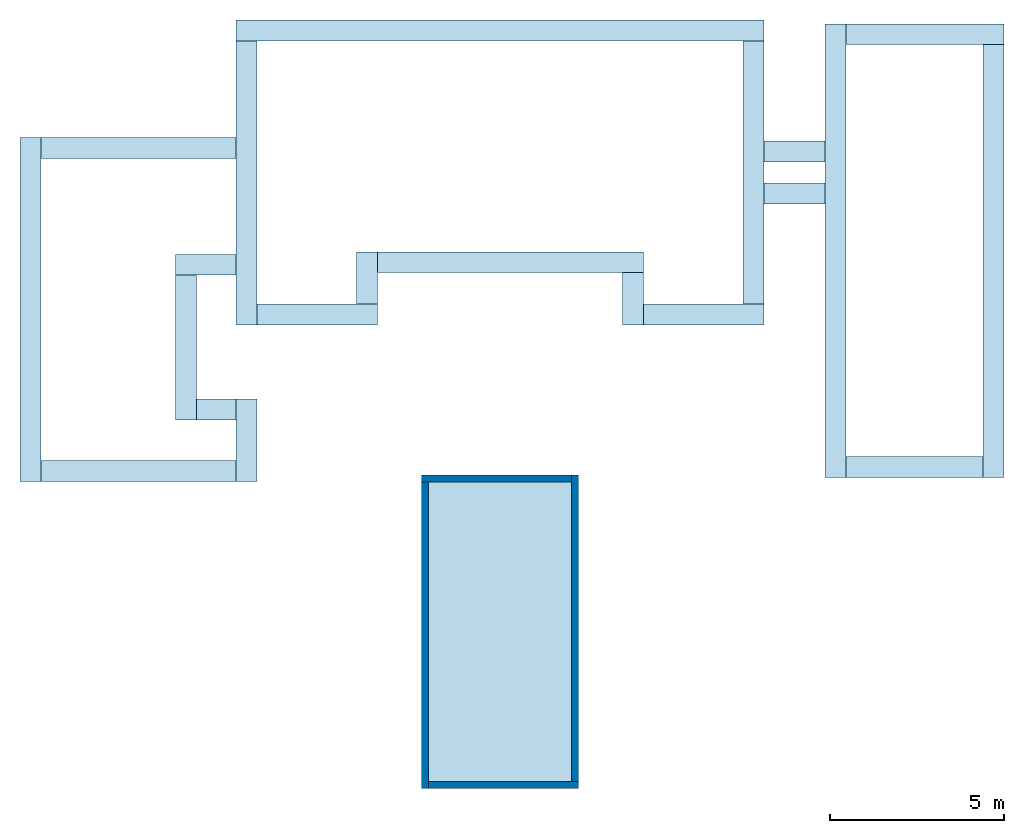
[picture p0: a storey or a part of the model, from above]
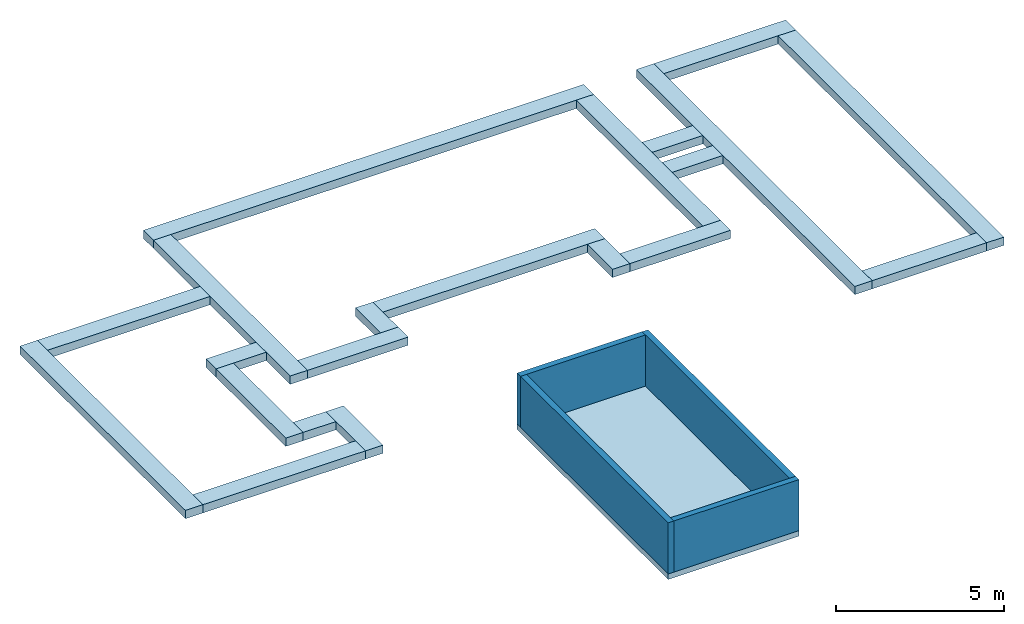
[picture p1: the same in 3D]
Properties of the parts of a building model (IFC2X3), part 3 of 4

# IfcSlab: Sol:Plan de travail cuisine, Sol:Plan de travail cuisine:484805
Autre - Catégorie: Sols; Famille: Sol: Plan de travail cuisine; Famille et type: Sol: Plan de travail cuisine; ID du type: Sol: Plan de travail cuisine; Type: Sol: Plan de travail cuisine
Contraintes - Lié au volume: no; Limite de pièce: yes; Niveau: Niveau: RDC; Décalage par rapport au niveau: 0.907 m
Cotes - Elévation à la base: 0.872 m; Elévation en haut: 0.907 m; Epaisseur: 0.035 m; Périmètre: 6.65606 m; Surface: 2.43719 m2; Volume: 0.0853015 m3
Phase de construction - Phase de création: Nouvelle construction
Structure - Activer le modèle analytique: no; Structure: no
Autre(Type) - Catégorie: Sols; Nom de la famille: Sol
Construction(Type) - Fonction: Intérieur; Epaisseur par défaut: 0.035 m
Données d'identification(Type) - Nom du type: Plan de travail cuisine
Graphismes(Type) - Couleur vue détail faible: 0
Matériaux et finitions(Type) - Matériau structurel: Bois - Mélaminé blanc
Propriétés analytiques(Type) - Rugosité: 3; Coefficient d'absorbance: 0.7

# IfcSlab: Sol:Plancher bois, Sol:Plancher bois:315704
In: 1er ETAGE
PredefinedType: FLOOR; Material: Bois - Chêne 0.04 m
Pset_SlabCommon - LoadBearing: no; IsExternal: no; PitchAngle: 0 deg; Reference: Plancher bois
BaseQuantities - GrossArea: 58.9851 m2; GrossVolume: 2.3594 m3; Perimeter: 43.9576 m; Width: 0.04 m
Autre - Catégorie: Sols; Famille: Sol: Plancher bois; Famille et type: Sol: Plancher bois; ID du type: Sol: Plancher bois; Type: Sol: Plancher bois
Contraintes - Lié au volume: no; Limite de pièce: yes; Décalage par rapport au niveau: 0.04 m; Niveau: Niveau: 1er ETAGE
Cotes - Elévation à la base: 3 m; Elévation en haut: 3.04 m; Epaisseur: 0.04 m; Périmètre: 43.9576 m; Surface: 58.9851 m2; Volume: 2.3594 m3
Phase de construction - Phase de création: Nouvelle construction
Structure - Activer le modèle analytique: no; Structure: no
Autre(Type) - Catégorie: Sols; Nom de la famille: Sol
Construction(Type) - Fonction: Intérieur; Epaisseur par défaut: 0.04 m
Données d'identification(Type) - Nom du type: Plancher bois
Graphismes(Type) - Couleur vue détail faible: 0
Propriétés analytiques(Type) - Rugosité: 3; Coefficient d'absorbance: 0.7

# IfcSlab: Sol:Plancher espace nuit, Sol:Plancher espace nuit:269388
In: RDC
PredefinedType: FLOOR; Material: Parquet bois 0.02 m, Chape 0.05 m, Maçonnerie - Isolant 0.05 m, Maçonnerie - Béton 0.2 m
Pset_SlabCommon - LoadBearing: yes; IsExternal: no; PitchAngle: 0 deg; Reference: Plancher espace nuit
BaseQuantities - GrossArea: 62.8658 m2; GrossVolume: 20.1171 m3; Perimeter: 39.04 m; Width: 0.32 m
Autre - Catégorie: Sols; Famille: Sol: Plancher espace nuit; Famille et type: Sol: Plancher espace nuit; ID du type: Sol: Plancher espace nuit; Type: Sol: Plancher espace nuit
Contraintes - Lié au volume: no; Limite de pièce: yes; Décalage par rapport au niveau: 0 m; Niveau: Niveau: RDC
Cotes - Elévation en haut: 0 m; Elévation à la base: -0.32 m; Elévation au niveau du noyau inférieur: -0.32 m; Elévation au niveau du noyau supérieur: -0.12 m; Epaisseur: 0.32 m; Périmètre: 39.04 m; Surface: 62.8658 m2; Volume: 20.1171 m3
Phase de construction - Phase de création: Nouvelle construction
Structure - Activer le modèle analytique: yes; Enrobage d'armature - Autres faces: Paramètres de l'enrobage d'armature: Enrobage d'armature 1; Structure: yes; Enrobage d'armature - Face inférieure: Paramètres de l'enrobage d'armature: Enrobage d'armature 1; Enrobage d'armature - Face supérieure: Paramètres de l'enrobage d'armature: Enrobage d'armature 1
Autre(Type) - Catégorie: Sols; Nom de la famille: Sol
Construction(Type) - Fonction: Intérieur; Epaisseur par défaut: 0.32 m
Données d'identification(Type) - Nom du type: Plancher espace nuit
Graphismes(Type) - Couleur vue détail faible: 0
Matériaux et finitions(Type) - Matériau structurel: Maçonnerie - Béton
Propriétés analytiques(Type) - Rugosité: 3; Coefficient d'absorbance: 0.7

# IfcSlab: Sol:Plongeoir, Sol:Plongeoir:488221
In: RDC
PredefinedType: FLOOR; Material: Maçonnerie - Béton 0.05 m
Pset_SlabCommon - LoadBearing: no; IsExternal: no; PitchAngle: 0 deg; Reference: Plongeoir
BaseQuantities - GrossArea: 0.8 m2; GrossVolume: 0.04 m3; Perimeter: 4.8 m; Width: 0.05 m
Autre - Catégorie: Sols; Famille: Sol: Plongeoir; Famille et type: Sol: Plongeoir; ID du type: Sol: Plongeoir; Type: Sol: Plongeoir
Contraintes - Lié au volume: no; Limite de pièce: yes; Niveau: Niveau: RDC; Décalage par rapport au niveau: 0.33 m
Cotes - Elévation à la base: 0.28 m; Elévation en haut: 0.33 m; Epaisseur: 0.05 m; Périmètre: 4.8 m; Surface: 0.8 m2; Volume: 0.04 m3
Phase de construction - Phase de création: Nouvelle construction
Structure - Activer le modèle analytique: no; Structure: no
Autre(Type) - Catégorie: Sols; Nom de la famille: Sol
Construction(Type) - Fonction: Intérieur; Epaisseur par défaut: 0.05 m
Données d'identification(Type) - Nom du type: Plongeoir
Graphismes(Type) - Couleur vue détail faible: 0
Matériaux et finitions(Type) - Matériau structurel: Maçonnerie - Béton
Propriétés analytiques(Type) - Rugosité: 3; Coefficient d'absorbance: 0.7

# IfcSlab: Sol:S5 Plancher flottant habitable, Sol:S5 Plancher flottant habitable:267472
In: RDC
PredefinedType: FLOOR; Material: Parquet bois 0.02 m, Chape 0.05 m, Maçonnerie - Isolant 0.05 m, Maçonnerie - Béton 0.2 m
Pset_SlabCommon - LoadBearing: yes; IsExternal: no; PitchAngle: 0 deg; Reference: S5 Plancher flottant habitable
BaseQuantities - GrossArea: 112.155 m2; GrossVolume: 35.8897 m3; Perimeter: 49.21 m; Width: 0.32 m
Autre - Catégorie: Sols; Famille: Sol: S5 Plancher flottant habitable; Famille et type: Sol: S5 Plancher flottant habitable; ID du type: Sol: S5 Plancher flottant habitable; Type: Sol: S5 Plancher flottant habitable
Contraintes - Lié au volume: no; Limite de pièce: yes; Décalage par rapport au niveau: 0 m; Niveau: Niveau: RDC
Cotes - Elévation en haut: 0 m; Elévation à la base: -0.32 m; Elévation au niveau du noyau inférieur: -0.32 m; Elévation au niveau du noyau supérieur: -0.12 m; Epaisseur: 0.32 m; Périmètre: 49.21 m; Surface: 112.155 m2; Volume: 35.8897 m3
Phase de construction - Phase de création: Nouvelle construction
Structure - Activer le modèle analytique: yes; Enrobage d'armature - Autres faces: Paramètres de l'enrobage d'armature: Enrobage d'armature 1; Structure: yes; Enrobage d'armature - Face inférieure: Paramètres de l'enrobage d'armature: Enrobage d'armature 1; Enrobage d'armature - Face supérieure: Paramètres de l'enrobage d'armature: Enrobage d'armature 1
Autre(Type) - Catégorie: Sols; Nom de la famille: Sol
Construction(Type) - Fonction: Intérieur; Epaisseur par défaut: 0.32 m
Données d'identification(Type) - Nom du type: S5 Plancher flottant habitable
Graphismes(Type) - Couleur vue détail faible: 0
Matériaux et finitions(Type) - Matériau structurel: Maçonnerie - Béton
Propriétés analytiques(Type) - Rugosité: 3; Coefficient d'absorbance: 0.7

# IfcSlab: Sol:Sol acces garage graviers, Sol:Sol acces garage graviers:455402
In: RDC
PredefinedType: FLOOR; Material: Graviers blanc 0.08 m
Pset_SlabCommon - LoadBearing: no; IsExternal: no; PitchAngle: 0 deg; Reference: Sol acces garage graviers
BaseQuantities - GrossArea: 44.77 m2; GrossVolume: 3.5816 m3; Perimeter: 31.6 m; Width: 0.08 m
Autre - Catégorie: Sols; Famille: Sol: Sol acces garage graviers; Famille et type: Sol: Sol acces garage graviers; ID du type: Sol: Sol acces garage graviers; Type: Sol: Sol acces garage graviers
Contraintes - Lié au volume: no; Limite de pièce: yes; Niveau: Niveau: RDC; Décalage par rapport au niveau: -0.12 m
Cotes - Elévation à la base: -0.2 m; Elévation en haut: -0.12 m; Epaisseur: 0.08 m; Périmètre: 31.6 m; Surface: 44.77 m2; Volume: 3.5816 m3
Phase de construction - Phase de création: Nouvelle construction
Structure - Activer le modèle analytique: no; Structure: no
Autre(Type) - Catégorie: Sols; Nom de la famille: Sol
Construction(Type) - Fonction: Intérieur; Epaisseur par défaut: 0.08 m
Données d'identification(Type) - Nom du type: Sol acces garage graviers
Graphismes(Type) - Couleur vue détail faible: 0
Propriétés analytiques(Type) - Rugosité: 3; Coefficient d'absorbance: 0.7

# IfcSlab: Sol:Surface eau, Sol:Surface eau:473320
In: RDC
PredefinedType: FLOOR; Material: Verre 0.01 m
Pset_SlabCommon - LoadBearing: no; IsExternal: no; PitchAngle: 0 deg; Reference: Surface eau; ThermalTransmittance: 110 kg/K/s3
BaseQuantities - GrossArea: 35.2395 m2; GrossVolume: 0.352395 m3; Perimeter: 25.39 m; Width: 0.01 m
Autre - Catégorie: Sols; Famille: Sol: Surface eau; Famille et type: Sol: Surface eau; ID du type: Sol: Surface eau; Type: Sol: Surface eau
Contraintes - Lié au volume: no; Limite de pièce: yes; Niveau: Niveau: RDC; Décalage par rapport au niveau: -0.3 m
Cotes - Elévation à la base: -0.31 m; Elévation en haut: -0.3 m; Epaisseur: 0.01 m; Périmètre: 25.39 m; Surface: 35.2395 m2; Volume: 0.352395 m3
Phase de construction - Phase de création: Nouvelle construction
Structure - Activer le modèle analytique: no; Structure: no
Autre(Type) - Catégorie: Sols; Nom de la famille: Sol
Construction(Type) - Fonction: Intérieur; Epaisseur par défaut: 0.01 m
Données d'identification(Type) - Nom du type: Surface eau
Graphismes(Type) - Couleur vue détail faible: 0
Matériaux et finitions(Type) - Matériau structurel: Verre
Propriétés analytiques(Type) - Rugosité: 3; Coefficient d'absorbance: 0.7; Coefficient de transfert de chaleur (U): 110; Masse thermique: 20832; Résistance thermique (R): 0.00909091

# IfcSlab: Sol:TT garage ba 20+ isol 6 + EPDM + pl 4 (2)
In: 1er ETAGE
PredefinedType: FLOOR; Material: Protection lourde 0.04 m, Toiture, membrane EPDM 0.002 m, Maçonnerie - Isolant 0.06 m, Maçonnerie - Béton 0.2 m
Pset_SlabCommon - LoadBearing: yes; IsExternal: no; PitchAngle: 0 deg; Reference: TT garage ba 20+ isol 6 + EPDM + pl 4; ThermalTransmittance: 7.96154 kg/K/s3
BaseQuantities - Width: 0.302 m
Autre - Catégorie: Sols; Famille: Sol: TT garage ba 20+ isol 6 + EPDM + pl 4; Famille et type: Sol: TT garage ba 20+ isol 6 + EPDM + pl 4; ID du type: Sol: TT garage ba 20+ isol 6 + EPDM + pl 4; Type: Sol: TT garage ba 20+ isol 6 + EPDM + pl 4
Contraintes - Lié au volume: no; Limite de pièce: yes; Niveau: Niveau: 1er ETAGE; Décalage par rapport au niveau: 0.282 m
Cotes - Elévation à la base: 2.98 m; Elévation au niveau du noyau inférieur: 2.98 m; Elévation au niveau du noyau supérieur: 3.18 m; Elévation en haut: 3.282 m; Epaisseur: 0.302 m
Phase de construction - Phase de création: Nouvelle construction
Structure - Activer le modèle analytique: yes; Enrobage d'armature - Autres faces: Paramètres de l'enrobage d'armature: Enrobage d'armature 1; Structure: yes; Enrobage d'armature - Face inférieure: Paramètres de l'enrobage d'armature: Enrobage d'armature 1; Enrobage d'armature - Face supérieure: Paramètres de l'enrobage d'armature: Enrobage d'armature 1
Autre(Type) - Catégorie: Sols; Nom de la famille: Sol
Construction(Type) - Fonction: Intérieur; Epaisseur par défaut: 0.302 m
Données d'identification(Type) - Nom du type: TT garage ba 20+ isol 6 + EPDM + pl 4
Graphismes(Type) - Couleur vue détail faible: 0
Matériaux et finitions(Type) - Matériau structurel: Maçonnerie - Béton
Propriétés analytiques(Type) - Rugosité: 3; Coefficient d'absorbance: 0.7; Coefficient de transfert de chaleur (U): 7.96154; Masse thermique: 65715.1; Résistance thermique (R): 0.125604
Name (Sol:TT garage ba 20+ isol 6 + EPDM + pl 4:...) | GrossArea (m2) = Surface (m2) | GrossVolume (m3) = Volume (m3) | Perimeter (m) = Périmètre (m)
333215 | 54.42 | 16.4348 | 30.14
358603 | 3.01 | 0.90902 | 7.1

# IfcSlab: Sol:TT nuit ba 20+ isol 6 +dr 5 + géot + terre 15, Sol:TT nuit ba 20+ isol 6 +dr 5 + géot + terre 15:333340
In: 1er ETAGE
PredefinedType: FLOOR; Material: Herbe 0.01 m, Terre 0.14 m, Géotextile 0.001 m, Couche drainante 0.05 m, Toiture, membrane EPDM 0.002 m, Maçonnerie - Isolant 0.06 m, Maçonnerie - Béton 0.2 m
Pset_SlabCommon - LoadBearing: yes; IsExternal: no; PitchAngle: 0 deg; Reference: TT nuit ba 20+ isol 6 +dr 5 + géot + terre 15; ThermalTransmittance: 5.50186 kg/K/s3
BaseQuantities - GrossArea: 53.0782 m2; GrossVolume: 24.5752 m3; Perimeter: 33.14 m; Width: 0.463 m
Autre - Catégorie: Sols; Famille: Sol: TT nuit ba 20+ isol 6 +dr 5 + géot + terre 15; Famille et type: Sol: TT nuit ba 20+ isol 6 +dr 5 + géot + terre 15; ID du type: Sol: TT nuit ba 20+ isol 6 +dr 5 + géot + terre 15; Type: Sol: TT nuit ba 20+ isol 6 +dr 5 + géot + terre 15
Contraintes - Lié au volume: no; Limite de pièce: yes; Niveau: Niveau: 1er ETAGE; Décalage par rapport au niveau: 0.463 m
Cotes - Elévation à la base: 3 m; Elévation au niveau du noyau inférieur: 3 m; Elévation au niveau du noyau supérieur: 3.2 m; Elévation en haut: 3.463 m; Epaisseur: 0.463 m; Périmètre: 33.14 m; Surface: 53.0782 m2; Volume: 24.5752 m3
Phase de construction - Phase de création: Nouvelle construction
Structure - Activer le modèle analytique: yes; Enrobage d'armature - Autres faces: Paramètres de l'enrobage d'armature: Enrobage d'armature 1; Structure: yes; Enrobage d'armature - Face inférieure: Paramètres de l'enrobage d'armature: Enrobage d'armature 1; Enrobage d'armature - Face supérieure: Paramètres de l'enrobage d'armature: Enrobage d'armature 1
Autre(Type) - Catégorie: Sols; Nom de la famille: Sol
Construction(Type) - Fonction: Intérieur; Epaisseur par défaut: 0.463 m
Données d'identification(Type) - Nom du type: TT nuit ba 20+ isol 6 +dr 5 + géot + terre 15
Graphismes(Type) - Couleur vue détail faible: 0
Matériaux et finitions(Type) - Matériau structurel: Maçonnerie - Béton
Propriétés analytiques(Type) - Rugosité: 3; Coefficient d'absorbance: 0.7; Coefficient de transfert de chaleur (U): 5.50186; Masse thermique: 194263; Résistance thermique (R): 0.181757

# IfcSlab: Sol:Tapis, Sol:Tapis:550818
In: 1er ETAGE
PredefinedType: FLOOR; Material: Tapis beige 0.02 m
Pset_SlabCommon - LoadBearing: no; IsExternal: no; PitchAngle: 0 deg; Reference: Tapis
BaseQuantities - GrossArea: 4.085 m2; GrossVolume: 0.0817 m3; Perimeter: 8.1 m; Width: 0.02 m
Autre - Catégorie: Sols; Famille: Sol: Tapis; Famille et type: Sol: Tapis; ID du type: Sol: Tapis; Type: Sol: Tapis
Contraintes - Lié au volume: no; Limite de pièce: yes; Niveau: Niveau: 1er ETAGE; Décalage par rapport au niveau: 0.0642298 m
Cotes - Elévation à la base: 3.04423 m; Elévation en haut: 3.06423 m; Epaisseur: 0.02 m; Périmètre: 8.1 m; Surface: 4.085 m2; Volume: 0.0817 m3
Phase de construction - Phase de création: Nouvelle construction
Structure - Activer le modèle analytique: no; Structure: no
Autre(Type) - Catégorie: Sols; Nom de la famille: Sol
Construction(Type) - Fonction: Intérieur; Epaisseur par défaut: 0.02 m
Données d'identification(Type) - Nom du type: Tapis
Graphismes(Type) - Couleur vue détail faible: 0
Matériaux et finitions(Type) - Matériau structurel: Tapis beige
Propriétés analytiques(Type) - Rugosité: 3; Coefficient d'absorbance: 0.7

# IfcSlab: Sol:Terrasse bois, Sol:Terrasse bois:475692
In: RDC
PredefinedType: FLOOR; Material: Bois - Chêne 0.1 m
Pset_SlabCommon - IsExternal: yes; LoadBearing: no; Reference: Terrasse bois
BaseQuantities - GrossArea: 105.194 m2; Perimeter: 41.7986 m
Autre - Catégorie: Sols; Famille: Sol: Terrasse bois; Famille et type: Sol: Terrasse bois; ID du type: Sol: Terrasse bois; Type: Sol: Terrasse bois
Contraintes - Lié au volume: no; Limite de pièce: yes; Niveau: Niveau: RDC; Décalage par rapport au niveau: -0.07 m
Cotes - Elévation à la base: -0.17 m; Elévation en haut: -0.07 m; Epaisseur: 0.1 m; Périmètre: 67.1886 m; Surface: 69.9543 m2; Volume: 6.99543 m3
Phase de construction - Phase de création: Nouvelle construction
Structure - Activer le modèle analytique: no; Structure: no
Autre(Type) - Catégorie: Sols; Nom de la famille: Sol
Construction(Type) - Fonction: Extérieur; Epaisseur par défaut: 0.1 m
Données d'identification(Type) - Nom du type: Terrasse bois
Graphismes(Type) - Couleur vue détail faible: 0
Matériaux et finitions(Type) - Matériau structurel: Bois - Chêne
Propriétés analytiques(Type) - Rugosité: 3; Coefficient d'absorbance: 0.7

# IfcSlab: Terre-plein:Terre - plein terre 1 cm (5)
PredefinedType: FLOOR; Material: Terre 0.01 m
Pset_SlabCommon - IsExternal: no; Reference: Terre - plein terre 1 cm; ThermalTransmittance: 83.7 kg/K/s3
Autre - Catégorie: Terre-plein; Famille: Terre-plein: Terre - plein terre 1 cm; Famille et type: Terre-plein: Terre - plein terre 1 cm; ID du type: Terre-plein: Terre - plein terre 1 cm; Type: Terre-plein: Terre - plein terre 1 cm
Contraintes - Limite de pièce: yes
Phase de construction - Phase de création: Nouvelle construction
Autre(Type) - Catégorie: Terre-plein; Nom de la famille: Terre-plein
Construction(Type) - Epaisseur: 0.01 m
Données d'identification(Type) - Nom du type: Terre - plein terre 1 cm
Graphismes(Type) - Couleur vue détail faible: 0
Propriétés analytiques(Type) - Rugosité: 3; Coefficient d'absorbance: 0.7; Coefficient de transfert de chaleur (U): 83.7; Masse thermique: 13598; Résistance thermique (R): 0.0119474
Name (Terre-plein:Terre - plein terre 1 cm:...) | In | Niveau | Décalage par rapport au niveau (m) | Périmètre (m) | Surface (m2) | Volume (m3)
367192 | 1 Mur de soubassement | Niveau: 1 Mur de soubassement | 0.01 | 33.1381 | 53.0669 | 0.530669
367269 | 1 Mur de soubassement | Niveau: 1 Mur de soubassement | 0.01 | 6.30185 | 2.15093 | 0.0215093
367340 | 1 Mur de soubassement | Niveau: 1 Mur de soubassement | 0.01 | 47.6322 | 102.49 | 1.0249
455839 | RDC | Niveau: RDC | -0.2 | 31.6 | 44.77 | 0.4477
470616 | RDC | Niveau: RDC | -2.2 | 27 | 40.5 | 0.405

# IfcSlab: Toit de base:Panneau toiture (2)
In: 1er Chainage
PredefinedType: ROOF; Material: Tuiles 0.05 m, Bois - Bois de construction de dimensions courantes 0.02 m, Laine de roche 0.2 m, Bois - Bois de construction de dimensions courantes 0.02 m
Pset_SlabCommon - IsExternal: yes; Reference: Panneau toiture; PitchAngle: 19.29 deg
BaseQuantities - GrossArea: 6.84672 m2; GrossVolume: 1.98555 m3; Perimeter: 39.5591 m; Width: 0.29 m

# IfcStair: Escalier:Monobloc:28673, Escalier:Monobloc:317402
In: RDC
Pset_StairCommon - IsExternal: no; Reference: Monobloc; NumberOfRiser: 17; NumberOfTreads: 17; RiserHeight: 0.178824 m; TreadLength: 0.272353 m
Autre - Catégorie: Escalier; Famille: Escalier: Monobloc; Famille et type: Escalier: Monobloc; ID du type: Escalier: Monobloc; Type: Escalier: Monobloc
Contraintes - Décalage inférieur: 0 m; Décalage supérieur: 0.04 m; Niveau de base: Niveau: RDC; Niveau supérieur: Niveau: 1er ETAGE
Cotes - Hauteur actuelle de la contremarche: 0.178824 m; Largeur: 1 m; Nombre de contremarches souhaité: 17; Nombre réel de contremarches: 17; Profondeur actuelle du giron: 0.272353 m
Graphismes - Afficher la flèche Haut dans toutes les vues: no; Flèche Bas: no; Flèche Haut: yes; Libellé Bas: no; Libellé Haut: no; Texte Bas: Base; Texte Haut: Plateau
Phase de construction - Phase de création: Nouvelle construction
Structure - Enrobage d'armature: Paramètres de l'enrobage d'armature: Enrobage d'armature 1
Autre(Type) - Catégorie: Escalier; Nom de la famille: Escalier
Construction(Type) - Fonction: Intérieur; Décalage du niveau de départ: 0 m; Dessous de paillasse: Lissé; Escalier monobloc: yes; Raccord marche palière: 0.076 m
Contremarches(Type) - Connexion Marche Contremarche: Marche dessous la contremarche; Débuter avec contremarche: yes; Epaisseur de la contremarche: 0 m; Finir avec contremarche: no; Type de contremarche: Droit
Données d'identification(Type) - Nom du type: Monobloc
Graphismes(Type) - Police de texte: Arial; Symbole de coupure en plan: yes; Taille du texte: 0.0082021
Limons à la française(Type) - Ajuster les limons à la française en haut: Correspondance au niveau; Décalage du limon à la française apparent: 0.05 m; Epaisseur des limons à la française: 0.05 m; Hauteur des limons à la française: 0.27 m; Hauteur du limon à crémaillère: 0.08 m; Hauteur palier intermédiaire: 0.15 m; Limon à la française droit: Aucun(e); Limon à la française gauche: Aucun(e); Limons à la française centraux: 0
Marches(Type) - Appliquer un nez de marche: Devant seulement; Epaisseur de la marche: 0 m; Longueur du nez de marche: 0 m
Matériaux et finitions(Type) - Matériau monobloc: Maçonnerie - Béton
Règles de calcul(Type) - Hauteur maximum de la contremarche: 0.19 m; Profondeur de marche minimale: 0.23 m

# IfcStairFlight: Escalier:Monobloc:28673, Escalier:Monobloc:317402:1
In: RDC
NumberOfRiser: 9; NumberOfTreads: 8; RiserHeight: 0.586691 m; TreadLength: 0.945292 m; Material: Maçonnerie - Béton
Pset_StairFlightCommon - Reference: Monobloc; NumberOfRiser: 17; NumberOfTreads: 17; RiserHeight: 0.178824 m; TreadLength: 0.272353 m; TreadLengthAtOffset: 0.272353 m; NosingLength: 0.272353 m; WalkingLineOffset: 0.5 m; WaistThickness: 1 m

# IfcWallStandardCase: Mur de base:Acrotère Nuit Ext. Bois 2 +Isolant 12 + BBMC 20 + EPDM (4)
In: RDC Acrotère
Type - PredefinedType: STANDARD; Material: Bardage bois 0.01 m, Maçonnerie - Isolant 0.12 m, Blocs béton manufacturés 0.2 m, Toiture, membrane EPDM 0.002 m
Type - Autre(Type) - Catégorie: Murs; Nom de la famille: Mur de base
Type - Construction(Type) - Fonction: Extérieur; Retournement aux extrémités: Aucun(e); Retournement aux insertions: Les deux; Largeur: 0.332 m
Type - Données d'identification(Type) - Commentaires du type: Ext. Parpaing 20 + Isolant 10; Nom du type: Acrotère Nuit Ext. Bois 2 +Isolant 12 + BBMC 20 + EPDM
Type - Graphismes(Type) - Couleur vue détail faible: 0
Type - Matériaux et finitions(Type) - Matériau structurel: Blocs béton manufacturés
Type - Propriétés analytiques(Type) - Rugosité: 3; Coefficient d'absorbance: 0.7; Coefficient de transfert de chaleur (U): 4.46639; Masse thermique: 317336; Résistance thermique (R): 0.223894
BaseQuantities - Height: 0.6 m; Width: 0.332 m
Autre - Catégorie: Murs; Famille: Mur de base: Acrotère Nuit Ext. Bois 2 +Isolant 12 + BBMC 20 + EPDM; Famille et type: Mur de base: Acrotère Nuit Ext. Bois 2 +Isolant 12 + BBMC 20 + EPDM; ID du type: Mur de base: Acrotère Nuit Ext. Bois 2 +Isolant 12 + BBMC 20 + EPDM; Type: Mur de base: Acrotère Nuit Ext. Bois 2 +Isolant 12 + BBMC 20 + EPDM
Contraintes - Décalage inférieur: 0 m; Décalage supérieur: 0 m; Extension inférieure: 0 m; Extension supérieure: 0 m; Lié au volume: no; Ligne de justification: Nu fini: Extérieur; Limite de pièce: yes; Partie inférieure attachée: no; Partie supérieure attachée: no; Contrainte inférieure: Niveau: RDC Acrotère; Hauteur non contrainte: 0.6 m
Données d'identification - Commentaires: porteur
Phase de construction - Phase de création: Nouvelle construction
Structure - Activer le modèle analytique: yes; Enrobage d'armature - Autres faces: Paramètres de l'enrobage d'armature: Enrobage d'armature 1; Enrobage d'armature - Face extérieure: Paramètres de l'enrobage d'armature: Enrobage d'armature 1; Enrobage d'armature - Face intérieure: Paramètres de l'enrobage d'armature: Enrobage d'armature 1; Structure: yes; Utilisation structurelle: Porteur
Pset_WallCommon - LoadBearing: yes; ExtendToStructure: no; IsExternal: yes; Reference: Acrotère Nuit Ext. Bois 2 +Isolant 12 + BBMC 20 + EPDM; ThermalTransmittance: 4.46639 kg/K/s3
Nomenclature de mur - Famille: Mur de base: Acrotère Nuit Ext. Bois 2 +Isolant 12 + BBMC 20 + EPDM; Famille et type: Mur de base: Acrotère Nuit Ext. Bois 2 +Isolant 12 + BBMC 20 + EPDM; Matériau structurel: Blocs béton manufacturés; Largeur: 0.332 m; Commentaires: porteur
Relevé de matériaux de mur détaillé - Famille et type: Mur de base: Acrotère Nuit Ext. Bois 2 +Isolant 12 + BBMC 20 + EPDM; sets with these values: 2
Name (Mur de base:Acrotère Nuit Ext. Bois 2 +Isolant 12 + BBMC 20 + EPDM:...) | Length (m) = Cotes, Longueur (m) = Nomenclature de mur, Longueur (m) | GrossFootprintArea (m2) | GrossSideArea (m2) = Cotes, Surface (m2) = Nomenclature de mur, Surface (m2) | GrossVolume (m3) = Cotes, Volume (m3) = Nomenclature de mur, Volume (m3)
335336 | 4.668 | 1.54978 | 2.8008 | 0.929866
335338 | 12.558 | 4.16926 | 7.5348 | 2.50155
335340 | 4.668 | 1.54978 | 2.8008 | 0.929866
335342 | 12.558 | 4.16926 | 7.5348 | 2.50155

# IfcWallStandardCase: Mur de base:Acrotère garage Ext. Crépis 2 + BBMC 20 + EPDM (7)
In: RDC Acrotère
Type - PredefinedType: STANDARD; Material: Maçonnerie - Enduit 0.02 m, Blocs béton manufacturés 0.2 m, Toiture, membrane EPDM 0.002 m
Type - Autre(Type) - Catégorie: Murs; Nom de la famille: Mur de base
Type - Construction(Type) - Fonction: Extérieur; Retournement aux extrémités: Aucun(e); Retournement aux insertions: Les deux; Largeur: 0.222 m
Type - Données d'identification(Type) - Commentaires du type: Ext. Parpaing 20 + Isolant 10; Nom du type: Acrotère garage Ext. Crépis 2 + BBMC 20 + EPDM
Type - Graphismes(Type) - Couleur vue détail faible: 0
Type - Matériaux et finitions(Type) - Matériau structurel: Blocs béton manufacturés
Type - Propriétés analytiques(Type) - Rugosité: 3; Coefficient d'absorbance: 0.7; Coefficient de transfert de chaleur (U): 4.83558; Masse thermique: 326451; Résistance thermique (R): 0.2068
BaseQuantities - Width: 0.222 m
Autre - Catégorie: Murs; Famille: Mur de base: Acrotère garage Ext. Crépis 2 + BBMC 20 + EPDM; Famille et type: Mur de base: Acrotère garage Ext. Crépis 2 + BBMC 20 + EPDM; ID du type: Mur de base: Acrotère garage Ext. Crépis 2 + BBMC 20 + EPDM; Type: Mur de base: Acrotère garage Ext. Crépis 2 + BBMC 20 + EPDM
Contraintes - Extension inférieure: 0 m; Extension supérieure: 0 m; Lié au volume: no; Ligne de justification: Nu fini: Extérieur; Limite de pièce: yes; Partie inférieure attachée: no; Partie supérieure attachée: no; Contrainte inférieure: Niveau: RDC Acrotère
Phase de construction - Phase de création: Nouvelle construction
Structure - Activer le modèle analytique: yes; Enrobage d'armature - Autres faces: Paramètres de l'enrobage d'armature: Enrobage d'armature 1; Enrobage d'armature - Face extérieure: Paramètres de l'enrobage d'armature: Enrobage d'armature 1; Enrobage d'armature - Face intérieure: Paramètres de l'enrobage d'armature: Enrobage d'armature 1; Structure: yes; Utilisation structurelle: Porteur
Pset_WallCommon - LoadBearing: yes; ExtendToStructure: no; IsExternal: yes; Reference: Acrotère garage Ext. Crépis 2 + BBMC 20 + EPDM; ThermalTransmittance: 4.83558 kg/K/s3
Relevé de matériaux de mur détaillé - Famille et type: Mur de base: Acrotère garage Ext. Crépis 2 + BBMC 20 + EPDM; sets with these values: 2
Name (Mur de base:Acrotère garage Ext. Crépis 2 + BBMC 20 + EPDM:...) | Height (m) = Hauteur non contrainte (m) | Length (m) | GrossFootprintArea (m2) | GrossSideArea (m2) = Cotes, Surface (m2) | GrossVolume (m3) = Cotes, Volume (m3) | Décalage supérieur (m) | Décalage inférieur (m) | Cotes, Longueur (m)
334379 | 0.2 | 5.98 | 1.32756 | 1.196 | 0.265512 | 0 | -0.2 | 6.255 | Contraintes - Contrainte supérieure: Niveau: RDC Acrotère
334771 | 0.4 | 6.2 | 1.3764 | 2.48 | 0.55056 | 0 | 0 | 6.254 | Données d'identification - Commentaires: porteur; Nomenclature de mur - Famille: Mur de base: Acrotère garage Ext. Crépis 2 + BBMC 20 + EPDM; Famille et type: Mur de base: Acrotère garage Ext. Crépis 2 + BBMC 20 + EPDM; Matériau structurel: Blocs béton manufacturés; Longueur: 6.254 m; Largeur: 0.222 m; Surface: 2.48 m2; Volume: 0.55056 m3; Commentaires: porteur
335004 | 0.4 | 9.288 | 2.06194 | 3.7152 | 0.824774 | 0 | 0 | 9.288 | Données d'identification - Commentaires: porteur; Nomenclature de mur - Famille: Mur de base: Acrotère garage Ext. Crépis 2 + BBMC 20 + EPDM; Famille et type: Mur de base: Acrotère garage Ext. Crépis 2 + BBMC 20 + EPDM; Matériau structurel: Blocs béton manufacturés; Longueur: 9.288 m; Largeur: 0.222 m; Surface: 3.7152 m2; Volume: 0.824774 m3; Commentaires: porteur
335112 | 0.4 | 6.218 | 1.3804 | 2.4872 | 0.552158 | 0 | 0 | 6.218
335167 | 0.4 | 4.268 | 0.947496 | 1.7072 | 0.378998 | 0 | 0 | 4.544
359139 | 0.6 | 2 | 0.444 | 1.2 | 0.233459 | -0.32 | 0 | 2.33
359385 | 0.6 | 2 | 0.444 | 1.2 | 0.233452 | -0.32 | 0 | 2.33

# IfcWallStandardCase: Mur de base:BA 13 (3)
In: RDC Faux Plafond
Type - PredefinedType: STANDARD; Material: Plâtre 0.013 m
Type - Autre(Type) - Catégorie: Murs; Nom de la famille: Mur de base
Type - Construction(Type) - Fonction: Extérieur; Retournement aux extrémités: Aucun(e); Retournement aux insertions: Les deux; Largeur: 0.013 m
Type - Données d'identification(Type) - Commentaires du type: Ext. Parpaing 20 + Isolant 10; Nom du type: BA 13
Type - Graphismes(Type) - Couleur vue détail faible: 0
Type - Propriétés analytiques(Type) - Rugosité: 3; Coefficient d'absorbance: 0.7
BaseQuantities - Width: 0.013 m
Autre - Catégorie: Murs; Famille: Mur de base: BA 13; Famille et type: Mur de base: BA 13; ID du type: Mur de base: BA 13; Type: Mur de base: BA 13
Contraintes - Décalage inférieur: 0 m; Extension inférieure: 0 m; Extension supérieure: 0 m; Lié au volume: no; Limite de pièce: yes; Partie inférieure attachée: no; Partie supérieure attachée: no; Contrainte inférieure: Niveau: RDC Faux Plafond
Phase de construction - Phase de création: Nouvelle construction
Structure - Activer le modèle analytique: no; Structure: no; Utilisation structurelle: Non porteur
Pset_WallCommon - ExtendToStructure: no; IsExternal: yes; LoadBearing: no; Reference: BA 13
Relevé de matériaux de mur détaillé - Famille et type: Mur de base: BA 13; sets with these values: 2
Name (Mur de base:BA 13:...) | Height (m) = Hauteur non contrainte (m) | Length (m) | GrossFootprintArea (m2) | GrossSideArea (m2) = Surface (m2) | GrossVolume (m3) = Volume (m3) | Décalage supérieur (m) | Ligne de justification | Contrainte supérieure | Longueur (m)
444498 | 0.5 | 14.415 | 0.187395 | 7.2075 | 0.0936975 | 0 | Nu fini: Extérieur | Niveau: 1er ETAGE | 14.615
444637 | 0.541338 | 14.415 | 0.187395 | 7.79202 | 0.101296 | 0.0413381 | Nu fini: Extérieur | Niveau: 1er ETAGE | 14.615
530706 | 0.5 | 2.18 | 0.02834 | 1.09 | 0.01417 | 0 | Axe du mur |  | 2.18

# IfcWallStandardCase: Mur de base:Crépis 2 cm (2)
In: 1er ETAGE
Type - PredefinedType: STANDARD; Material: Maçonnerie - Enduit 0.02 m
Type - Autre(Type) - Catégorie: Murs; Nom de la famille: Mur de base
Type - Construction(Type) - Fonction: Extérieur; Retournement aux extrémités: Aucun(e); Retournement aux insertions: Les deux; Largeur: 0.02 m
Type - Données d'identification(Type) - Commentaires du type: Ext. Parpaing 20 + Isolant 10; Nom du type: Crépis 2 cm
Type - Graphismes(Type) - Couleur vue détail faible: 0
Type - Propriétés analytiques(Type) - Rugosité: 3; Coefficient d'absorbance: 0.7; Coefficient de transfert de chaleur (U): 26; Masse thermique: 20160; Résistance thermique (R): 0.0384615
BaseQuantities - Height: 0.2 m; Length: 2 m; Width: 0.02 m; GrossFootprintArea: 0.04 m2; GrossSideArea: 0.4 m2; GrossVolume: 0.008 m3
Autre - Catégorie: Murs; Famille: Mur de base: Crépis 2 cm; Famille et type: Mur de base: Crépis 2 cm; ID du type: Mur de base: Crépis 2 cm; Type: Mur de base: Crépis 2 cm
Contraintes - Décalage inférieur: 0 m; Décalage supérieur: 0 m; Extension inférieure: 0 m; Extension supérieure: 0 m; Lié au volume: no; Ligne de justification: Nu fini: Extérieur; Limite de pièce: yes; Partie inférieure attachée: no; Partie supérieure attachée: no; Contrainte inférieure: Niveau: 1er ETAGE; Contrainte supérieure: Niveau: RDC Acrotère; Hauteur non contrainte: 0.2 m
Cotes - Longueur: 2.33 m; Surface: 0.4 m2; Volume: 0.008 m3
Phase de construction - Phase de création: Nouvelle construction
Structure - Activer le modèle analytique: no; Structure: no; Utilisation structurelle: Non porteur
Pset_WallCommon - ExtendToStructure: no; IsExternal: yes; LoadBearing: no; Reference: Crépis 2 cm; ThermalTransmittance: 26 kg/K/s3
Relevé de matériaux de mur détaillé - Famille et type: Mur de base: Crépis 2 cm; sets with these values: 2
Name (Mur de base:Crépis 2 cm:...)
360186
360307

# IfcWallStandardCase: Mur de base:Ext. Bois 2 +Isolant 12 + BA 20 (4)
In: 1er ETAGE
Type - PredefinedType: STANDARD; Material: Bardage bois 0.01 m, Maçonnerie - Isolant 0.12 m, Béton, coulé sur place 0.2 m
Type - Autre(Type) - Catégorie: Murs; Nom de la famille: Mur de base
Type - Construction(Type) - Fonction: Extérieur; Retournement aux extrémités: Aucun(e); Retournement aux insertions: Les deux; Largeur: 0.33 m
Type - Données d'identification(Type) - Commentaires du type: Ext. Parpaing 20 + Isolant 10; Nom du type: Ext. Bois 2 +Isolant 12 + BA 20
Type - Graphismes(Type) - Couleur vue détail faible: 0
Type - Matériaux et finitions(Type) - Matériau structurel: Béton, coulé sur place
Type - Propriétés analytiques(Type) - Rugosité: 3; Coefficient d'absorbance: 0.7; Coefficient de transfert de chaleur (U): 4.05252; Masse thermique: 313265; Résistance thermique (R): 0.24676
BaseQuantities - Height: 0.2 m; Width: 0.33 m
Autre - Catégorie: Murs; Famille: Mur de base: Ext. Bois 2 +Isolant 12 + BA 20; Famille et type: Mur de base: Ext. Bois 2 +Isolant 12 + BA 20; ID du type: Mur de base: Ext. Bois 2 +Isolant 12 + BA 20; Type: Mur de base: Ext. Bois 2 +Isolant 12 + BA 20
Contraintes - Décalage inférieur: 0 m; Décalage supérieur: 0 m; Extension inférieure: 0 m; Extension supérieure: 0 m; Lié au volume: no; Ligne de justification: Nu fini: Extérieur; Limite de pièce: yes; Partie inférieure attachée: no; Partie supérieure attachée: no; Contrainte inférieure: Niveau: 1er ETAGE; Hauteur non contrainte: 0.2 m
Phase de construction - Phase de création: Nouvelle construction
Structure - Activer le modèle analytique: yes; Enrobage d'armature - Autres faces: Paramètres de l'enrobage d'armature: Enrobage d'armature 1; Enrobage d'armature - Face extérieure: Paramètres de l'enrobage d'armature: Enrobage d'armature 1; Enrobage d'armature - Face intérieure: Paramètres de l'enrobage d'armature: Enrobage d'armature 1; Structure: yes; Utilisation structurelle: Porteur
Pset_WallCommon - LoadBearing: yes; ExtendToStructure: no; IsExternal: yes; Reference: Ext. Bois 2 +Isolant 12 + BA 20; ThermalTransmittance: 4.05252 kg/K/s3
Relevé de matériaux de mur détaillé - Famille et type: Mur de base: Ext. Bois 2 +Isolant 12 + BA 20; sets with these values: 2
Name (Mur de base:Ext. Bois 2 +Isolant 12 + BA 20:...) | Length (m) | GrossFootprintArea (m2) | GrossSideArea (m2) = Surface (m2) | GrossVolume (m3) = Volume (m3) | Longueur (m)
332014 | 5 | 1.65 | 1 | 0.33 | 4.67
332231 | 12.56 | 4.1448 | 2.512 | 0.82896 | 12.56
332330 | 4.67 | 1.5411 | 0.934 | 0.30822 | 4.67
332481 | 12.23 | 4.0359 | 2.446 | 0.80718 | 12.56

# IfcWallStandardCase: Mur de base:Ext. Crépis 2 + BBMC 20 (6)
In: 1 Mur de soubassement
Type - PredefinedType: STANDARD; Material: Maçonnerie - Enduit 0.02 m, Blocs béton manufacturés 0.2 m
Type - Autre(Type) - Catégorie: Murs; Nom de la famille: Mur de base
Type - Construction(Type) - Fonction: Extérieur; Retournement aux extrémités: Aucun(e); Retournement aux insertions: Les deux; Largeur: 0.22 m
Type - Données d'identification(Type) - Commentaires du type: Ext. Parpaing 20 + Isolant 10; Nom du type: Ext. Crépis 2 + BBMC 20
Type - Graphismes(Type) - Couleur vue détail faible: 0
Type - Matériaux et finitions(Type) - Matériau structurel: Blocs béton manufacturés
Type - Propriétés analytiques(Type) - Rugosité: 3; Coefficient d'absorbance: 0.7; Coefficient de transfert de chaleur (U): 5.2; Masse thermique: 322560; Résistance thermique (R): 0.192308
BaseQuantities - Width: 0.22 m
Autre - Catégorie: Murs; Famille: Mur de base: Ext. Crépis 2 + BBMC 20; Famille et type: Mur de base: Ext. Crépis 2 + BBMC 20; ID du type: Mur de base: Ext. Crépis 2 + BBMC 20; Type: Mur de base: Ext. Crépis 2 + BBMC 20
Contraintes - Décalage supérieur: 0 m; Extension inférieure: 0 m; Extension supérieure: 0 m; Lié au volume: no; Ligne de justification: Nu fini: Extérieur; Limite de pièce: yes; Partie inférieure attachée: no; Partie supérieure attachée: no; Contrainte inférieure: Niveau: 1 Mur de soubassement; Contrainte supérieure: Niveau: 1er ETAGE
Données d'identification - Commentaires: porteur
Phase de construction - Phase de création: Nouvelle construction
Structure - Activer le modèle analytique: yes; Enrobage d'armature - Autres faces: Paramètres de l'enrobage d'armature: Enrobage d'armature 1; Enrobage d'armature - Face extérieure: Paramètres de l'enrobage d'armature: Enrobage d'armature 1; Enrobage d'armature - Face intérieure: Paramètres de l'enrobage d'armature: Enrobage d'armature 1; Structure: yes; Utilisation structurelle: Porteur
Pset_WallCommon - LoadBearing: yes; ExtendToStructure: no; IsExternal: yes; Reference: Ext. Crépis 2 + BBMC 20; ThermalTransmittance: 5.2 kg/K/s3
Nomenclature de mur - Famille: Mur de base: Ext. Crépis 2 + BBMC 20; Famille et type: Mur de base: Ext. Crépis 2 + BBMC 20; Matériau structurel: Blocs béton manufacturés; Largeur: 0.22 m; Commentaires: porteur
Relevé de matériaux de mur détaillé - Famille et type: Mur de base: Ext. Crépis 2 + BBMC 20; sets with these values: 2
Name (Mur de base:Ext. Crépis 2 + BBMC 20:...) | Height (m) = Hauteur non contrainte (m) | Length (m) | GrossFootprintArea (m2) | GrossSideArea (m2) = Cotes, Surface (m2) = Nomenclature de mur, Surface (m2) | GrossVolume (m3) = Cotes, Volume (m3) = Nomenclature de mur, Volume (m3) | Décalage inférieur (m) | Cotes, Longueur (m) = Nomenclature de mur, Longueur (m)
244944 | 3.18934 | 6.53 | 1.4366 | 18.7718 | 4.10381 | 0.810658 | 6.255
245176 | 3.15 | 9.29 | 2.0438 | 29.2634 | 6.43796 | 0.85 | 9.29
245283 | 3.14693 | 6.22 | 1.3684 | 14.6745 | 3.22839 | 0.853071 | 6.22
246071 | 3 | 1.78 | 0.3916 | 5.34 | 1.1748 | 1 | 1.78
246147 | 3.1527 | 1.93 | 0.4246 | 5.48471 | 1.20664 | 0.847301 | 1.73
246604 | 3.15 | 4.25 | 0.935 | 13.3875 | 2.94525 | 0.85 | 4.195

# IfcWallStandardCase: Mur de base:Ext. Crépis 2 + Plan 5 + BA 15 + isol 11 (6)
Type - PredefinedType: STANDARD; Material: Maçonnerie - Enduit 0.02 m, Blocs béton manufacturés 0.05 m, Béton - Béton coulé sur place 0.15 m, Mur par défaut 0.01 m, Maçonnerie - Isolant 0.09 m, Finition Peinture - Blanc satiné 0.01 m
Type - Autre(Type) - Catégorie: Murs; Nom de la famille: Mur de base
Type - Construction(Type) - Fonction: Extérieur; Retournement aux extrémités: Aucun(e); Retournement aux insertions: Les deux; Largeur: 0.33 m
Type - Données d'identification(Type) - Commentaires du type: Ext. Parpaing 20 + Isolant 10; Nom du type: Ext. Crépis 2 + Plan 5 + BA 15 + isol 11
Type - Graphismes(Type) - Couleur vue détail faible: 0
Type - Matériaux et finitions(Type) - Matériau structurel: Béton - Béton coulé sur place
Type - Propriétés analytiques(Type) - Rugosité: 3; Coefficient d'absorbance: 0.7; Coefficient de transfert de chaleur (U): 13; Masse thermique: 95760; Résistance thermique (R): 0.0769231
BaseQuantities - Height: 0.2 m; Width: 0.33 m
Autre - Catégorie: Murs; Famille: Mur de base: Ext. Crépis 2 + Plan 5 + BA 15 + isol 11; Famille et type: Mur de base: Ext. Crépis 2 + Plan 5 + BA 15 + isol 11; ID du type: Mur de base: Ext. Crépis 2 + Plan 5 + BA 15 + isol 11; Type: Mur de base: Ext. Crépis 2 + Plan 5 + BA 15 + isol 11
Contraintes - Décalage inférieur: 0 m; Décalage supérieur: 0 m; Extension inférieure: 0 m; Extension supérieure: 0 m; Lié au volume: no; Ligne de justification: Nu fini: Extérieur; Limite de pièce: yes; Partie inférieure attachée: no; Partie supérieure attachée: no; Hauteur non contrainte: 0.2 m
Phase de construction - Phase de création: Nouvelle construction
Structure - Activer le modèle analytique: yes; Enrobage d'armature - Autres faces: Paramètres de l'enrobage d'armature: Enrobage d'armature 1; Enrobage d'armature - Face extérieure: Paramètres de l'enrobage d'armature: Enrobage d'armature 1; Enrobage d'armature - Face intérieure: Paramètres de l'enrobage d'armature: Enrobage d'armature 1; Structure: yes; Utilisation structurelle: Porteur
Pset_WallCommon - LoadBearing: yes; ExtendToStructure: no; IsExternal: yes; Reference: Ext. Crépis 2 + Plan 5 + BA 15 + isol 11; ThermalTransmittance: 13 kg/K/s3
Relevé de matériaux de mur détaillé - Famille et type: Mur de base: Ext. Crépis 2 + Plan 5 + BA 15 + isol 11; sets with these values: 2
Name (Mur de base:Ext. Crépis 2 + Plan 5 + BA 15 + isol 11:...) | In | Length (m) | GrossFootprintArea (m2) | GrossSideArea (m2) = Surface (m2) | GrossVolume (m3) = Volume (m3) | Contrainte inférieure | Longueur (m)
330821 | 1er Chainage | 14.47 | 4.7751 | 2.894 | 0.95502 | Niveau: 1er Chainage | 14.47
330823 | 1er Chainage | 8.07 | 2.6631 | 1.614 | 0.53262 | Niveau: 1er Chainage | 8.07
330825 | 1er Chainage | 14.47 | 4.7751 | 2.894 | 0.95502 | Niveau: 1er Chainage | 14.47
330827 | 1er Chainage | 8.07 | 2.6631 | 1.614 | 0.53262 | Niveau: 1er Chainage | 8.07
331247 | 1er ETAGE | 6.2 | 2.046 | 1.24 | 0.4092 | Niveau: 1er ETAGE | 6.255
331480 | 1er ETAGE | 6.22 | 2.0526 | 1.244 | 0.41052 | Niveau: 1er ETAGE | 6.22

# IfcWallStandardCase: Mur de base:Ext. Crépis 2 +plan 5 + BA 15 (2)
In: 1er ETAGE
Type - PredefinedType: STANDARD; Material: Maçonnerie - Enduit 0.02 m, Blocs béton manufacturés 0.2 m
Type - Autre(Type) - Catégorie: Murs; Nom de la famille: Mur de base
Type - Construction(Type) - Fonction: Extérieur; Retournement aux extrémités: Aucun(e); Retournement aux insertions: Les deux; Largeur: 0.22 m
Type - Données d'identification(Type) - Commentaires du type: Ext. Parpaing 20 + Isolant 10; Nom du type: Ext. Crépis 2 +plan 5 + BA 15
Type - Graphismes(Type) - Couleur vue détail faible: 0
Type - Matériaux et finitions(Type) - Matériau structurel: Blocs béton manufacturés
Type - Propriétés analytiques(Type) - Rugosité: 3; Coefficient d'absorbance: 0.7; Coefficient de transfert de chaleur (U): 5.2; Masse thermique: 322560; Résistance thermique (R): 0.192308
BaseQuantities - Height: 0.2 m; Width: 0.22 m
Autre - Catégorie: Murs; Famille: Mur de base: Ext. Crépis 2 +plan 5 + BA 15; Famille et type: Mur de base: Ext. Crépis 2 +plan 5 + BA 15; ID du type: Mur de base: Ext. Crépis 2 +plan 5 + BA 15; Type: Mur de base: Ext. Crépis 2 +plan 5 + BA 15
Contraintes - Décalage inférieur: 0 m; Décalage supérieur: 0 m; Extension inférieure: 0 m; Extension supérieure: 0 m; Lié au volume: no; Ligne de justification: Nu fini: Extérieur; Limite de pièce: yes; Partie inférieure attachée: no; Partie supérieure attachée: no; Contrainte inférieure: Niveau: 1er ETAGE; Hauteur non contrainte: 0.2 m
Phase de construction - Phase de création: Nouvelle construction
Structure - Activer le modèle analytique: yes; Enrobage d'armature - Autres faces: Paramètres de l'enrobage d'armature: Enrobage d'armature 1; Enrobage d'armature - Face extérieure: Paramètres de l'enrobage d'armature: Enrobage d'armature 1; Enrobage d'armature - Face intérieure: Paramètres de l'enrobage d'armature: Enrobage d'armature 1; Structure: yes; Utilisation structurelle: Porteur
Pset_WallCommon - LoadBearing: yes; ExtendToStructure: no; IsExternal: yes; Reference: Ext. Crépis 2 +plan 5 + BA 15; ThermalTransmittance: 5.2 kg/K/s3
Relevé de matériaux de mur détaillé - Famille et type: Mur de base: Ext. Crépis 2 +plan 5 + BA 15; sets with these values: 2
Name (Mur de base:Ext. Crépis 2 +plan 5 + BA 15:...) | Length (m) | GrossFootprintArea (m2) | GrossSideArea (m2) = Surface (m2) | GrossVolume (m3) = Volume (m3) | Longueur (m)
331405 | 9.18 | 2.0196 | 1.836 | 0.40392 | 9.234
331605 | 4.16 | 0.9152 | 0.832 | 0.18304 | 4.49

# IfcWallStandardCase: Mur de base:Ext. Voile BA 20 piscine (4)
In: PIscine
Type - PredefinedType: STANDARD; Material: Béton - Béton coulé sur place 0.2 m
Type - Autre(Type) - Catégorie: Murs; Nom de la famille: Mur de base
Type - Construction(Type) - Fonction: Extérieur; Retournement aux extrémités: Aucun(e); Retournement aux insertions: Ne pas retourner; Largeur: 0.2 m
Type - Données d'identification(Type) - Commentaires du type: Extérieur voile BA 20; Nom du type: Ext. Voile BA 20 piscine
Type - Graphismes(Type) - Couleur vue détail faible: 0
Type - Matériaux et finitions(Type) - Matériau structurel: Béton - Béton coulé sur place
Type - Propriétés analytiques(Type) - Rugosité: 3; Coefficient d'absorbance: 0.7
BaseQuantities - Height: 1.86 m; Width: 0.2 m
Autre - Catégorie: Murs; Famille: Mur de base: Ext. Voile BA 20 piscine; Famille et type: Mur de base: Ext. Voile BA 20 piscine; ID du type: Mur de base: Ext. Voile BA 20 piscine; Type: Mur de base: Ext. Voile BA 20 piscine
Contraintes - Extension inférieure: 0 m; Extension supérieure: 0 m; Lié au volume: no; Ligne de justification: Nu fini: Extérieur; Limite de pièce: yes; Partie inférieure attachée: no; Partie supérieure attachée: no; Contrainte supérieure: Niveau: RDC; Contrainte inférieure: Niveau: PIscine; Décalage inférieur: 0.2 m; Décalage supérieur: -0.14 m; Hauteur non contrainte: 1.86 m
Données d'identification - Commentaires: porteur
Phase de construction - Phase de création: Nouvelle construction
Structure - Activer le modèle analytique: yes; Enrobage d'armature - Autres faces: Paramètres de l'enrobage d'armature: Enrobage d'armature 1; Enrobage d'armature - Face extérieure: Paramètres de l'enrobage d'armature: Enrobage d'armature 1; Enrobage d'armature - Face intérieure: Paramètres de l'enrobage d'armature: Enrobage d'armature 1; Structure: yes; Utilisation structurelle: Porteur
Pset_WallCommon - LoadBearing: yes; ExtendToStructure: no; IsExternal: yes; Reference: Ext. Voile BA 20 piscine
Nomenclature de mur - Famille: Mur de base: Ext. Voile BA 20 piscine; Famille et type: Mur de base: Ext. Voile BA 20 piscine; Matériau structurel: Béton - Béton coulé sur place; Largeur: 0.2 m; Commentaires: porteur
Relevé de matériaux de mur détaillé - Famille et type: Mur de base: Ext. Voile BA 20 piscine; sets with these values: 2
Name (Mur de base:Ext. Voile BA 20 piscine:...) | Length (m) = Cotes, Longueur (m) = Nomenclature de mur, Longueur (m) | GrossFootprintArea (m2) | GrossSideArea (m2) = Cotes, Surface (m2) = Nomenclature de mur, Surface (m2) | GrossVolume (m3) = Cotes, Volume (m3) = Nomenclature de mur, Volume (m3)
472530 | 4.3 | 0.86 | 7.998 | 1.5996
472532 | 8.8 | 1.76 | 16.368 | 3.2736
472534 | 4.3 | 0.86 | 7.998 | 1.5996
472536 | 8.8 | 1.76 | 16.368 | 3.2736

# IfcWallStandardCase: Mur de base:Générique - Int. 70 mm (24)
In: RDC
Type - PredefinedType: STANDARD; Material: Mur par défaut 0.07 m
Type - Autre(Type) - Catégorie: Murs; Nom de la famille: Mur de base
Type - Construction(Type) - Retournement aux extrémités: Aucun(e); Fonction: Intérieur; Largeur: 0.07 m; Retournement aux insertions: Ne pas retourner
Type - Données d'identification(Type) - Nom du type: Générique - Int. 70 mm
Type - Graphismes(Type) - Couleur vue détail faible: 0
Type - Matériaux et finitions(Type) - Matériau structurel: Mur par défaut
Type - Propriétés analytiques(Type) - Rugosité: 3; Coefficient d'absorbance: 0.7
BaseQuantities - Width: 0.07 m
Autre - Catégorie: Murs; Famille: Mur de base: Générique - Int. 70 mm; Famille et type: Mur de base: Générique - Int. 70 mm; ID du type: Mur de base: Générique - Int. 70 mm; Type: Mur de base: Générique - Int. 70 mm
Contraintes - Contrainte inférieure: Niveau: RDC; Décalage supérieur: 0 m; Extension inférieure: 0 m; Extension supérieure: 0 m; Lié au volume: no; Ligne de justification: Nu fini: Extérieur; Limite de pièce: yes; Partie inférieure attachée: no; Contrainte supérieure: Niveau: 1er ETAGE
Phase de construction - Phase de création: Nouvelle construction
Structure - Activer le modèle analytique: no; Structure: no; Utilisation structurelle: Non porteur
Pset_WallCommon - Reference: Générique - Int. 70 mm; LoadBearing: no; IsExternal: no
Relevé de matériaux de mur détaillé - Famille et type: Mur de base: Générique - Int. 70 mm; sets with these values: 2
Name (Mur de base:Générique - Int. 70 mm:...) | Height (m) = Hauteur non contrainte (m) | Length (m) | GrossFootprintArea (m2) | GrossSideArea (m2) = Surface (m2) | GrossVolume (m3) = Volume (m3) | Décalage inférieur (m) | Partie supérieure attachée = ExtendToStructure | Longueur (m)
254809 | 3 | 5.58 | 0.3906 | 16.74 | 1.1718 | 0 | yes | 5.545
254890 | 4 | 3.04 | 0.2128 | 8.63 | 0.6041 | -1 | no | 3.04
255248 | 3 | 1.77 | 0.1239 | 3.65 | 0.2555 | 0 | no | 1.805
255872 | 3 | 0.57 | 0.0399 | 1.71 | 0.1197 | 0 | no | 0.645
255941 | 3 | 1.77 | 0.1239 | 5.31 | 0.3717 | 0 | no | 1.84
256755 | 3 | 3.645 | 0.25515 | 7.155 | 0.50085 | 0 | no | 3.645
256881 | 3 | 0.2935 | 0.020545 | 0.8805 | 0.061635 | 0 | yes | 0.3285
256999 | 3 | 3.205 | 0.22435 | 7.955 | 0.55685 | 0 | yes | 3.205
257388 | 3 | 3.2 | 0.224 | 9.6 | 0.672 | 0 | yes | 3.235
259223 | 3 | 4.3 | 0.301 | 5.8 | 0.406 | 0 | no | 4.65
259402 | 3 | 1.2 | 0.084 | 1.94 | 0.1358 | 0 | no | 1.41
259830 | 3 | 4.8 | 0.336 | 14.4 | 1.008 | 0 | no | 4.8
260345 | 3 | 0.6 | 0.042 | 1.8 | 0.126 | 0 | no | 0.6
260572 | 3 | 1.97 | 0.1379 | 5.91 | 0.4137 | 0 | no | 2.005
260920 | 3 | 3.03 | 0.2121 | 3.65 | 0.2555 | 0 | no | 3.24
261334 | 3 | 2.338 | 0.16366 | 7.014 | 0.49098 | 0 | no | 2.338
261489 | 3 | 0.46 | 0.0322 | 1.38 | 0.0966 | 0 | no | 0.53
261579 | 3 | 2.03 | 0.1421 | 6.09 | 0.4263 | 0 | no | 2.17
385713 | 3 | 0.24 | 0.0168 | 0.72 | 0.0504 | 0 | no | 0.24
385794 | 3 | 0.692 | 0.04844 | 2.076 | 0.14532 | 0 | no | 0.902
385857 | 3 | 0.24 | 0.0168 | 0.72 | 0.0504 | 0 | no | 0.24
385893 | 3 | 0.692 | 0.04844 | 2.076 | 0.14532 | 0 | no | 0.902
443604 | 3 | 0.6 | 0.042 | 1.8 | 0.126 | 0 | no | 0.635
443849 | 3 | 0.6 | 0.042 | 1.8 | 0.126 | 0 | no | 0.635

# IfcWallStandardCase: Mur de base:M7 Ext. Crépis 2 + BBMC 20 + Isolant 11 (14)
Type - PredefinedType: STANDARD; Material: Maçonnerie - Enduit 0.02 m, Blocs béton manufacturés 0.2 m, vide 0.01 m, Maçonnerie - Isolant 0.09 m, Plâtre 0.01 m
Type - Autre(Type) - Catégorie: Murs; Nom de la famille: Mur de base
Type - Construction(Type) - Fonction: Extérieur; Largeur: 0.33 m; Retournement aux extrémités: Aucun(e); Retournement aux insertions: Les deux
Type - Données d'identification(Type) - Commentaires du type: Ext. Parpaing 20 + Isolant 10; Nom du type: M7 Ext. Crépis 2 + BBMC 20 + Isolant 11
Type - Graphismes(Type) - Couleur vue détail faible: 0
Type - Matériaux et finitions(Type) - Matériau structurel: Blocs béton manufacturés
Type - Propriétés analytiques(Type) - Coefficient d'absorbance: 0.7; Coefficient de transfert de chaleur (U): 5.2; Masse thermique: 322560; Résistance thermique (R): 0.192308; Rugosité: 3
BaseQuantities - Width: 0.33 m
Autre - Catégorie: Murs; Famille: Mur de base: M7 Ext. Crépis 2 + BBMC 20 + Isolant 11; Famille et type: Mur de base: M7 Ext. Crépis 2 + BBMC 20 + Isolant 11; ID du type: Mur de base: M7 Ext. Crépis 2 + BBMC 20 + Isolant 11; Type: Mur de base: M7 Ext. Crépis 2 + BBMC 20 + Isolant 11
Contraintes - Décalage supérieur: 0 m; Extension inférieure: 0 m; Extension supérieure: 0 m; Lié au volume: no; Ligne de justification: Nu fini: Extérieur; Limite de pièce: yes; Partie inférieure attachée: no
Phase de construction - Phase de création: Nouvelle construction
Structure - Activer le modèle analytique: yes; Enrobage d'armature - Autres faces: Paramètres de l'enrobage d'armature: Enrobage d'armature 1; Enrobage d'armature - Face extérieure: Paramètres de l'enrobage d'armature: Enrobage d'armature 1; Enrobage d'armature - Face intérieure: Paramètres de l'enrobage d'armature: Enrobage d'armature 1; Structure: yes; Utilisation structurelle: Porteur
Pset_WallCommon - Reference: M7 Ext. Crépis 2 + BBMC 20 + Isolant 11; LoadBearing: yes; IsExternal: yes; ThermalTransmittance: 5.2 kg/K/s3
Relevé de matériaux de mur détaillé - Famille et type: Mur de base: M7 Ext. Crépis 2 + BBMC 20 + Isolant 11; sets with these values: 2
Name (Mur de base:M7 Ext. Crépis 2 + BBMC 20 + Isolant 11:...) | In | Height (m) | Length (m) | GrossFootprintArea (m2) | GrossSideArea (m2) = Cotes, Surface (m2) | GrossVolume (m3) = Cotes, Volume (m3) | Décalage inférieur (m) | Contrainte inférieure | Contrainte supérieure | Hauteur non contrainte (m) | Partie supérieure attachée = ExtendToStructure | Cotes, Longueur (m) | Données d'identification, Commentaires = Nomenclature de mur, Commentaires | Famille = Famille et type | Matériau structurel | Nomenclature de mur, Longueur (m) | Largeur (m) | Nomenclature de mur, Surface (m2) | Nomenclature de mur, Volume (m3)
239197 | RDC | 5.8 | 6.64 | 2.1912 | 26.7448 | 8.81219 | 0 | Niveau: RDC | Niveau: 1er Chainage | 5.8 | no | 6.475 | porteur | Mur de base: M7 Ext. Crépis 2 + BBMC 20 + Isolant 11 | Blocs béton manufacturés | 6.475 | 0.33 | 26.7448 | 8.81219
239240 | RDC | 5.8 | 14.47 | 4.7751 | 76.5836 | 25.2281 | 0 | Niveau: RDC | Niveau: 1er Chainage | 5.8 | no | 14.47 | porteur | Mur de base: M7 Ext. Crépis 2 + BBMC 20 + Isolant 11 | Blocs béton manufacturés | 14.47 | 0.33 | 76.5836 | 25.2281
239311 | RDC | 5.8 | 8.07 | 2.6631 | 44.706 | 14.753 | 0 | Niveau: RDC | Niveau: 1er Chainage | 5.8 | no | 8.07 | porteur | Mur de base: M7 Ext. Crépis 2 + BBMC 20 + Isolant 11 | Blocs béton manufacturés | 8.07 | 0.33 | 44.706 | 14.753
239378 | RDC | 5.8 | 3.37 | 1.1121 | 16.966 | 5.5557 | 0 | Niveau: RDC | Niveau: 1er Chainage | 5.8 | no | 3.37 | porteur | Mur de base: M7 Ext. Crépis 2 + BBMC 20 + Isolant 11 | Blocs béton manufacturés | 3.37 | 0.33 | 16.966 | 5.5557
239445 | RDC | 5.8 | 1.45 | 0.4785 | 8.41 | 2.7753 | 0 | Niveau: RDC | Niveau: 1er Chainage | 5.8 | no | 1.495 | porteur | Mur de base: M7 Ext. Crépis 2 + BBMC 20 + Isolant 11 | Blocs béton manufacturés | 1.495 | 0.33 | 8.41 | 2.7753
239681 | RDC | 5.8 | 1.78 | 0.5874 | 10.324 | 3.40692 | 0 | Niveau: RDC | Niveau: 1er Chainage | 5.8 | no | 1.495 | porteur | Mur de base: M7 Ext. Crépis 2 + BBMC 20 + Isolant 11 | Blocs béton manufacturés | 1.495 | 0.33 | 10.324 | 3.40692
239726 | RDC | 5.8 | 3.37 | 1.1121 | 16.966 | 5.5557 | 0 | Niveau: RDC | Niveau: 1er Chainage | 5.8 | no | 3.406 | porteur | Mur de base: M7 Ext. Crépis 2 + BBMC 20 + Isolant 11 | Blocs béton manufacturés | 3.406 | 0.33 | 16.966 | 5.5557
239803 | RDC | 5.8 | 1.43 | 0.4719 | 5.3168 | 1.74208 | 0 | Niveau: RDC | Niveau: 1er Chainage | 5.8 | no | 1.595
246804 | 1 Mur de soubassement | 3.2 | 1.82 | 0.6006 | 5.824 | 1.92192 | 0.8 | Niveau: 1 Mur de soubassement | Niveau: 1er ETAGE | 3.2 | no | 1.765 | porteur | Mur de base: M7 Ext. Crépis 2 + BBMC 20 + Isolant 11 | Blocs béton manufacturés | 1.765 | 0.33 | 5.824 | 1.92192
348224 | 1er Chainage | 0.2 | 14.14 | 4.6662 | 2.828 | 0.93324 | 0 | Niveau: 1er Chainage |  | 0.2 | no | 14.47
348364 | 1er Chainage | 0.550499 | 14.47 | 4.7751 | 7.96572 | 2.35293 | 0.2 | Niveau: 1er Chainage |  | 0.2 | yes | 14.47 | porteur | Mur de base: M7 Ext. Crépis 2 + BBMC 20 + Isolant 11 | Blocs béton manufacturés | 14.47 | 0.33 | 7.96572 | 2.35293
348366 | 1er Chainage | 1.905 | 8.07 | 2.6631 | 9.66537 | 3.18957 | 0.2 | Niveau: 1er Chainage |  | 0.2 | yes | 8.07 | porteur | Mur de base: M7 Ext. Crépis 2 + BBMC 20 + Isolant 11 | Blocs béton manufacturés | 8.07 | 0.33 | 9.66537 | 3.18957
348368 | 1er Chainage | 0.550499 | 14.47 | 4.7751 | 7.96572 | 2.35293 | 0.2 | Niveau: 1er Chainage |  | 0.2 | yes | 14.47 | porteur | Mur de base: M7 Ext. Crépis 2 + BBMC 20 + Isolant 11 | Blocs béton manufacturés | 14.47 | 0.33 | 7.96572 | 2.35293
348370 | 1er Chainage | 1.905 | 8.07 | 2.6631 | 9.66537 | 3.18957 | 0.2 | Niveau: 1er Chainage |  | 0.2 | yes | 8.07 | porteur | Mur de base: M7 Ext. Crépis 2 + BBMC 20 + Isolant 11 | Blocs béton manufacturés | 8.07 | 0.33 | 9.66537 | 3.18957

# IfcWallStandardCase: Mur de base:M8 Ext. Bois 2 + Isolant 12 + BBMC 20 + vide 1 + ba13 (5)
In: RDC
Type - PredefinedType: STANDARD; Material: Bardage bois 0.01 m, Maçonnerie - Isolant 0.12 m, Blocs béton manufacturés 0.2 m, Par défaut 0.01 m, Plâtre 0.01 m
Type - Autre(Type) - Catégorie: Murs; Nom de la famille: Mur de base
Type - Construction(Type) - Fonction: Extérieur; Retournement aux extrémités: Aucun(e); Retournement aux insertions: Les deux; Largeur: 0.35 m
Type - Données d'identification(Type) - Commentaires du type: Ext. Parpaing 20 + Isolant 10; Nom du type: M8 Ext. Bois 2 + Isolant 12 + BBMC 20 + vide 1 + ba13
Type - Graphismes(Type) - Couleur vue détail faible: 0
Type - Matériaux et finitions(Type) - Matériau structurel: Blocs béton manufacturés
Type - Propriétés analytiques(Type) - Rugosité: 3; Coefficient d'absorbance: 0.7; Coefficient de transfert de chaleur (U): 4.77551; Masse thermique: 313445; Résistance thermique (R): 0.209402
BaseQuantities - Height: 3 m; Width: 0.35 m
Autre - Catégorie: Murs; Famille: Mur de base: M8 Ext. Bois 2 + Isolant 12 + BBMC 20 + vide 1 + ba13; Famille et type: Mur de base: M8 Ext. Bois 2 + Isolant 12 + BBMC 20 + vide 1 + ba13; ID du type: Mur de base: M8 Ext. Bois 2 + Isolant 12 + BBMC 20 + vide 1 + ba13; Type: Mur de base: M8 Ext. Bois 2 + Isolant 12 + BBMC 20 + vide 1 + ba13
Contraintes - Décalage inférieur: 0 m; Contrainte inférieure: Niveau: RDC; Décalage supérieur: 0 m; Extension inférieure: 0 m; Extension supérieure: 0 m; Lié au volume: no; Ligne de justification: Nu fini: Extérieur; Limite de pièce: yes; Partie inférieure attachée: no; Partie supérieure attachée: no; Contrainte supérieure: Niveau: 1er ETAGE; Hauteur non contrainte: 3 m
Données d'identification - Commentaires: porteur
Phase de construction - Phase de création: Nouvelle construction
Structure - Activer le modèle analytique: yes; Enrobage d'armature - Autres faces: Paramètres de l'enrobage d'armature: Enrobage d'armature 1; Enrobage d'armature - Face extérieure: Paramètres de l'enrobage d'armature: Enrobage d'armature 1; Enrobage d'armature - Face intérieure: Paramètres de l'enrobage d'armature: Enrobage d'armature 1; Structure: yes; Utilisation structurelle: Porteur
Pset_WallCommon - LoadBearing: yes; ExtendToStructure: no; IsExternal: yes; Reference: M8 Ext. Bois 2 + Isolant 12 + BBMC 20 + vide 1 + ba13; ThermalTransmittance: 4.77551 kg/K/s3
Nomenclature de mur - Famille: Mur de base: M8 Ext. Bois 2 + Isolant 12 + BBMC 20 + vide 1 + ba13; Famille et type: Mur de base: M8 Ext. Bois 2 + Isolant 12 + BBMC 20 + vide 1 + ba13; Matériau structurel: Blocs béton manufacturés; Largeur: 0.35 m; Commentaires: porteur
Relevé de matériaux de mur détaillé - Famille et type: Mur de base: M8 Ext. Bois 2 + Isolant 12 + BBMC 20 + vide 1 + ba13; sets with these values: 2
Name (Mur de base:M8 Ext. Bois 2 + Isolant 12 + BBMC 20 + vide 1 + ba13:...) | Length (m) | GrossFootprintArea (m2) | GrossSideArea (m2) = Cotes, Surface (m2) = Nomenclature de mur, Surface (m2) | GrossVolume (m3) = Cotes, Volume (m3) = Nomenclature de mur, Volume (m3) | Cotes, Longueur (m) = Nomenclature de mur, Longueur (m)
253071 | 3.565 | 1.24775 | 5.46689 | 1.9077 | 3.39
253190 | 4.65 | 1.6275 | 12.23 | 4.25178 | 4.65
253549 | 12.54 | 4.389 | 35.9 | 12.5363 | 12.54
253662 | 4.65 | 1.6275 | 13.09 | 4.56714 | 4.65
253777 | 8.975 | 3.14125 | 17.0169 | 5.90712 | 9.15

# IfcWallStandardCase: Mur de base:Mur soubassement BB 20 (21)
Type - PredefinedType: STANDARD; Material: Blocs béton manufacturés 0.2 m
Type - Autre(Type) - Catégorie: Murs; Nom de la famille: Mur de base
Type - Construction(Type) - Fonction: Extérieur; Retournement aux extrémités: Aucun(e); Retournement aux insertions: Ne pas retourner; Largeur: 0.2 m
Type - Données d'identification(Type) - Nom du type: Mur soubassement BB 20
Type - Graphismes(Type) - Couleur vue détail faible: 0
Type - Matériaux et finitions(Type) - Matériau structurel: Blocs béton manufacturés
Type - Propriétés analytiques(Type) - Rugosité: 3; Coefficient d'absorbance: 0.7; Coefficient de transfert de chaleur (U): 6.5; Masse thermique: 302400; Résistance thermique (R): 0.153846
BaseQuantities - Width: 0.2 m
Autre - Catégorie: Murs; Famille: Mur de base: Mur soubassement BB 20; Famille et type: Mur de base: Mur soubassement BB 20; ID du type: Mur de base: Mur soubassement BB 20; Type: Mur de base: Mur soubassement BB 20
Contraintes - Extension inférieure: 0 m; Extension supérieure: 0 m; Lié au volume: no; Limite de pièce: yes; Partie inférieure attachée: no; Partie supérieure attachée: no; Contrainte supérieure: Niveau: RDC
Données d'identification - Commentaires: porteur
Phase de construction - Phase de création: Nouvelle construction
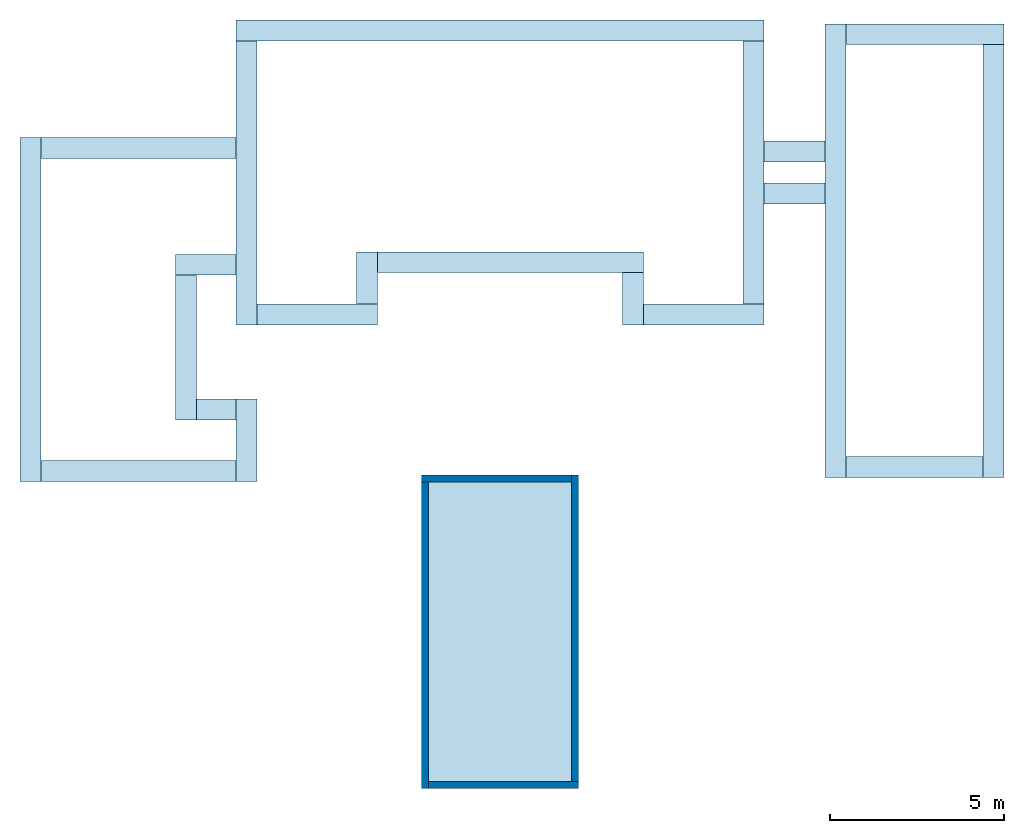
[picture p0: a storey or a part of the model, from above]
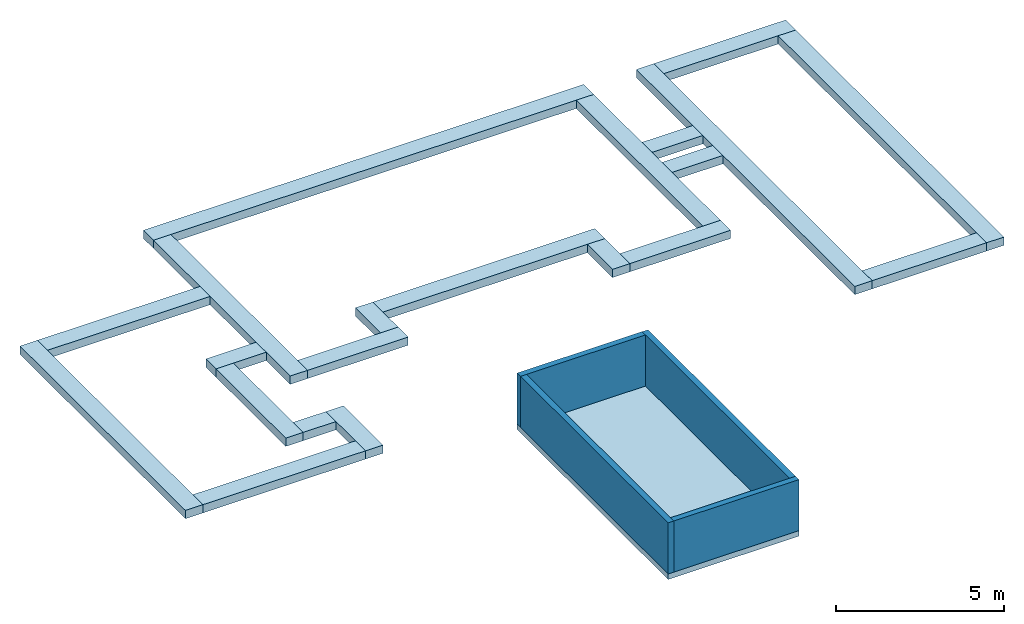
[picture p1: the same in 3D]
Properties of the parts of a building model (IFC2X3), part 4 of 4

# IfcWallStandardCase: Mur de base:Mur soubassement BB 20 (21)
Structure - Activer le modèle analytique: yes; Enrobage d'armature - Autres faces: Paramètres de l'enrobage d'armature: Enrobage d'armature 1; Enrobage d'armature - Face extérieure: Paramètres de l'enrobage d'armature: Enrobage d'armature 1; Enrobage d'armature - Face intérieure: Paramètres de l'enrobage d'armature: Enrobage d'armature 1; Structure: yes; Utilisation structurelle: Porteur
Pset_WallCommon - LoadBearing: yes; ExtendToStructure: no; IsExternal: yes; Reference: Mur soubassement BB 20; ThermalTransmittance: 6.5 kg/K/s3
Nomenclature de mur - Famille: Mur de base: Mur soubassement BB 20; Famille et type: Mur de base: Mur soubassement BB 20; Matériau structurel: Blocs béton manufacturés; Largeur: 0.2 m; Commentaires: porteur
Relevé de matériaux de mur détaillé - Famille et type: Mur de base: Mur soubassement BB 20; sets with these values: 2
Name (Mur de base:Mur soubassement BB 20:...) | In | Height (m) = Hauteur non contrainte (m) | Length (m) | GrossFootprintArea (m2) | GrossSideArea (m2) = Cotes, Surface (m2) = Nomenclature de mur, Surface (m2) | GrossVolume (m3) = Cotes, Volume (m3) = Nomenclature de mur, Volume (m3) | Décalage inférieur (m) | Ligne de justification | Contrainte inférieure | Décalage supérieur (m) | Cotes, Longueur (m) = Nomenclature de mur, Longueur (m)
350740 | 1 Mur de soubassement | 0.68 | 14.76 | 2.952 | 10.0368 | 2.00736 | 0 | Nu fini: Extérieur | Niveau: 1 Mur de soubassement | -0.32 | 14.56
350925 | 1 Mur de soubassement | 0.68 | 8.15612 | 1.63122 | 5.54616 | 1.10923 | 0 | Nu fini: Extérieur | Niveau: 1 Mur de soubassement | -0.32 | 8.15612
351126 | 1 Mur de soubassement | 0.68 | 3.46 | 0.692 | 2.3528 | 0.47056 | 0 | Nu fini: Extérieur | Niveau: 1 Mur de soubassement | -0.32 | 3.46
351295 | 1 Mur de soubassement | 0.68 | 1.5 | 0.3 | 1.02 | 0.204 | 0 | Nu fini: Extérieur | Niveau: 1 Mur de soubassement | -0.32 | 1.5
351494 | 1 Mur de soubassement | 0.68 | 7.64 | 1.528 | 5.1952 | 1.03904 | 0 | Nu fini: Extérieur | Niveau: 1 Mur de soubassement | -0.32 | 7.64
351867 | 1 Mur de soubassement | 0.68 | 1.5 | 0.3 | 1.02 | 0.204 | 0 | Nu fini: Extérieur | Niveau: 1 Mur de soubassement | -0.32 | 1.5
352002 | 1 Mur de soubassement | 0.68 | 3.46 | 0.692 | 2.3528 | 0.47056 | 0 | Nu fini: Extérieur | Niveau: 1 Mur de soubassement | -0.32 | 3.46
352287 | 1 Mur de soubassement | 0.68 | 7.95612 | 1.59122 | 5.41016 | 1.08203 | 0 | Nu fini: Extérieur | Niveau: 1 Mur de soubassement | -0.32 | 8.15612
352718 | 1 Mur de soubassement | 0.68 | 2.15093 | 0.430185 | 1.46263 | 0.292526 | 0 | Nu fini: Extérieur | Niveau: 1 Mur de soubassement | -0.32 | 2.35093
353012 | 1 Mur de soubassement | 0.68 | 2.15093 | 0.430185 | 1.46263 | 0.292526 | 0 | Nu fini: Extérieur | Niveau: 1 Mur de soubassement | -0.32 | 2.35093
353340 | 1 Mur de soubassement | 0.68 | 4.73907 | 0.947815 | 3.22257 | 0.644514 | 0 | Nu fini: Extérieur | Niveau: 1 Mur de soubassement | -0.32 | 4.53907
353782 | 1 Mur de soubassement | 0.68 | 12.43 | 2.486 | 8.4524 | 1.69048 | 0 | Nu fini: Extérieur | Niveau: 1 Mur de soubassement | -0.32 | 12.43
353974 | 1 Mur de soubassement | 0.68 | 4.53907 | 0.907815 | 3.08657 | 0.617314 | 0 | Nu fini: Extérieur | Niveau: 1 Mur de soubassement | -0.32 | 4.53907
354334 | 1 Mur de soubassement | 0.68 | 12.23 | 2.446 | 8.3164 | 1.66328 | 0 | Nu fini: Extérieur | Niveau: 1 Mur de soubassement | -0.32 | 12.43
364137 | RDC | 0.8 | 1.73 | 0.346 | 1.384 | 0.2768 | -1 | Nu fini: Extérieur | Niveau: RDC | -0.2 | 1.73
514964 | 1 Mur de soubassement | 0.85 | 9.47 | 1.894 | 8.04163 | 1.60833 | 0 | Nu fini: Extérieur | Niveau: 1 Mur de soubassement | -0.15 | 9.29
515261 | 1 Mur de soubassement | 1 | 1.96 | 0.392 | 1.90007 | 0.380015 | 0 | Axe porteur | Niveau: 1 Mur de soubassement | 0 | 1.78
515865 | 1 Mur de soubassement | 0.853071 | 6 | 1.2 | 5.11843 | 1.02369 | 0 | Nu fini: Intérieur | Niveau: 1 Mur de soubassement | -0.146929 | 6.22
516374 | 1 Mur de soubassement | 0.810658 | 6 | 1.2 | 4.86395 | 0.972789 | 0 | Nu fini: Extérieur | Niveau: 1 Mur de soubassement | -0.189342 | 6.21
516638 | 1 Mur de soubassement | 0.85 | 4.16 | 0.832 | 3.536 | 0.7072 | 0 | Nu fini: Extérieur | Niveau: 1 Mur de soubassement | -0.15 | 4.16
517038 | 1 Mur de soubassement | 0.847301 | 1.53 | 0.306 | 1.29637 | 0.259274 | 0 | Nu fini: Extérieur | Niveau: 1 Mur de soubassement | -0.152699 | 1.74

# IfcWallStandardCase: Mur de base:Poutre ba + Enduit 2 sur 2 faces, Mur de base:Poutre ba + Enduit 2 sur 2 faces:357906
In: Mur rideau
Type - PredefinedType: STANDARD; Material: Finition Peinture - Blanc satiné 0.02 m, Maçonnerie - Voile BA 0.2 m, Maçonnerie - Enduit 0.02 m
Type - Autre(Type) - Catégorie: Murs; Nom de la famille: Mur de base
Type - Construction(Type) - Fonction: Extérieur; Retournement aux extrémités: Aucun(e); Retournement aux insertions: Les deux; Largeur: 0.24 m
Type - Données d'identification(Type) - Commentaires du type: Extérieur voile BA 20 + Isolant 10; Nom du type: Poutre ba + Enduit 2 sur 2 faces
Type - Graphismes(Type) - Couleur vue détail faible: 0
Type - Matériaux et finitions(Type) - Matériau structurel: Maçonnerie - Voile BA
Type - Propriétés analytiques(Type) - Rugosité: 3; Coefficient d'absorbance: 0.7; Coefficient de transfert de chaleur (U): 26; Masse thermique: 20160; Résistance thermique (R): 0.0384615
BaseQuantities - Height: 0.8 m; Length: 7.4 m; Width: 0.24 m; GrossFootprintArea: 1.776 m2; GrossSideArea: 5.92 m2; GrossVolume: 1.4208 m3
Autre - Catégorie: Murs; Famille: Mur de base: Poutre ba + Enduit 2 sur 2 faces; Famille et type: Mur de base: Poutre ba + Enduit 2 sur 2 faces; ID du type: Mur de base: Poutre ba + Enduit 2 sur 2 faces; Type: Mur de base: Poutre ba + Enduit 2 sur 2 faces
Contraintes - Décalage inférieur: 0 m; Extension inférieure: 0 m; Extension supérieure: 0 m; Lié au volume: no; Ligne de justification: Nu fini: Extérieur; Limite de pièce: yes; Partie inférieure attachée: no; Partie supérieure attachée: no; Contrainte inférieure: Niveau: Mur rideau; Décalage supérieur: -0.32 m; Hauteur non contrainte: 0.8 m
Cotes - Longueur: 7.73 m; Surface: 5.92 m2; Volume: 1.4208 m3
Phase de construction - Phase de création: Nouvelle construction
Structure - Activer le modèle analytique: yes; Enrobage d'armature - Autres faces: Paramètres de l'enrobage d'armature: Enrobage d'armature 1; Enrobage d'armature - Face extérieure: Paramètres de l'enrobage d'armature: Enrobage d'armature 1; Enrobage d'armature - Face intérieure: Paramètres de l'enrobage d'armature: Enrobage d'armature 1; Structure: yes; Utilisation structurelle: Porteur
Pset_WallCommon - LoadBearing: yes; ExtendToStructure: no; IsExternal: yes; Reference: Poutre ba + Enduit 2 sur 2 faces; ThermalTransmittance: 26 kg/K/s3
Relevé de matériaux de mur détaillé - Famille et type: Mur de base: Poutre ba + Enduit 2 sur 2 faces; sets with these values: 2

# IfcWallStandardCase: Mur de base:Tableau Mondrian (2)
In: RDC
Type - PredefinedType: STANDARD; Material: Tableau Mondrian 0.03 m
Type - Autre(Type) - Catégorie: Murs; Nom de la famille: Mur de base
Type - Construction(Type) - Fonction: Extérieur; Retournement aux extrémités: Aucun(e); Retournement aux insertions: Les deux; Largeur: 0.03 m
Type - Données d'identification(Type) - Commentaires du type: Ext. Parpaing 20 + Isolant 10; Nom du type: Tableau Mondrian
Type - Graphismes(Type) - Couleur vue détail faible: 0
Type - Propriétés analytiques(Type) - Rugosité: 3; Coefficient d'absorbance: 0.7
BaseQuantities - Height: 1.2 m; Width: 0.03 m
Autre - Catégorie: Murs; Famille: Mur de base: Tableau Mondrian; Famille et type: Mur de base: Tableau Mondrian; ID du type: Mur de base: Tableau Mondrian; Type: Mur de base: Tableau Mondrian
Contraintes - Contrainte inférieure: Niveau: RDC; Décalage supérieur: 0 m; Extension inférieure: 0 m; Extension supérieure: 0 m; Lié au volume: no; Limite de pièce: yes; Partie inférieure attachée: no; Partie supérieure attachée: no; Ligne de justification: Axe du mur; Décalage inférieur: 1 m; Hauteur non contrainte: 1.2 m
Phase de construction - Phase de création: Nouvelle construction
Structure - Activer le modèle analytique: no; Structure: no; Utilisation structurelle: Non porteur
Pset_WallCommon - ExtendToStructure: no; IsExternal: yes; LoadBearing: no; Reference: Tableau Mondrian
Relevé de matériaux de mur détaillé - Famille et type: Mur de base: Tableau Mondrian; sets with these values: 2
Name (Mur de base:Tableau Mondrian:...) | Length (m) = Longueur (m) | GrossFootprintArea (m2) | GrossSideArea (m2) = Surface (m2) | GrossVolume (m3) = Volume (m3)
531075 | 1.6 | 0.048 | 1.92 | 0.0576
532211 | 1.2 | 0.036 | 1.44 | 0.0432

# IfcWallStandardCase: Mur de base:Tableau chambre 1, Mur de base:Tableau chambre 1:532745
In: RDC
Type - PredefinedType: STANDARD; Material: Tableau chambre 1 0.03 m
Type - Autre(Type) - Catégorie: Murs; Nom de la famille: Mur de base
Type - Construction(Type) - Fonction: Extérieur; Retournement aux extrémités: Aucun(e); Retournement aux insertions: Les deux; Largeur: 0.03 m
Type - Données d'identification(Type) - Commentaires du type: Ext. Parpaing 20 + Isolant 10; Nom du type: Tableau chambre 1
Type - Graphismes(Type) - Couleur vue détail faible: 0
Type - Propriétés analytiques(Type) - Rugosité: 3; Coefficient d'absorbance: 0.7
BaseQuantities - Height: 1 m; Length: 1.7 m; Width: 0.03 m; GrossFootprintArea: 0.051 m2; GrossSideArea: 1.7 m2; GrossVolume: 0.051 m3
Autre - Catégorie: Murs; Famille: Mur de base: Tableau chambre 1; Famille et type: Mur de base: Tableau chambre 1; ID du type: Mur de base: Tableau chambre 1; Type: Mur de base: Tableau chambre 1
Contraintes - Contrainte inférieure: Niveau: RDC; Décalage supérieur: 0 m; Extension inférieure: 0 m; Extension supérieure: 0 m; Lié au volume: no; Limite de pièce: yes; Partie inférieure attachée: no; Partie supérieure attachée: no; Ligne de justification: Axe du mur; Décalage inférieur: 1.2 m; Hauteur non contrainte: 1 m
Cotes - Longueur: 1.7 m; Surface: 1.7 m2; Volume: 0.051 m3
Phase de construction - Phase de création: Nouvelle construction
Structure - Activer le modèle analytique: no; Structure: no; Utilisation structurelle: Non porteur
Pset_WallCommon - ExtendToStructure: no; IsExternal: yes; LoadBearing: no; Reference: Tableau chambre 1
Relevé de matériaux de mur détaillé - Famille et type: Mur de base: Tableau chambre 1; sets with these values: 2

# IfcWallStandardCase: Mur de base:Tableau visage, Mur de base:Tableau visage:531533
In: RDC
Type - PredefinedType: STANDARD; Material: Tableau visage 0.03 m
Type - Autre(Type) - Catégorie: Murs; Nom de la famille: Mur de base
Type - Construction(Type) - Fonction: Extérieur; Retournement aux extrémités: Aucun(e); Retournement aux insertions: Les deux; Largeur: 0.03 m
Type - Données d'identification(Type) - Commentaires du type: Ext. Parpaing 20 + Isolant 10; Nom du type: Tableau visage
Type - Graphismes(Type) - Couleur vue détail faible: 0
Type - Propriétés analytiques(Type) - Rugosité: 3; Coefficient d'absorbance: 0.7
BaseQuantities - Height: 1.2 m; Length: 1.2 m; Width: 0.03 m; GrossFootprintArea: 0.036 m2; GrossSideArea: 1.44 m2; GrossVolume: 0.0432 m3
Autre - Catégorie: Murs; Famille: Mur de base: Tableau visage; Famille et type: Mur de base: Tableau visage; ID du type: Mur de base: Tableau visage; Type: Mur de base: Tableau visage
Contraintes - Contrainte inférieure: Niveau: RDC; Décalage supérieur: 0 m; Extension inférieure: 0 m; Extension supérieure: 0 m; Lié au volume: no; Limite de pièce: yes; Partie inférieure attachée: no; Partie supérieure attachée: no; Ligne de justification: Axe du mur; Décalage inférieur: 1 m; Hauteur non contrainte: 1.2 m
Cotes - Longueur: 1.2 m; Surface: 1.44 m2; Volume: 0.0432 m3
Phase de construction - Phase de création: Nouvelle construction
Structure - Activer le modèle analytique: no; Structure: no; Utilisation structurelle: Non porteur
Pset_WallCommon - ExtendToStructure: no; IsExternal: yes; LoadBearing: no; Reference: Tableau visage
Relevé de matériaux de mur détaillé - Famille et type: Mur de base: Tableau visage; sets with these values: 2

# IfcWindow: 0.40m x2.15m (20)
In: RDC
Type - OperationType: SINGLE_PANEL; ParameterTakesPrecedence: no; Sizeable: no; Material: Fenêtre - Appui, Fenêtre - Vitrage, Fenêtre - Cadre
Type - Autre(Type) - Catégorie: Fenêtres; Nom de la famille: 1 Vantail - Droit
Type - Construction(Type) - Fermeture du mur: Extérieur; Appui Alu: yes
Type - Contraintes(Type) - A: 0 m; A. App.: 96 deg; H. App: 0.015 m
Type - Cotes(Type) - Ep. Isolant: 0.1 m; Hauteur: 2.15 m; Hauteur de la poignée: 1.4 m; Largeur: 0.4 m
Type - Données d'identification(Type) - Marque de type: 20; Nom du type: 0.40m x2.15m
Type - Matériaux et finitions(Type) - Appui: Fenêtre - Appui; Fenêtre: Fenêtre - Cadre; Poignée: Fenêtre - Poignée; Tapées: Fenêtre - Cadre; Vitrage: Fenêtre - Vitrage
Type - Propriétés analytiques(Type) - Construction analytique: <Aucun>
OverallHeight: 2.28 m; OverallWidth: 0.5 m
Pset_WindowCommon - IsExternal: yes; Reference: 0.40m x2.15m
Nomenclature des fenêtres - Hauteur de l'appui: 0 m; Famille et type: 1 Vantail - Droit: 0.40m x2.15m; Largeur: 0.4 m; Hauteur: 2.15 m; Niveau: Niveau: RDC
BaseQuantities - Height: 2.15 m; Width: 0.4 m; Area: 0.86 m2
Autre - Catégorie: Fenêtres; Famille: 1 Vantail - Droit: 0.40m x2.15m; Famille et type: 1 Vantail - Droit: 0.40m x2.15m; Hauteur sous linteau: 2.15 m; ID du type: 1 Vantail - Droit: 0.40m x2.15m; Type: 1 Vantail - Droit: 0.40m x2.15m
Contraintes - Hauteur de l'appui: 0 m; Niveau: Niveau: RDC
Graphismes - Encadrement intérieur: no; A battant: yes; A soufflet: yes
Phase de construction - Phase de création: Nouvelle construction
Name (1 Vantail - Droit:0.40m x2.15m:...) | ID hôte | Surface (m2) | Volume (m3) | Identifiant
288996 | Mur de base: M7 Ext. Crépis 2 + BBMC 20 + Isolant 11 | 2.2295 | 0.0342708 | 3
289064 | Mur de base: M7 Ext. Crépis 2 + BBMC 20 + Isolant 11 | 2.2295 | 0.0342708 | 4
289102 | Mur de base: M7 Ext. Crépis 2 + BBMC 20 + Isolant 11 | 2.2295 | 0.0342708 | 5
289275 | Mur de base: M7 Ext. Crépis 2 + BBMC 20 + Isolant 11 | 2.2295 | 0.0342708 | 6
289438 | Mur de base: M7 Ext. Crépis 2 + BBMC 20 + Isolant 11 | 2.2295 | 0.0342708 | 7
289479 | Mur de base: M7 Ext. Crépis 2 + BBMC 20 + Isolant 11 | 2.2295 | 0.0342708 | 8
289549 | Mur de base: M8 Ext. Bois 2 + Isolant 12 + BBMC 20 + vide 1 + ba13 | 2.24608 | 0.0343128 | 9
289616 | Mur de base: M8 Ext. Bois 2 + Isolant 12 + BBMC 20 + vide 1 + ba13 | 2.24608 | 0.0343128 | 10
289713 | Mur de base: M7 Ext. Crépis 2 + BBMC 20 + Isolant 11 | 2.2295 | 0.0342708 | 11
289767 | Mur de base: M7 Ext. Crépis 2 + BBMC 20 + Isolant 11 | 2.2295 | 0.0342708 | 12
289814 | Mur de base: M7 Ext. Crépis 2 + BBMC 20 + Isolant 11 | 2.2295 | 0.0342708 | 13
289856 | Mur de base: M7 Ext. Crépis 2 + BBMC 20 + Isolant 11 | 2.2295 | 0.0342708 | 14
289919 | Mur de base: Ext. Crépis 2 + BBMC 20 | 2.13757 | 0.0340395 | 15
290048 | Mur de base: Ext. Crépis 2 + BBMC 20 | 2.13757 | 0.0340395 | 16
291094 | Mur de base: M8 Ext. Bois 2 + Isolant 12 + BBMC 20 + vide 1 + ba13 | 2.24608 | 0.0343128 | 17
291145 | Mur de base: M8 Ext. Bois 2 + Isolant 12 + BBMC 20 + vide 1 + ba13 | 2.24608 | 0.0343128 | 18
291181 | Mur de base: M8 Ext. Bois 2 + Isolant 12 + BBMC 20 + vide 1 + ba13 | 2.24608 | 0.0343128 | 19
291288 | Mur de base: M8 Ext. Bois 2 + Isolant 12 + BBMC 20 + vide 1 + ba13 | 2.24608 | 0.0343128 | 20
291333 | Mur de base: M8 Ext. Bois 2 + Isolant 12 + BBMC 20 + vide 1 + ba13 | 2.24608 | 0.0343128 | 21
291383 | Mur de base: M8 Ext. Bois 2 + Isolant 12 + BBMC 20 + vide 1 + ba13 | 2.24608 | 0.0343128 | 22

# IfcWindow: 2.20 x 0.55 (3)
Type - OperationType: SINGLE_PANEL; ParameterTakesPrecedence: no; Sizeable: no; Material: Fenêtre - Appui, Fenêtre - Vitrage, Fenêtre - Cadre
Type - Autre(Type) - Catégorie: Fenêtres; Nom de la famille: 1 Vantail - Droit
Type - Construction(Type) - Fermeture du mur: Extérieur; Appui Alu: yes
Type - Contraintes(Type) - A: 0 m; A. App.: 96 deg; H. App: 0.015 m
Type - Cotes(Type) - Ep. Isolant: 0.1 m; Hauteur: 0.55 m; Hauteur de la poignée: 1.4 m; Largeur: 2.2 m
Type - Données d'identification(Type) - Marque de type: 21; Nom du type: 2.20 x 0.55
Type - Matériaux et finitions(Type) - Appui: Fenêtre - Appui; Fenêtre: Fenêtre - Cadre; Poignée: Fenêtre - Poignée; Tapées: Fenêtre - Cadre; Vitrage: Fenêtre - Vitrage
Type - Propriétés analytiques(Type) - Construction analytique: <Aucun>
OverallHeight: 1.08 m; OverallWidth: 2.3 m
Pset_WindowCommon - IsExternal: yes; Reference: 2.20 x 0.55
Nomenclature des fenêtres - Famille et type: 1 Vantail - Droit: 2.20 x 0.55; Largeur: 2.2 m; Hauteur: 0.55 m; Hauteur de l'appui: 1.2 m
BaseQuantities - Height: 0.55 m; Width: 2.2 m; Area: 1.21 m2
Autre - ID hôte: Mur de base: M7 Ext. Crépis 2 + BBMC 20 + Isolant 11; Catégorie: Fenêtres; Famille: 1 Vantail - Droit: 2.20 x 0.55; Famille et type: 1 Vantail - Droit: 2.20 x 0.55; Hauteur sous linteau: 1.75 m; ID du type: 1 Vantail - Droit: 2.20 x 0.55; Type: 1 Vantail - Droit: 2.20 x 0.55
Contraintes - Hauteur de l'appui: 1.2 m
Cotes - Surface: 3.70168 m2; Volume: 0.0444747 m3
Graphismes - Encadrement intérieur: no; A battant: yes; A soufflet: yes
Phase de construction - Phase de création: Nouvelle construction
Name (1 Vantail - Droit:2.20 x 0.55:...) | In | Nomenclature des fenêtres, Niveau = Contraintes, Niveau | Identifiant
491480 | RDC | Niveau: RDC | 23
510703 | 1er ETAGE | Niveau: 1er ETAGE | 24
510756 | 1er ETAGE | Niveau: 1er ETAGE | 25

# IfcWindow: 2.40m x 2.15m (2)
In: RDC
Type - OperationType: DOUBLE_PANEL_VERTICAL; ParameterTakesPrecedence: no; Sizeable: no; Material: Fenêtre - Appui, Fenêtre - Cadre, Fenêtre - Vitrage
Type - Autre(Type) - Catégorie: Fenêtres; Nom de la famille: PF 2 Vantaux - Droits
Type - Construction(Type) - Fermeture du mur: Extérieur
Type - Cotes(Type) - Ep. Isolant: 0.1 m; Hauteur: 2.15 m; Hauteur de la poignée: 1.1 m; Largeur: 2.4 m
Type - Données d'identification(Type) - Coût: 1800; Fabricant: Technal; Marque de type: 16; Modèle: PF2V; Nom du type: 2.40m x 2.15m; URL: https://www.technal.com/fr/fr/particuliers/menuiserie/
Type - Matériaux et finitions(Type) - Appui: Fenêtre - Appui; Fenêtre: Fenêtre - Cadre; Poignée: Fenêtre - Poignée; Tapées: Fenêtre - Cadre; Vitrage: Fenêtre - Vitrage
Type - Propriétés analytiques(Type) - Coefficient d'apport thermique solaire: 0.39; Coefficient de transfert de chaleur (U): 1.9873; Construction analytique: Double vitrage - 1/4 po. d'épaisseur - verre bleu vert/énergétique (e = 0.1); Résistance thermique (R): 0.503195; Transmission de la lumière visible: 0.62
OverallHeight: 2.265 m; OverallWidth: 2.5 m
Pset_WindowCommon - IsExternal: yes; Reference: 2.40m x 2.15m; ThermalTransmittance: 1.9873 kg/K/s3
Pset_ManufacturerTypeInformation - Manufacturer: Technal
Nomenclature des fenêtres - Famille et type: PF 2 Vantaux - Droits: 2.40m x 2.15m; Largeur: 2.4 m; Hauteur: 2.15 m; Niveau: Niveau: RDC; Hauteur de l'appui: 0.035 m
BaseQuantities - Height: 2.15 m; Width: 2.4 m; Area: 5.16 m2
Autre - ID hôte: Mur de base: M8 Ext. Bois 2 + Isolant 12 + BBMC 20 + vide 1 + ba13; Catégorie: Fenêtres; Famille: PF 2 Vantaux - Droits: 2.40m x 2.15m; Famille et type: PF 2 Vantaux - Droits: 2.40m x 2.15m; Hauteur sous linteau: 2.185 m; ID du type: PF 2 Vantaux - Droits: 2.40m x 2.15m; Type: PF 2 Vantaux - Droits: 2.40m x 2.15m
Contraintes - Niveau: Niveau: RDC; Hauteur de l'appui: 0.035 m
Cotes - Surface: 7.93092 m2; Volume: 0.113144 m3
Graphismes - Encadrement intérieur: no
Phase de construction - Phase de création: Nouvelle construction
Name (PF 2 Vantaux - Droits:2.40m x 2.15m:...) | Identifiant
281137 | 1
281379 | 2
